VERSION 5.8 ;
BUSBITCHARS "[]" ;
DIVIDERCHAR "/" ;
UNITS
    DATABASE MICRONS 1000 ;
END UNITS

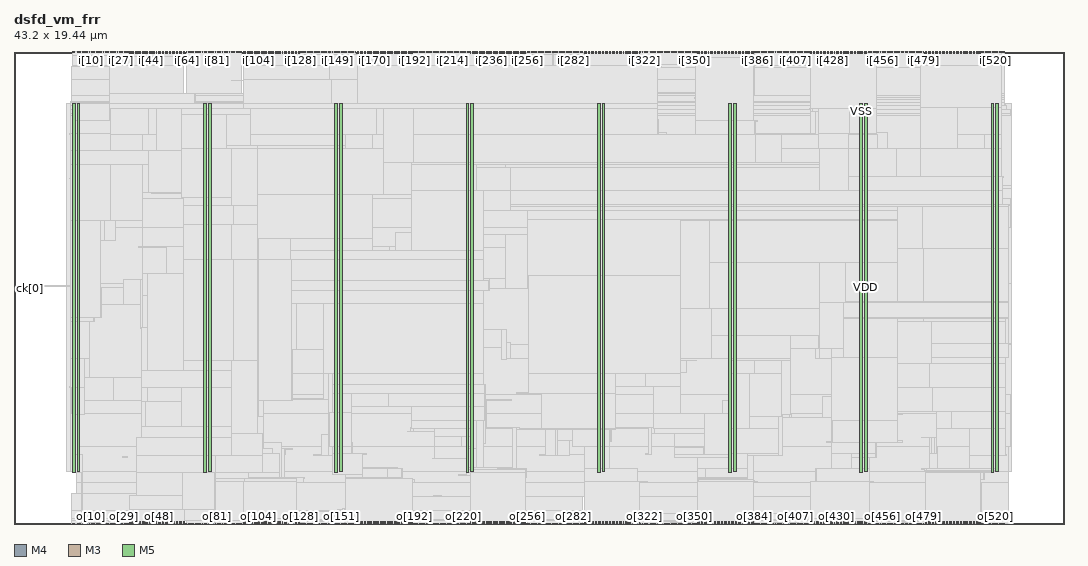
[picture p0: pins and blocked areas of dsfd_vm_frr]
MACRO dsfd_vm_frr
  FOREIGN dsfd_vm_frr 0 0 ;
  CLASS BLOCK ;
  SIZE 43.2 BY 19.44 ;
  PIN ck[0]
    DIRECTION INPUT ;
    USE SIGNAL ;
    PORT
      LAYER M4 ;
        RECT  0 9.696 0.084 9.72 ;
    END
    PORT
      LAYER M4 ;
        RECT  0.06 9.696 0.097 9.72 ;
    END
  END ck[0]
  PIN i[0]
    DIRECTION INPUT ;
    USE SIGNAL ;
    PORT
      LAYER M3 ;
        RECT  2.412 19.402 2.43 19.44 ;
    END
  END i[0]
  PIN i[100]
    DIRECTION INPUT ;
    USE SIGNAL ;
    PORT
      LAYER M5 ;
        RECT  9.744 19.356 9.768 19.44 ;
    END
  END i[100]
  PIN i[101]
    DIRECTION INPUT ;
    USE SIGNAL ;
    PORT
      LAYER M5 ;
        RECT  9.792 19.356 9.816 19.44 ;
    END
  END i[101]
  PIN i[102]
    DIRECTION INPUT ;
    USE SIGNAL ;
    PORT
      LAYER M5 ;
        RECT  9.888 19.356 9.912 19.44 ;
    END
  END i[102]
  PIN i[103]
    DIRECTION INPUT ;
    USE SIGNAL ;
    PORT
      LAYER M5 ;
        RECT  9.936 19.356 9.96 19.44 ;
    END
  END i[103]
  PIN i[104]
    DIRECTION INPUT ;
    USE SIGNAL ;
    PORT
      LAYER M5 ;
        RECT  10.032 19.356 10.056 19.44 ;
    END
  END i[104]
  PIN i[105]
    DIRECTION INPUT ;
    USE SIGNAL ;
    PORT
      LAYER M5 ;
        RECT  10.08 19.356 10.104 19.44 ;
    END
  END i[105]
  PIN i[106]
    DIRECTION INPUT ;
    USE SIGNAL ;
    PORT
      LAYER M5 ;
        RECT  10.176 19.356 10.2 19.44 ;
    END
  END i[106]
  PIN i[107]
    DIRECTION INPUT ;
    USE SIGNAL ;
    PORT
      LAYER M5 ;
        RECT  10.224 19.356 10.248 19.44 ;
    END
  END i[107]
  PIN i[108]
    DIRECTION INPUT ;
    USE SIGNAL ;
    PORT
      LAYER M5 ;
        RECT  10.32 19.356 10.344 19.44 ;
    END
  END i[108]
  PIN i[109]
    DIRECTION INPUT ;
    USE SIGNAL ;
    PORT
      LAYER M5 ;
        RECT  10.368 19.356 10.392 19.44 ;
    END
  END i[109]
  PIN i[10]
    DIRECTION INPUT ;
    USE SIGNAL ;
    PORT
      LAYER M3 ;
        RECT  3.168 19.402 3.186 19.44 ;
    END
  END i[10]
  PIN i[110]
    DIRECTION INPUT ;
    USE SIGNAL ;
    PORT
      LAYER M5 ;
        RECT  10.464 19.356 10.488 19.44 ;
    END
  END i[110]
  PIN i[111]
    DIRECTION INPUT ;
    USE SIGNAL ;
    PORT
      LAYER M5 ;
        RECT  10.512 19.356 10.536 19.44 ;
    END
  END i[111]
  PIN i[112]
    DIRECTION INPUT ;
    USE SIGNAL ;
    PORT
      LAYER M5 ;
        RECT  10.608 19.356 10.632 19.44 ;
    END
  END i[112]
  PIN i[113]
    DIRECTION INPUT ;
    USE SIGNAL ;
    PORT
      LAYER M5 ;
        RECT  10.656 19.356 10.68 19.44 ;
    END
  END i[113]
  PIN i[114]
    DIRECTION INPUT ;
    USE SIGNAL ;
    PORT
      LAYER M5 ;
        RECT  10.752 19.356 10.776 19.44 ;
    END
  END i[114]
  PIN i[115]
    DIRECTION INPUT ;
    USE SIGNAL ;
    PORT
      LAYER M5 ;
        RECT  10.8 19.356 10.824 19.44 ;
    END
  END i[115]
  PIN i[116]
    DIRECTION INPUT ;
    USE SIGNAL ;
    PORT
      LAYER M5 ;
        RECT  10.896 19.356 10.92 19.44 ;
    END
  END i[116]
  PIN i[117]
    DIRECTION INPUT ;
    USE SIGNAL ;
    PORT
      LAYER M5 ;
        RECT  10.944 19.356 10.968 19.44 ;
    END
  END i[117]
  PIN i[118]
    DIRECTION INPUT ;
    USE SIGNAL ;
    PORT
      LAYER M5 ;
        RECT  11.04 19.356 11.064 19.44 ;
    END
  END i[118]
  PIN i[119]
    DIRECTION INPUT ;
    USE SIGNAL ;
    PORT
      LAYER M5 ;
        RECT  11.136 19.356 11.16 19.44 ;
    END
  END i[119]
  PIN i[11]
    DIRECTION INPUT ;
    USE SIGNAL ;
    PORT
      LAYER M3 ;
        RECT  3.24 19.402 3.258 19.44 ;
    END
  END i[11]
  PIN i[120]
    DIRECTION INPUT ;
    USE SIGNAL ;
    PORT
      LAYER M5 ;
        RECT  11.184 19.356 11.208 19.44 ;
    END
  END i[120]
  PIN i[121]
    DIRECTION INPUT ;
    USE SIGNAL ;
    PORT
      LAYER M5 ;
        RECT  11.28 19.356 11.304 19.44 ;
    END
  END i[121]
  PIN i[122]
    DIRECTION INPUT ;
    USE SIGNAL ;
    PORT
      LAYER M5 ;
        RECT  11.328 19.356 11.352 19.44 ;
    END
  END i[122]
  PIN i[123]
    DIRECTION INPUT ;
    USE SIGNAL ;
    PORT
      LAYER M5 ;
        RECT  11.424 19.356 11.448 19.44 ;
    END
  END i[123]
  PIN i[124]
    DIRECTION INPUT ;
    USE SIGNAL ;
    PORT
      LAYER M5 ;
        RECT  11.472 19.356 11.496 19.44 ;
    END
  END i[124]
  PIN i[125]
    DIRECTION INPUT ;
    USE SIGNAL ;
    PORT
      LAYER M5 ;
        RECT  11.568 19.356 11.592 19.44 ;
    END
  END i[125]
  PIN i[126]
    DIRECTION INPUT ;
    USE SIGNAL ;
    PORT
      LAYER M5 ;
        RECT  11.616 19.356 11.64 19.44 ;
    END
  END i[126]
  PIN i[127]
    DIRECTION INPUT ;
    USE SIGNAL ;
    PORT
      LAYER M5 ;
        RECT  11.712 19.356 11.736 19.44 ;
    END
  END i[127]
  PIN i[128]
    DIRECTION INPUT ;
    USE SIGNAL ;
    PORT
      LAYER M3 ;
        RECT  11.772 19.402 11.79 19.44 ;
    END
  END i[128]
  PIN i[129]
    DIRECTION INPUT ;
    USE SIGNAL ;
    PORT
      LAYER M3 ;
        RECT  11.844 19.402 11.862 19.44 ;
    END
  END i[129]
  PIN i[12]
    DIRECTION INPUT ;
    USE SIGNAL ;
    PORT
      LAYER M3 ;
        RECT  3.312 19.402 3.33 19.44 ;
    END
  END i[12]
  PIN i[130]
    DIRECTION INPUT ;
    USE SIGNAL ;
    PORT
      LAYER M3 ;
        RECT  11.916 19.402 11.934 19.44 ;
    END
  END i[130]
  PIN i[131]
    DIRECTION INPUT ;
    USE SIGNAL ;
    PORT
      LAYER M3 ;
        RECT  11.988 19.402 12.006 19.44 ;
    END
  END i[131]
  PIN i[132]
    DIRECTION INPUT ;
    USE SIGNAL ;
    PORT
      LAYER M3 ;
        RECT  12.06 19.402 12.078 19.44 ;
    END
  END i[132]
  PIN i[133]
    DIRECTION INPUT ;
    USE SIGNAL ;
    PORT
      LAYER M3 ;
        RECT  12.132 19.402 12.15 19.44 ;
    END
  END i[133]
  PIN i[134]
    DIRECTION INPUT ;
    USE SIGNAL ;
    PORT
      LAYER M3 ;
        RECT  12.204 19.402 12.222 19.44 ;
    END
  END i[134]
  PIN i[135]
    DIRECTION INPUT ;
    USE SIGNAL ;
    PORT
      LAYER M3 ;
        RECT  12.276 19.402 12.294 19.44 ;
    END
  END i[135]
  PIN i[136]
    DIRECTION INPUT ;
    USE SIGNAL ;
    PORT
      LAYER M3 ;
        RECT  12.348 19.402 12.366 19.44 ;
    END
  END i[136]
  PIN i[137]
    DIRECTION INPUT ;
    USE SIGNAL ;
    PORT
      LAYER M3 ;
        RECT  12.42 19.402 12.438 19.44 ;
    END
  END i[137]
  PIN i[138]
    DIRECTION INPUT ;
    USE SIGNAL ;
    PORT
      LAYER M3 ;
        RECT  12.492 19.402 12.51 19.44 ;
    END
  END i[138]
  PIN i[139]
    DIRECTION INPUT ;
    USE SIGNAL ;
    PORT
      LAYER M3 ;
        RECT  12.564 19.402 12.582 19.44 ;
    END
  END i[139]
  PIN i[13]
    DIRECTION INPUT ;
    USE SIGNAL ;
    PORT
      LAYER M3 ;
        RECT  3.384 19.402 3.402 19.44 ;
    END
  END i[13]
  PIN i[140]
    DIRECTION INPUT ;
    USE SIGNAL ;
    PORT
      LAYER M3 ;
        RECT  12.636 19.402 12.654 19.44 ;
    END
  END i[140]
  PIN i[141]
    DIRECTION INPUT ;
    USE SIGNAL ;
    PORT
      LAYER M3 ;
        RECT  12.708 19.402 12.726 19.44 ;
    END
  END i[141]
  PIN i[142]
    DIRECTION INPUT ;
    USE SIGNAL ;
    PORT
      LAYER M3 ;
        RECT  12.78 19.402 12.798 19.44 ;
    END
  END i[142]
  PIN i[143]
    DIRECTION INPUT ;
    USE SIGNAL ;
    PORT
      LAYER M3 ;
        RECT  12.852 19.402 12.87 19.44 ;
    END
  END i[143]
  PIN i[144]
    DIRECTION INPUT ;
    USE SIGNAL ;
    PORT
      LAYER M3 ;
        RECT  12.924 19.402 12.942 19.44 ;
    END
  END i[144]
  PIN i[145]
    DIRECTION INPUT ;
    USE SIGNAL ;
    PORT
      LAYER M3 ;
        RECT  12.996 19.402 13.014 19.44 ;
    END
  END i[145]
  PIN i[146]
    DIRECTION INPUT ;
    USE SIGNAL ;
    PORT
      LAYER M3 ;
        RECT  13.104 19.402 13.122 19.44 ;
    END
  END i[146]
  PIN i[147]
    DIRECTION INPUT ;
    USE SIGNAL ;
    PORT
      LAYER M3 ;
        RECT  13.176 19.402 13.194 19.44 ;
    END
  END i[147]
  PIN i[148]
    DIRECTION INPUT ;
    USE SIGNAL ;
    PORT
      LAYER M3 ;
        RECT  13.248 19.402 13.266 19.44 ;
    END
  END i[148]
  PIN i[149]
    DIRECTION INPUT ;
    USE SIGNAL ;
    PORT
      LAYER M3 ;
        RECT  13.32 19.402 13.338 19.44 ;
    END
  END i[149]
  PIN i[14]
    DIRECTION INPUT ;
    USE SIGNAL ;
    PORT
      LAYER M3 ;
        RECT  3.456 19.402 3.474 19.44 ;
    END
  END i[14]
  PIN i[150]
    DIRECTION INPUT ;
    USE SIGNAL ;
    PORT
      LAYER M3 ;
        RECT  13.392 19.402 13.41 19.44 ;
    END
  END i[150]
  PIN i[151]
    DIRECTION INPUT ;
    USE SIGNAL ;
    PORT
      LAYER M3 ;
        RECT  13.464 19.402 13.482 19.44 ;
    END
  END i[151]
  PIN i[152]
    DIRECTION INPUT ;
    USE SIGNAL ;
    PORT
      LAYER M3 ;
        RECT  13.536 19.402 13.554 19.44 ;
    END
  END i[152]
  PIN i[153]
    DIRECTION INPUT ;
    USE SIGNAL ;
    PORT
      LAYER M3 ;
        RECT  13.608 19.402 13.626 19.44 ;
    END
  END i[153]
  PIN i[154]
    DIRECTION INPUT ;
    USE SIGNAL ;
    PORT
      LAYER M3 ;
        RECT  13.68 19.402 13.698 19.44 ;
    END
  END i[154]
  PIN i[155]
    DIRECTION INPUT ;
    USE SIGNAL ;
    PORT
      LAYER M3 ;
        RECT  13.752 19.402 13.77 19.44 ;
    END
  END i[155]
  PIN i[156]
    DIRECTION INPUT ;
    USE SIGNAL ;
    PORT
      LAYER M3 ;
        RECT  13.824 19.402 13.842 19.44 ;
    END
  END i[156]
  PIN i[157]
    DIRECTION INPUT ;
    USE SIGNAL ;
    PORT
      LAYER M3 ;
        RECT  13.896 19.402 13.914 19.44 ;
    END
  END i[157]
  PIN i[158]
    DIRECTION INPUT ;
    USE SIGNAL ;
    PORT
      LAYER M3 ;
        RECT  13.968 19.402 13.986 19.44 ;
    END
  END i[158]
  PIN i[159]
    DIRECTION INPUT ;
    USE SIGNAL ;
    PORT
      LAYER M3 ;
        RECT  14.04 19.402 14.058 19.44 ;
    END
  END i[159]
  PIN i[15]
    DIRECTION INPUT ;
    USE SIGNAL ;
    PORT
      LAYER M3 ;
        RECT  3.528 19.402 3.546 19.44 ;
    END
  END i[15]
  PIN i[160]
    DIRECTION INPUT ;
    USE SIGNAL ;
    PORT
      LAYER M5 ;
        RECT  14.112 19.356 14.136 19.44 ;
    END
  END i[160]
  PIN i[161]
    DIRECTION INPUT ;
    USE SIGNAL ;
    PORT
      LAYER M5 ;
        RECT  14.16 19.356 14.184 19.44 ;
    END
  END i[161]
  PIN i[162]
    DIRECTION INPUT ;
    USE SIGNAL ;
    PORT
      LAYER M5 ;
        RECT  14.256 19.356 14.28 19.44 ;
    END
  END i[162]
  PIN i[163]
    DIRECTION INPUT ;
    USE SIGNAL ;
    PORT
      LAYER M5 ;
        RECT  14.304 19.356 14.328 19.44 ;
    END
  END i[163]
  PIN i[164]
    DIRECTION INPUT ;
    USE SIGNAL ;
    PORT
      LAYER M5 ;
        RECT  14.4 19.356 14.424 19.44 ;
    END
  END i[164]
  PIN i[165]
    DIRECTION INPUT ;
    USE SIGNAL ;
    PORT
      LAYER M5 ;
        RECT  14.448 19.356 14.472 19.44 ;
    END
  END i[165]
  PIN i[166]
    DIRECTION INPUT ;
    USE SIGNAL ;
    PORT
      LAYER M5 ;
        RECT  14.544 19.356 14.568 19.44 ;
    END
  END i[166]
  PIN i[167]
    DIRECTION INPUT ;
    USE SIGNAL ;
    PORT
      LAYER M5 ;
        RECT  14.64 19.356 14.664 19.44 ;
    END
  END i[167]
  PIN i[168]
    DIRECTION INPUT ;
    USE SIGNAL ;
    PORT
      LAYER M5 ;
        RECT  14.688 19.356 14.712 19.44 ;
    END
  END i[168]
  PIN i[169]
    DIRECTION INPUT ;
    USE SIGNAL ;
    PORT
      LAYER M5 ;
        RECT  14.784 19.356 14.808 19.44 ;
    END
  END i[169]
  PIN i[16]
    DIRECTION INPUT ;
    USE SIGNAL ;
    PORT
      LAYER M3 ;
        RECT  3.6 19.402 3.618 19.44 ;
    END
  END i[16]
  PIN i[170]
    DIRECTION INPUT ;
    USE SIGNAL ;
    PORT
      LAYER M5 ;
        RECT  14.832 19.356 14.856 19.44 ;
    END
  END i[170]
  PIN i[171]
    DIRECTION INPUT ;
    USE SIGNAL ;
    PORT
      LAYER M5 ;
        RECT  14.928 19.356 14.952 19.44 ;
    END
  END i[171]
  PIN i[172]
    DIRECTION INPUT ;
    USE SIGNAL ;
    PORT
      LAYER M5 ;
        RECT  14.976 19.356 15 19.44 ;
    END
  END i[172]
  PIN i[173]
    DIRECTION INPUT ;
    USE SIGNAL ;
    PORT
      LAYER M5 ;
        RECT  15.072 19.356 15.096 19.44 ;
    END
  END i[173]
  PIN i[174]
    DIRECTION INPUT ;
    USE SIGNAL ;
    PORT
      LAYER M5 ;
        RECT  15.12 19.356 15.144 19.44 ;
    END
  END i[174]
  PIN i[175]
    DIRECTION INPUT ;
    USE SIGNAL ;
    PORT
      LAYER M5 ;
        RECT  15.216 19.356 15.24 19.44 ;
    END
  END i[175]
  PIN i[176]
    DIRECTION INPUT ;
    USE SIGNAL ;
    PORT
      LAYER M5 ;
        RECT  15.264 19.356 15.288 19.44 ;
    END
  END i[176]
  PIN i[177]
    DIRECTION INPUT ;
    USE SIGNAL ;
    PORT
      LAYER M5 ;
        RECT  15.36 19.356 15.384 19.44 ;
    END
  END i[177]
  PIN i[178]
    DIRECTION INPUT ;
    USE SIGNAL ;
    PORT
      LAYER M5 ;
        RECT  15.408 19.356 15.432 19.44 ;
    END
  END i[178]
  PIN i[179]
    DIRECTION INPUT ;
    USE SIGNAL ;
    PORT
      LAYER M5 ;
        RECT  15.504 19.356 15.528 19.44 ;
    END
  END i[179]
  PIN i[17]
    DIRECTION INPUT ;
    USE SIGNAL ;
    PORT
      LAYER M3 ;
        RECT  3.672 19.402 3.69 19.44 ;
    END
  END i[17]
  PIN i[180]
    DIRECTION INPUT ;
    USE SIGNAL ;
    PORT
      LAYER M5 ;
        RECT  15.552 19.356 15.576 19.44 ;
    END
  END i[180]
  PIN i[181]
    DIRECTION INPUT ;
    USE SIGNAL ;
    PORT
      LAYER M5 ;
        RECT  15.648 19.356 15.672 19.44 ;
    END
  END i[181]
  PIN i[182]
    DIRECTION INPUT ;
    USE SIGNAL ;
    PORT
      LAYER M5 ;
        RECT  15.696 19.356 15.72 19.44 ;
    END
  END i[182]
  PIN i[183]
    DIRECTION INPUT ;
    USE SIGNAL ;
    PORT
      LAYER M5 ;
        RECT  15.792 19.356 15.816 19.44 ;
    END
  END i[183]
  PIN i[184]
    DIRECTION INPUT ;
    USE SIGNAL ;
    PORT
      LAYER M5 ;
        RECT  15.84 19.356 15.864 19.44 ;
    END
  END i[184]
  PIN i[185]
    DIRECTION INPUT ;
    USE SIGNAL ;
    PORT
      LAYER M5 ;
        RECT  15.936 19.356 15.96 19.44 ;
    END
  END i[185]
  PIN i[186]
    DIRECTION INPUT ;
    USE SIGNAL ;
    PORT
      LAYER M5 ;
        RECT  15.984 19.356 16.008 19.44 ;
    END
  END i[186]
  PIN i[187]
    DIRECTION INPUT ;
    USE SIGNAL ;
    PORT
      LAYER M5 ;
        RECT  16.08 19.356 16.104 19.44 ;
    END
  END i[187]
  PIN i[188]
    DIRECTION INPUT ;
    USE SIGNAL ;
    PORT
      LAYER M5 ;
        RECT  16.128 19.356 16.152 19.44 ;
    END
  END i[188]
  PIN i[189]
    DIRECTION INPUT ;
    USE SIGNAL ;
    PORT
      LAYER M5 ;
        RECT  16.224 19.356 16.248 19.44 ;
    END
  END i[189]
  PIN i[18]
    DIRECTION INPUT ;
    USE SIGNAL ;
    PORT
      LAYER M3 ;
        RECT  3.744 19.402 3.762 19.44 ;
    END
  END i[18]
  PIN i[190]
    DIRECTION INPUT ;
    USE SIGNAL ;
    PORT
      LAYER M5 ;
        RECT  16.272 19.356 16.296 19.44 ;
    END
  END i[190]
  PIN i[191]
    DIRECTION INPUT ;
    USE SIGNAL ;
    PORT
      LAYER M5 ;
        RECT  16.368 19.356 16.392 19.44 ;
    END
  END i[191]
  PIN i[192]
    DIRECTION INPUT ;
    USE SIGNAL ;
    PORT
      LAYER M3 ;
        RECT  16.452 19.402 16.47 19.44 ;
    END
  END i[192]
  PIN i[193]
    DIRECTION INPUT ;
    USE SIGNAL ;
    PORT
      LAYER M3 ;
        RECT  16.524 19.402 16.542 19.44 ;
    END
  END i[193]
  PIN i[194]
    DIRECTION INPUT ;
    USE SIGNAL ;
    PORT
      LAYER M3 ;
        RECT  16.596 19.402 16.614 19.44 ;
    END
  END i[194]
  PIN i[195]
    DIRECTION INPUT ;
    USE SIGNAL ;
    PORT
      LAYER M3 ;
        RECT  16.668 19.402 16.686 19.44 ;
    END
  END i[195]
  PIN i[196]
    DIRECTION INPUT ;
    USE SIGNAL ;
    PORT
      LAYER M3 ;
        RECT  16.74 19.402 16.758 19.44 ;
    END
  END i[196]
  PIN i[197]
    DIRECTION INPUT ;
    USE SIGNAL ;
    PORT
      LAYER M3 ;
        RECT  16.812 19.402 16.83 19.44 ;
    END
  END i[197]
  PIN i[198]
    DIRECTION INPUT ;
    USE SIGNAL ;
    PORT
      LAYER M3 ;
        RECT  16.884 19.402 16.902 19.44 ;
    END
  END i[198]
  PIN i[199]
    DIRECTION INPUT ;
    USE SIGNAL ;
    PORT
      LAYER M3 ;
        RECT  16.956 19.402 16.974 19.44 ;
    END
  END i[199]
  PIN i[19]
    DIRECTION INPUT ;
    USE SIGNAL ;
    PORT
      LAYER M3 ;
        RECT  3.816 19.402 3.834 19.44 ;
    END
  END i[19]
  PIN i[1]
    DIRECTION INPUT ;
    USE SIGNAL ;
    PORT
      LAYER M3 ;
        RECT  2.484 19.402 2.502 19.44 ;
    END
  END i[1]
  PIN i[200]
    DIRECTION INPUT ;
    USE SIGNAL ;
    PORT
      LAYER M3 ;
        RECT  17.028 19.402 17.046 19.44 ;
    END
  END i[200]
  PIN i[201]
    DIRECTION INPUT ;
    USE SIGNAL ;
    PORT
      LAYER M3 ;
        RECT  17.1 19.402 17.118 19.44 ;
    END
  END i[201]
  PIN i[202]
    DIRECTION INPUT ;
    USE SIGNAL ;
    PORT
      LAYER M3 ;
        RECT  17.172 19.402 17.19 19.44 ;
    END
  END i[202]
  PIN i[203]
    DIRECTION INPUT ;
    USE SIGNAL ;
    PORT
      LAYER M3 ;
        RECT  17.244 19.402 17.262 19.44 ;
    END
  END i[203]
  PIN i[204]
    DIRECTION INPUT ;
    USE SIGNAL ;
    PORT
      LAYER M3 ;
        RECT  17.316 19.402 17.334 19.44 ;
    END
  END i[204]
  PIN i[205]
    DIRECTION INPUT ;
    USE SIGNAL ;
    PORT
      LAYER M3 ;
        RECT  17.388 19.402 17.406 19.44 ;
    END
  END i[205]
  PIN i[206]
    DIRECTION INPUT ;
    USE SIGNAL ;
    PORT
      LAYER M3 ;
        RECT  17.46 19.402 17.478 19.44 ;
    END
  END i[206]
  PIN i[207]
    DIRECTION INPUT ;
    USE SIGNAL ;
    PORT
      LAYER M3 ;
        RECT  17.532 19.402 17.55 19.44 ;
    END
  END i[207]
  PIN i[208]
    DIRECTION INPUT ;
    USE SIGNAL ;
    PORT
      LAYER M3 ;
        RECT  17.604 19.402 17.622 19.44 ;
    END
  END i[208]
  PIN i[209]
    DIRECTION INPUT ;
    USE SIGNAL ;
    PORT
      LAYER M3 ;
        RECT  17.676 19.402 17.694 19.44 ;
    END
  END i[209]
  PIN i[20]
    DIRECTION INPUT ;
    USE SIGNAL ;
    PORT
      LAYER M3 ;
        RECT  3.888 19.402 3.906 19.44 ;
    END
  END i[20]
  PIN i[210]
    DIRECTION INPUT ;
    USE SIGNAL ;
    PORT
      LAYER M3 ;
        RECT  17.748 19.402 17.766 19.44 ;
    END
  END i[210]
  PIN i[211]
    DIRECTION INPUT ;
    USE SIGNAL ;
    PORT
      LAYER M3 ;
        RECT  17.82 19.402 17.838 19.44 ;
    END
  END i[211]
  PIN i[212]
    DIRECTION INPUT ;
    USE SIGNAL ;
    PORT
      LAYER M3 ;
        RECT  17.892 19.402 17.91 19.44 ;
    END
  END i[212]
  PIN i[213]
    DIRECTION INPUT ;
    USE SIGNAL ;
    PORT
      LAYER M3 ;
        RECT  17.964 19.402 17.982 19.44 ;
    END
  END i[213]
  PIN i[214]
    DIRECTION INPUT ;
    USE SIGNAL ;
    PORT
      LAYER M3 ;
        RECT  18.036 19.402 18.054 19.44 ;
    END
  END i[214]
  PIN i[215]
    DIRECTION INPUT ;
    USE SIGNAL ;
    PORT
      LAYER M3 ;
        RECT  18.108 19.402 18.126 19.44 ;
    END
  END i[215]
  PIN i[216]
    DIRECTION INPUT ;
    USE SIGNAL ;
    PORT
      LAYER M3 ;
        RECT  18.18 19.402 18.198 19.44 ;
    END
  END i[216]
  PIN i[217]
    DIRECTION INPUT ;
    USE SIGNAL ;
    PORT
      LAYER M3 ;
        RECT  18.252 19.402 18.27 19.44 ;
    END
  END i[217]
  PIN i[218]
    DIRECTION INPUT ;
    USE SIGNAL ;
    PORT
      LAYER M3 ;
        RECT  18.36 19.402 18.378 19.44 ;
    END
  END i[218]
  PIN i[219]
    DIRECTION INPUT ;
    USE SIGNAL ;
    PORT
      LAYER M3 ;
        RECT  18.432 19.402 18.45 19.44 ;
    END
  END i[219]
  PIN i[21]
    DIRECTION INPUT ;
    USE SIGNAL ;
    PORT
      LAYER M3 ;
        RECT  3.96 19.402 3.978 19.44 ;
    END
  END i[21]
  PIN i[220]
    DIRECTION INPUT ;
    USE SIGNAL ;
    PORT
      LAYER M3 ;
        RECT  18.504 19.402 18.522 19.44 ;
    END
  END i[220]
  PIN i[221]
    DIRECTION INPUT ;
    USE SIGNAL ;
    PORT
      LAYER M3 ;
        RECT  18.576 19.402 18.594 19.44 ;
    END
  END i[221]
  PIN i[222]
    DIRECTION INPUT ;
    USE SIGNAL ;
    PORT
      LAYER M3 ;
        RECT  18.648 19.402 18.666 19.44 ;
    END
  END i[222]
  PIN i[223]
    DIRECTION INPUT ;
    USE SIGNAL ;
    PORT
      LAYER M3 ;
        RECT  18.72 19.402 18.738 19.44 ;
    END
  END i[223]
  PIN i[224]
    DIRECTION INPUT ;
    USE SIGNAL ;
    PORT
      LAYER M5 ;
        RECT  18.768 19.356 18.792 19.44 ;
    END
  END i[224]
  PIN i[225]
    DIRECTION INPUT ;
    USE SIGNAL ;
    PORT
      LAYER M5 ;
        RECT  18.864 19.356 18.888 19.44 ;
    END
  END i[225]
  PIN i[226]
    DIRECTION INPUT ;
    USE SIGNAL ;
    PORT
      LAYER M5 ;
        RECT  18.912 19.356 18.936 19.44 ;
    END
  END i[226]
  PIN i[227]
    DIRECTION INPUT ;
    USE SIGNAL ;
    PORT
      LAYER M5 ;
        RECT  19.008 19.356 19.032 19.44 ;
    END
  END i[227]
  PIN i[228]
    DIRECTION INPUT ;
    USE SIGNAL ;
    PORT
      LAYER M5 ;
        RECT  19.056 19.356 19.08 19.44 ;
    END
  END i[228]
  PIN i[229]
    DIRECTION INPUT ;
    USE SIGNAL ;
    PORT
      LAYER M5 ;
        RECT  19.152 19.356 19.176 19.44 ;
    END
  END i[229]
  PIN i[22]
    DIRECTION INPUT ;
    USE SIGNAL ;
    PORT
      LAYER M3 ;
        RECT  4.032 19.402 4.05 19.44 ;
    END
  END i[22]
  PIN i[230]
    DIRECTION INPUT ;
    USE SIGNAL ;
    PORT
      LAYER M5 ;
        RECT  19.2 19.356 19.224 19.44 ;
    END
  END i[230]
  PIN i[231]
    DIRECTION INPUT ;
    USE SIGNAL ;
    PORT
      LAYER M5 ;
        RECT  19.296 19.356 19.32 19.44 ;
    END
  END i[231]
  PIN i[232]
    DIRECTION INPUT ;
    USE SIGNAL ;
    PORT
      LAYER M5 ;
        RECT  19.344 19.356 19.368 19.44 ;
    END
  END i[232]
  PIN i[233]
    DIRECTION INPUT ;
    USE SIGNAL ;
    PORT
      LAYER M5 ;
        RECT  19.44 19.356 19.464 19.44 ;
    END
  END i[233]
  PIN i[234]
    DIRECTION INPUT ;
    USE SIGNAL ;
    PORT
      LAYER M5 ;
        RECT  19.488 19.356 19.512 19.44 ;
    END
  END i[234]
  PIN i[235]
    DIRECTION INPUT ;
    USE SIGNAL ;
    PORT
      LAYER M5 ;
        RECT  19.584 19.356 19.608 19.44 ;
    END
  END i[235]
  PIN i[236]
    DIRECTION INPUT ;
    USE SIGNAL ;
    PORT
      LAYER M5 ;
        RECT  19.632 19.356 19.656 19.44 ;
    END
  END i[236]
  PIN i[237]
    DIRECTION INPUT ;
    USE SIGNAL ;
    PORT
      LAYER M5 ;
        RECT  19.728 19.356 19.752 19.44 ;
    END
  END i[237]
  PIN i[238]
    DIRECTION INPUT ;
    USE SIGNAL ;
    PORT
      LAYER M5 ;
        RECT  19.776 19.356 19.8 19.44 ;
    END
  END i[238]
  PIN i[239]
    DIRECTION INPUT ;
    USE SIGNAL ;
    PORT
      LAYER M5 ;
        RECT  19.872 19.356 19.896 19.44 ;
    END
  END i[239]
  PIN i[23]
    DIRECTION INPUT ;
    USE SIGNAL ;
    PORT
      LAYER M3 ;
        RECT  4.104 19.402 4.122 19.44 ;
    END
  END i[23]
  PIN i[240]
    DIRECTION INPUT ;
    USE SIGNAL ;
    PORT
      LAYER M5 ;
        RECT  19.968 19.356 19.992 19.44 ;
    END
  END i[240]
  PIN i[241]
    DIRECTION INPUT ;
    USE SIGNAL ;
    PORT
      LAYER M5 ;
        RECT  20.016 19.356 20.04 19.44 ;
    END
  END i[241]
  PIN i[242]
    DIRECTION INPUT ;
    USE SIGNAL ;
    PORT
      LAYER M5 ;
        RECT  20.112 19.356 20.136 19.44 ;
    END
  END i[242]
  PIN i[243]
    DIRECTION INPUT ;
    USE SIGNAL ;
    PORT
      LAYER M5 ;
        RECT  20.16 19.356 20.184 19.44 ;
    END
  END i[243]
  PIN i[244]
    DIRECTION INPUT ;
    USE SIGNAL ;
    PORT
      LAYER M5 ;
        RECT  20.256 19.356 20.28 19.44 ;
    END
  END i[244]
  PIN i[245]
    DIRECTION INPUT ;
    USE SIGNAL ;
    PORT
      LAYER M5 ;
        RECT  20.304 19.356 20.328 19.44 ;
    END
  END i[245]
  PIN i[246]
    DIRECTION INPUT ;
    USE SIGNAL ;
    PORT
      LAYER M5 ;
        RECT  20.4 19.356 20.424 19.44 ;
    END
  END i[246]
  PIN i[247]
    DIRECTION INPUT ;
    USE SIGNAL ;
    PORT
      LAYER M5 ;
        RECT  20.448 19.356 20.472 19.44 ;
    END
  END i[247]
  PIN i[248]
    DIRECTION INPUT ;
    USE SIGNAL ;
    PORT
      LAYER M5 ;
        RECT  20.544 19.356 20.568 19.44 ;
    END
  END i[248]
  PIN i[249]
    DIRECTION INPUT ;
    USE SIGNAL ;
    PORT
      LAYER M5 ;
        RECT  20.592 19.356 20.616 19.44 ;
    END
  END i[249]
  PIN i[24]
    DIRECTION INPUT ;
    USE SIGNAL ;
    PORT
      LAYER M3 ;
        RECT  4.176 19.402 4.194 19.44 ;
    END
  END i[24]
  PIN i[250]
    DIRECTION INPUT ;
    USE SIGNAL ;
    PORT
      LAYER M5 ;
        RECT  20.688 19.356 20.712 19.44 ;
    END
  END i[250]
  PIN i[251]
    DIRECTION INPUT ;
    USE SIGNAL ;
    PORT
      LAYER M5 ;
        RECT  20.736 19.356 20.76 19.44 ;
    END
  END i[251]
  PIN i[252]
    DIRECTION INPUT ;
    USE SIGNAL ;
    PORT
      LAYER M5 ;
        RECT  20.832 19.356 20.856 19.44 ;
    END
  END i[252]
  PIN i[253]
    DIRECTION INPUT ;
    USE SIGNAL ;
    PORT
      LAYER M5 ;
        RECT  20.88 19.356 20.904 19.44 ;
    END
  END i[253]
  PIN i[254]
    DIRECTION INPUT ;
    USE SIGNAL ;
    PORT
      LAYER M5 ;
        RECT  20.976 19.356 21 19.44 ;
    END
  END i[254]
  PIN i[255]
    DIRECTION INPUT ;
    USE SIGNAL ;
    PORT
      LAYER M5 ;
        RECT  21.024 19.356 21.048 19.44 ;
    END
  END i[255]
  PIN i[256]
    DIRECTION INPUT ;
    USE SIGNAL ;
    PORT
      LAYER M3 ;
        RECT  21.132 19.402 21.15 19.44 ;
    END
  END i[256]
  PIN i[257]
    DIRECTION INPUT ;
    USE SIGNAL ;
    PORT
      LAYER M3 ;
        RECT  21.204 19.402 21.222 19.44 ;
    END
  END i[257]
  PIN i[258]
    DIRECTION INPUT ;
    USE SIGNAL ;
    PORT
      LAYER M3 ;
        RECT  21.276 19.402 21.294 19.44 ;
    END
  END i[258]
  PIN i[259]
    DIRECTION INPUT ;
    USE SIGNAL ;
    PORT
      LAYER M3 ;
        RECT  21.348 19.402 21.366 19.44 ;
    END
  END i[259]
  PIN i[25]
    DIRECTION INPUT ;
    USE SIGNAL ;
    PORT
      LAYER M3 ;
        RECT  4.248 19.402 4.266 19.44 ;
    END
  END i[25]
  PIN i[260]
    DIRECTION INPUT ;
    USE SIGNAL ;
    PORT
      LAYER M3 ;
        RECT  21.42 19.402 21.438 19.44 ;
    END
  END i[260]
  PIN i[261]
    DIRECTION INPUT ;
    USE SIGNAL ;
    PORT
      LAYER M3 ;
        RECT  21.492 19.402 21.51 19.44 ;
    END
  END i[261]
  PIN i[262]
    DIRECTION INPUT ;
    USE SIGNAL ;
    PORT
      LAYER M3 ;
        RECT  21.564 19.402 21.582 19.44 ;
    END
  END i[262]
  PIN i[263]
    DIRECTION INPUT ;
    USE SIGNAL ;
    PORT
      LAYER M3 ;
        RECT  21.636 19.402 21.654 19.44 ;
    END
  END i[263]
  PIN i[264]
    DIRECTION INPUT ;
    USE SIGNAL ;
    PORT
      LAYER M3 ;
        RECT  21.708 19.402 21.726 19.44 ;
    END
  END i[264]
  PIN i[265]
    DIRECTION INPUT ;
    USE SIGNAL ;
    PORT
      LAYER M3 ;
        RECT  21.78 19.402 21.798 19.44 ;
    END
  END i[265]
  PIN i[266]
    DIRECTION INPUT ;
    USE SIGNAL ;
    PORT
      LAYER M3 ;
        RECT  21.852 19.402 21.87 19.44 ;
    END
  END i[266]
  PIN i[267]
    DIRECTION INPUT ;
    USE SIGNAL ;
    PORT
      LAYER M3 ;
        RECT  21.924 19.402 21.942 19.44 ;
    END
  END i[267]
  PIN i[268]
    DIRECTION INPUT ;
    USE SIGNAL ;
    PORT
      LAYER M3 ;
        RECT  21.996 19.402 22.014 19.44 ;
    END
  END i[268]
  PIN i[269]
    DIRECTION INPUT ;
    USE SIGNAL ;
    PORT
      LAYER M3 ;
        RECT  22.068 19.402 22.086 19.44 ;
    END
  END i[269]
  PIN i[26]
    DIRECTION INPUT ;
    USE SIGNAL ;
    PORT
      LAYER M3 ;
        RECT  4.32 19.402 4.338 19.44 ;
    END
  END i[26]
  PIN i[270]
    DIRECTION INPUT ;
    USE SIGNAL ;
    PORT
      LAYER M3 ;
        RECT  22.14 19.402 22.158 19.44 ;
    END
  END i[270]
  PIN i[271]
    DIRECTION INPUT ;
    USE SIGNAL ;
    PORT
      LAYER M3 ;
        RECT  22.212 19.402 22.23 19.44 ;
    END
  END i[271]
  PIN i[272]
    DIRECTION INPUT ;
    USE SIGNAL ;
    PORT
      LAYER M3 ;
        RECT  22.284 19.402 22.302 19.44 ;
    END
  END i[272]
  PIN i[273]
    DIRECTION INPUT ;
    USE SIGNAL ;
    PORT
      LAYER M3 ;
        RECT  22.356 19.402 22.374 19.44 ;
    END
  END i[273]
  PIN i[274]
    DIRECTION INPUT ;
    USE SIGNAL ;
    PORT
      LAYER M3 ;
        RECT  22.428 19.402 22.446 19.44 ;
    END
  END i[274]
  PIN i[275]
    DIRECTION INPUT ;
    USE SIGNAL ;
    PORT
      LAYER M3 ;
        RECT  22.5 19.402 22.518 19.44 ;
    END
  END i[275]
  PIN i[276]
    DIRECTION INPUT ;
    USE SIGNAL ;
    PORT
      LAYER M3 ;
        RECT  22.572 19.402 22.59 19.44 ;
    END
  END i[276]
  PIN i[277]
    DIRECTION INPUT ;
    USE SIGNAL ;
    PORT
      LAYER M3 ;
        RECT  22.644 19.402 22.662 19.44 ;
    END
  END i[277]
  PIN i[278]
    DIRECTION INPUT ;
    USE SIGNAL ;
    PORT
      LAYER M3 ;
        RECT  22.716 19.402 22.734 19.44 ;
    END
  END i[278]
  PIN i[279]
    DIRECTION INPUT ;
    USE SIGNAL ;
    PORT
      LAYER M3 ;
        RECT  22.788 19.402 22.806 19.44 ;
    END
  END i[279]
  PIN i[27]
    DIRECTION INPUT ;
    USE SIGNAL ;
    PORT
      LAYER M3 ;
        RECT  4.392 19.402 4.41 19.44 ;
    END
  END i[27]
  PIN i[280]
    DIRECTION INPUT ;
    USE SIGNAL ;
    PORT
      LAYER M3 ;
        RECT  22.86 19.402 22.878 19.44 ;
    END
  END i[280]
  PIN i[281]
    DIRECTION INPUT ;
    USE SIGNAL ;
    PORT
      LAYER M3 ;
        RECT  22.932 19.402 22.95 19.44 ;
    END
  END i[281]
  PIN i[282]
    DIRECTION INPUT ;
    USE SIGNAL ;
    PORT
      LAYER M3 ;
        RECT  23.004 19.402 23.022 19.44 ;
    END
  END i[282]
  PIN i[283]
    DIRECTION INPUT ;
    USE SIGNAL ;
    PORT
      LAYER M3 ;
        RECT  23.076 19.402 23.094 19.44 ;
    END
  END i[283]
  PIN i[284]
    DIRECTION INPUT ;
    USE SIGNAL ;
    PORT
      LAYER M3 ;
        RECT  23.148 19.402 23.166 19.44 ;
    END
  END i[284]
  PIN i[285]
    DIRECTION INPUT ;
    USE SIGNAL ;
    PORT
      LAYER M3 ;
        RECT  23.22 19.402 23.238 19.44 ;
    END
  END i[285]
  PIN i[286]
    DIRECTION INPUT ;
    USE SIGNAL ;
    PORT
      LAYER M3 ;
        RECT  23.292 19.402 23.31 19.44 ;
    END
  END i[286]
  PIN i[287]
    DIRECTION INPUT ;
    USE SIGNAL ;
    PORT
      LAYER M3 ;
        RECT  23.364 19.402 23.382 19.44 ;
    END
  END i[287]
  PIN i[288]
    DIRECTION INPUT ;
    USE SIGNAL ;
    PORT
      LAYER M5 ;
        RECT  23.472 19.356 23.496 19.44 ;
    END
  END i[288]
  PIN i[289]
    DIRECTION INPUT ;
    USE SIGNAL ;
    PORT
      LAYER M5 ;
        RECT  23.52 19.356 23.544 19.44 ;
    END
  END i[289]
  PIN i[28]
    DIRECTION INPUT ;
    USE SIGNAL ;
    PORT
      LAYER M3 ;
        RECT  4.464 19.402 4.482 19.44 ;
    END
  END i[28]
  PIN i[290]
    DIRECTION INPUT ;
    USE SIGNAL ;
    PORT
      LAYER M5 ;
        RECT  23.616 19.356 23.64 19.44 ;
    END
  END i[290]
  PIN i[291]
    DIRECTION INPUT ;
    USE SIGNAL ;
    PORT
      LAYER M5 ;
        RECT  23.664 19.356 23.688 19.44 ;
    END
  END i[291]
  PIN i[292]
    DIRECTION INPUT ;
    USE SIGNAL ;
    PORT
      LAYER M5 ;
        RECT  23.76 19.356 23.784 19.44 ;
    END
  END i[292]
  PIN i[293]
    DIRECTION INPUT ;
    USE SIGNAL ;
    PORT
      LAYER M5 ;
        RECT  23.808 19.356 23.832 19.44 ;
    END
  END i[293]
  PIN i[294]
    DIRECTION INPUT ;
    USE SIGNAL ;
    PORT
      LAYER M5 ;
        RECT  23.904 19.356 23.928 19.44 ;
    END
  END i[294]
  PIN i[295]
    DIRECTION INPUT ;
    USE SIGNAL ;
    PORT
      LAYER M5 ;
        RECT  23.952 19.356 23.976 19.44 ;
    END
  END i[295]
  PIN i[296]
    DIRECTION INPUT ;
    USE SIGNAL ;
    PORT
      LAYER M5 ;
        RECT  24.048 19.356 24.072 19.44 ;
    END
  END i[296]
  PIN i[297]
    DIRECTION INPUT ;
    USE SIGNAL ;
    PORT
      LAYER M5 ;
        RECT  24.096 19.356 24.12 19.44 ;
    END
  END i[297]
  PIN i[298]
    DIRECTION INPUT ;
    USE SIGNAL ;
    PORT
      LAYER M5 ;
        RECT  24.192 19.356 24.216 19.44 ;
    END
  END i[298]
  PIN i[299]
    DIRECTION INPUT ;
    USE SIGNAL ;
    PORT
      LAYER M5 ;
        RECT  24.24 19.356 24.264 19.44 ;
    END
  END i[299]
  PIN i[29]
    DIRECTION INPUT ;
    USE SIGNAL ;
    PORT
      LAYER M3 ;
        RECT  4.536 19.402 4.554 19.44 ;
    END
  END i[29]
  PIN i[2]
    DIRECTION INPUT ;
    USE SIGNAL ;
    PORT
      LAYER M3 ;
        RECT  2.592 19.402 2.61 19.44 ;
    END
  END i[2]
  PIN i[300]
    DIRECTION INPUT ;
    USE SIGNAL ;
    PORT
      LAYER M5 ;
        RECT  24.336 19.356 24.36 19.44 ;
    END
  END i[300]
  PIN i[301]
    DIRECTION INPUT ;
    USE SIGNAL ;
    PORT
      LAYER M5 ;
        RECT  24.384 19.356 24.408 19.44 ;
    END
  END i[301]
  PIN i[302]
    DIRECTION INPUT ;
    USE SIGNAL ;
    PORT
      LAYER M5 ;
        RECT  24.48 19.356 24.504 19.44 ;
    END
  END i[302]
  PIN i[303]
    DIRECTION INPUT ;
    USE SIGNAL ;
    PORT
      LAYER M5 ;
        RECT  24.528 19.356 24.552 19.44 ;
    END
  END i[303]
  PIN i[304]
    DIRECTION INPUT ;
    USE SIGNAL ;
    PORT
      LAYER M5 ;
        RECT  24.624 19.356 24.648 19.44 ;
    END
  END i[304]
  PIN i[305]
    DIRECTION INPUT ;
    USE SIGNAL ;
    PORT
      LAYER M5 ;
        RECT  24.672 19.356 24.696 19.44 ;
    END
  END i[305]
  PIN i[306]
    DIRECTION INPUT ;
    USE SIGNAL ;
    PORT
      LAYER M5 ;
        RECT  24.768 19.356 24.792 19.44 ;
    END
  END i[306]
  PIN i[307]
    DIRECTION INPUT ;
    USE SIGNAL ;
    PORT
      LAYER M5 ;
        RECT  24.816 19.356 24.84 19.44 ;
    END
  END i[307]
  PIN i[308]
    DIRECTION INPUT ;
    USE SIGNAL ;
    PORT
      LAYER M5 ;
        RECT  24.912 19.356 24.936 19.44 ;
    END
  END i[308]
  PIN i[309]
    DIRECTION INPUT ;
    USE SIGNAL ;
    PORT
      LAYER M5 ;
        RECT  24.96 19.356 24.984 19.44 ;
    END
  END i[309]
  PIN i[30]
    DIRECTION INPUT ;
    USE SIGNAL ;
    PORT
      LAYER M3 ;
        RECT  4.608 19.402 4.626 19.44 ;
    END
  END i[30]
  PIN i[310]
    DIRECTION INPUT ;
    USE SIGNAL ;
    PORT
      LAYER M5 ;
        RECT  25.056 19.356 25.08 19.44 ;
    END
  END i[310]
  PIN i[311]
    DIRECTION INPUT ;
    USE SIGNAL ;
    PORT
      LAYER M5 ;
        RECT  25.152 19.356 25.176 19.44 ;
    END
  END i[311]
  PIN i[312]
    DIRECTION INPUT ;
    USE SIGNAL ;
    PORT
      LAYER M5 ;
        RECT  25.2 19.356 25.224 19.44 ;
    END
  END i[312]
  PIN i[313]
    DIRECTION INPUT ;
    USE SIGNAL ;
    PORT
      LAYER M5 ;
        RECT  25.296 19.356 25.32 19.44 ;
    END
  END i[313]
  PIN i[314]
    DIRECTION INPUT ;
    USE SIGNAL ;
    PORT
      LAYER M5 ;
        RECT  25.344 19.356 25.368 19.44 ;
    END
  END i[314]
  PIN i[315]
    DIRECTION INPUT ;
    USE SIGNAL ;
    PORT
      LAYER M5 ;
        RECT  25.44 19.356 25.464 19.44 ;
    END
  END i[315]
  PIN i[316]
    DIRECTION INPUT ;
    USE SIGNAL ;
    PORT
      LAYER M5 ;
        RECT  25.488 19.356 25.512 19.44 ;
    END
  END i[316]
  PIN i[317]
    DIRECTION INPUT ;
    USE SIGNAL ;
    PORT
      LAYER M5 ;
        RECT  25.584 19.356 25.608 19.44 ;
    END
  END i[317]
  PIN i[318]
    DIRECTION INPUT ;
    USE SIGNAL ;
    PORT
      LAYER M5 ;
        RECT  25.632 19.356 25.656 19.44 ;
    END
  END i[318]
  PIN i[319]
    DIRECTION INPUT ;
    USE SIGNAL ;
    PORT
      LAYER M5 ;
        RECT  25.728 19.356 25.752 19.44 ;
    END
  END i[319]
  PIN i[31]
    DIRECTION INPUT ;
    USE SIGNAL ;
    PORT
      LAYER M3 ;
        RECT  4.68 19.402 4.698 19.44 ;
    END
  END i[31]
  PIN i[320]
    DIRECTION INPUT ;
    USE SIGNAL ;
    PORT
      LAYER M3 ;
        RECT  25.776 19.402 25.794 19.44 ;
    END
  END i[320]
  PIN i[321]
    DIRECTION INPUT ;
    USE SIGNAL ;
    PORT
      LAYER M3 ;
        RECT  25.848 19.402 25.866 19.44 ;
    END
  END i[321]
  PIN i[322]
    DIRECTION INPUT ;
    USE SIGNAL ;
    PORT
      LAYER M3 ;
        RECT  25.92 19.402 25.938 19.44 ;
    END
  END i[322]
  PIN i[323]
    DIRECTION INPUT ;
    USE SIGNAL ;
    PORT
      LAYER M3 ;
        RECT  25.992 19.402 26.01 19.44 ;
    END
  END i[323]
  PIN i[324]
    DIRECTION INPUT ;
    USE SIGNAL ;
    PORT
      LAYER M3 ;
        RECT  26.064 19.402 26.082 19.44 ;
    END
  END i[324]
  PIN i[325]
    DIRECTION INPUT ;
    USE SIGNAL ;
    PORT
      LAYER M3 ;
        RECT  26.172 19.402 26.19 19.44 ;
    END
  END i[325]
  PIN i[326]
    DIRECTION INPUT ;
    USE SIGNAL ;
    PORT
      LAYER M3 ;
        RECT  26.244 19.402 26.262 19.44 ;
    END
  END i[326]
  PIN i[327]
    DIRECTION INPUT ;
    USE SIGNAL ;
    PORT
      LAYER M3 ;
        RECT  26.316 19.402 26.334 19.44 ;
    END
  END i[327]
  PIN i[328]
    DIRECTION INPUT ;
    USE SIGNAL ;
    PORT
      LAYER M3 ;
        RECT  26.388 19.402 26.406 19.44 ;
    END
  END i[328]
  PIN i[329]
    DIRECTION INPUT ;
    USE SIGNAL ;
    PORT
      LAYER M3 ;
        RECT  26.46 19.402 26.478 19.44 ;
    END
  END i[329]
  PIN i[32]
    DIRECTION INPUT ;
    USE SIGNAL ;
    PORT
      LAYER M5 ;
        RECT  4.752 19.356 4.776 19.44 ;
    END
  END i[32]
  PIN i[330]
    DIRECTION INPUT ;
    USE SIGNAL ;
    PORT
      LAYER M3 ;
        RECT  26.532 19.402 26.55 19.44 ;
    END
  END i[330]
  PIN i[331]
    DIRECTION INPUT ;
    USE SIGNAL ;
    PORT
      LAYER M3 ;
        RECT  26.604 19.402 26.622 19.44 ;
    END
  END i[331]
  PIN i[332]
    DIRECTION INPUT ;
    USE SIGNAL ;
    PORT
      LAYER M3 ;
        RECT  26.676 19.402 26.694 19.44 ;
    END
  END i[332]
  PIN i[333]
    DIRECTION INPUT ;
    USE SIGNAL ;
    PORT
      LAYER M3 ;
        RECT  26.748 19.402 26.766 19.44 ;
    END
  END i[333]
  PIN i[334]
    DIRECTION INPUT ;
    USE SIGNAL ;
    PORT
      LAYER M3 ;
        RECT  26.82 19.402 26.838 19.44 ;
    END
  END i[334]
  PIN i[335]
    DIRECTION INPUT ;
    USE SIGNAL ;
    PORT
      LAYER M3 ;
        RECT  26.892 19.402 26.91 19.44 ;
    END
  END i[335]
  PIN i[336]
    DIRECTION INPUT ;
    USE SIGNAL ;
    PORT
      LAYER M3 ;
        RECT  26.964 19.402 26.982 19.44 ;
    END
  END i[336]
  PIN i[337]
    DIRECTION INPUT ;
    USE SIGNAL ;
    PORT
      LAYER M3 ;
        RECT  27.036 19.402 27.054 19.44 ;
    END
  END i[337]
  PIN i[338]
    DIRECTION INPUT ;
    USE SIGNAL ;
    PORT
      LAYER M3 ;
        RECT  27.108 19.402 27.126 19.44 ;
    END
  END i[338]
  PIN i[339]
    DIRECTION INPUT ;
    USE SIGNAL ;
    PORT
      LAYER M3 ;
        RECT  27.18 19.402 27.198 19.44 ;
    END
  END i[339]
  PIN i[33]
    DIRECTION INPUT ;
    USE SIGNAL ;
    PORT
      LAYER M5 ;
        RECT  4.848 19.356 4.872 19.44 ;
    END
  END i[33]
  PIN i[340]
    DIRECTION INPUT ;
    USE SIGNAL ;
    PORT
      LAYER M3 ;
        RECT  27.252 19.402 27.27 19.44 ;
    END
  END i[340]
  PIN i[341]
    DIRECTION INPUT ;
    USE SIGNAL ;
    PORT
      LAYER M3 ;
        RECT  27.324 19.402 27.342 19.44 ;
    END
  END i[341]
  PIN i[342]
    DIRECTION INPUT ;
    USE SIGNAL ;
    PORT
      LAYER M3 ;
        RECT  27.396 19.402 27.414 19.44 ;
    END
  END i[342]
  PIN i[343]
    DIRECTION INPUT ;
    USE SIGNAL ;
    PORT
      LAYER M3 ;
        RECT  27.468 19.402 27.486 19.44 ;
    END
  END i[343]
  PIN i[344]
    DIRECTION INPUT ;
    USE SIGNAL ;
    PORT
      LAYER M3 ;
        RECT  27.54 19.402 27.558 19.44 ;
    END
  END i[344]
  PIN i[345]
    DIRECTION INPUT ;
    USE SIGNAL ;
    PORT
      LAYER M3 ;
        RECT  27.612 19.402 27.63 19.44 ;
    END
  END i[345]
  PIN i[346]
    DIRECTION INPUT ;
    USE SIGNAL ;
    PORT
      LAYER M3 ;
        RECT  27.684 19.402 27.702 19.44 ;
    END
  END i[346]
  PIN i[347]
    DIRECTION INPUT ;
    USE SIGNAL ;
    PORT
      LAYER M3 ;
        RECT  27.756 19.402 27.774 19.44 ;
    END
  END i[347]
  PIN i[348]
    DIRECTION INPUT ;
    USE SIGNAL ;
    PORT
      LAYER M3 ;
        RECT  27.828 19.402 27.846 19.44 ;
    END
  END i[348]
  PIN i[349]
    DIRECTION INPUT ;
    USE SIGNAL ;
    PORT
      LAYER M3 ;
        RECT  27.9 19.402 27.918 19.44 ;
    END
  END i[349]
  PIN i[34]
    DIRECTION INPUT ;
    USE SIGNAL ;
    PORT
      LAYER M5 ;
        RECT  4.896 19.356 4.92 19.44 ;
    END
  END i[34]
  PIN i[350]
    DIRECTION INPUT ;
    USE SIGNAL ;
    PORT
      LAYER M3 ;
        RECT  27.972 19.402 27.99 19.44 ;
    END
  END i[350]
  PIN i[351]
    DIRECTION INPUT ;
    USE SIGNAL ;
    PORT
      LAYER M3 ;
        RECT  28.044 19.402 28.062 19.44 ;
    END
  END i[351]
  PIN i[352]
    DIRECTION INPUT ;
    USE SIGNAL ;
    PORT
      LAYER M5 ;
        RECT  28.128 19.356 28.152 19.44 ;
    END
  END i[352]
  PIN i[353]
    DIRECTION INPUT ;
    USE SIGNAL ;
    PORT
      LAYER M5 ;
        RECT  28.176 19.356 28.2 19.44 ;
    END
  END i[353]
  PIN i[354]
    DIRECTION INPUT ;
    USE SIGNAL ;
    PORT
      LAYER M5 ;
        RECT  28.272 19.356 28.296 19.44 ;
    END
  END i[354]
  PIN i[355]
    DIRECTION INPUT ;
    USE SIGNAL ;
    PORT
      LAYER M5 ;
        RECT  28.32 19.356 28.344 19.44 ;
    END
  END i[355]
  PIN i[356]
    DIRECTION INPUT ;
    USE SIGNAL ;
    PORT
      LAYER M5 ;
        RECT  28.416 19.356 28.44 19.44 ;
    END
  END i[356]
  PIN i[357]
    DIRECTION INPUT ;
    USE SIGNAL ;
    PORT
      LAYER M5 ;
        RECT  28.464 19.356 28.488 19.44 ;
    END
  END i[357]
  PIN i[358]
    DIRECTION INPUT ;
    USE SIGNAL ;
    PORT
      LAYER M5 ;
        RECT  28.56 19.356 28.584 19.44 ;
    END
  END i[358]
  PIN i[359]
    DIRECTION INPUT ;
    USE SIGNAL ;
    PORT
      LAYER M5 ;
        RECT  28.656 19.356 28.68 19.44 ;
    END
  END i[359]
  PIN i[35]
    DIRECTION INPUT ;
    USE SIGNAL ;
    PORT
      LAYER M5 ;
        RECT  4.992 19.356 5.016 19.44 ;
    END
  END i[35]
  PIN i[360]
    DIRECTION INPUT ;
    USE SIGNAL ;
    PORT
      LAYER M5 ;
        RECT  28.704 19.356 28.728 19.44 ;
    END
  END i[360]
  PIN i[361]
    DIRECTION INPUT ;
    USE SIGNAL ;
    PORT
      LAYER M5 ;
        RECT  28.8 19.356 28.824 19.44 ;
    END
  END i[361]
  PIN i[362]
    DIRECTION INPUT ;
    USE SIGNAL ;
    PORT
      LAYER M5 ;
        RECT  28.848 19.356 28.872 19.44 ;
    END
  END i[362]
  PIN i[363]
    DIRECTION INPUT ;
    USE SIGNAL ;
    PORT
      LAYER M5 ;
        RECT  28.944 19.356 28.968 19.44 ;
    END
  END i[363]
  PIN i[364]
    DIRECTION INPUT ;
    USE SIGNAL ;
    PORT
      LAYER M5 ;
        RECT  28.992 19.356 29.016 19.44 ;
    END
  END i[364]
  PIN i[365]
    DIRECTION INPUT ;
    USE SIGNAL ;
    PORT
      LAYER M5 ;
        RECT  29.088 19.356 29.112 19.44 ;
    END
  END i[365]
  PIN i[366]
    DIRECTION INPUT ;
    USE SIGNAL ;
    PORT
      LAYER M5 ;
        RECT  29.136 19.356 29.16 19.44 ;
    END
  END i[366]
  PIN i[367]
    DIRECTION INPUT ;
    USE SIGNAL ;
    PORT
      LAYER M5 ;
        RECT  29.232 19.356 29.256 19.44 ;
    END
  END i[367]
  PIN i[368]
    DIRECTION INPUT ;
    USE SIGNAL ;
    PORT
      LAYER M5 ;
        RECT  29.28 19.356 29.304 19.44 ;
    END
  END i[368]
  PIN i[369]
    DIRECTION INPUT ;
    USE SIGNAL ;
    PORT
      LAYER M5 ;
        RECT  29.376 19.356 29.4 19.44 ;
    END
  END i[369]
  PIN i[36]
    DIRECTION INPUT ;
    USE SIGNAL ;
    PORT
      LAYER M5 ;
        RECT  5.04 19.356 5.064 19.44 ;
    END
  END i[36]
  PIN i[370]
    DIRECTION INPUT ;
    USE SIGNAL ;
    PORT
      LAYER M5 ;
        RECT  29.424 19.356 29.448 19.44 ;
    END
  END i[370]
  PIN i[371]
    DIRECTION INPUT ;
    USE SIGNAL ;
    PORT
      LAYER M5 ;
        RECT  29.52 19.356 29.544 19.44 ;
    END
  END i[371]
  PIN i[372]
    DIRECTION INPUT ;
    USE SIGNAL ;
    PORT
      LAYER M5 ;
        RECT  29.568 19.356 29.592 19.44 ;
    END
  END i[372]
  PIN i[373]
    DIRECTION INPUT ;
    USE SIGNAL ;
    PORT
      LAYER M5 ;
        RECT  29.664 19.356 29.688 19.44 ;
    END
  END i[373]
  PIN i[374]
    DIRECTION INPUT ;
    USE SIGNAL ;
    PORT
      LAYER M5 ;
        RECT  29.712 19.356 29.736 19.44 ;
    END
  END i[374]
  PIN i[375]
    DIRECTION INPUT ;
    USE SIGNAL ;
    PORT
      LAYER M5 ;
        RECT  29.808 19.356 29.832 19.44 ;
    END
  END i[375]
  PIN i[376]
    DIRECTION INPUT ;
    USE SIGNAL ;
    PORT
      LAYER M5 ;
        RECT  29.856 19.356 29.88 19.44 ;
    END
  END i[376]
  PIN i[377]
    DIRECTION INPUT ;
    USE SIGNAL ;
    PORT
      LAYER M5 ;
        RECT  29.952 19.356 29.976 19.44 ;
    END
  END i[377]
  PIN i[378]
    DIRECTION INPUT ;
    USE SIGNAL ;
    PORT
      LAYER M5 ;
        RECT  30 19.356 30.024 19.44 ;
    END
  END i[378]
  PIN i[379]
    DIRECTION INPUT ;
    USE SIGNAL ;
    PORT
      LAYER M5 ;
        RECT  30.096 19.356 30.12 19.44 ;
    END
  END i[379]
  PIN i[37]
    DIRECTION INPUT ;
    USE SIGNAL ;
    PORT
      LAYER M5 ;
        RECT  5.136 19.356 5.16 19.44 ;
    END
  END i[37]
  PIN i[380]
    DIRECTION INPUT ;
    USE SIGNAL ;
    PORT
      LAYER M5 ;
        RECT  30.144 19.356 30.168 19.44 ;
    END
  END i[380]
  PIN i[381]
    DIRECTION INPUT ;
    USE SIGNAL ;
    PORT
      LAYER M5 ;
        RECT  30.24 19.356 30.264 19.44 ;
    END
  END i[381]
  PIN i[382]
    DIRECTION INPUT ;
    USE SIGNAL ;
    PORT
      LAYER M5 ;
        RECT  30.336 19.356 30.36 19.44 ;
    END
  END i[382]
  PIN i[383]
    DIRECTION INPUT ;
    USE SIGNAL ;
    PORT
      LAYER M5 ;
        RECT  30.384 19.356 30.408 19.44 ;
    END
  END i[383]
  PIN i[384]
    DIRECTION INPUT ;
    USE SIGNAL ;
    PORT
      LAYER M3 ;
        RECT  30.456 19.402 30.474 19.44 ;
    END
  END i[384]
  PIN i[385]
    DIRECTION INPUT ;
    USE SIGNAL ;
    PORT
      LAYER M3 ;
        RECT  30.528 19.402 30.546 19.44 ;
    END
  END i[385]
  PIN i[386]
    DIRECTION INPUT ;
    USE SIGNAL ;
    PORT
      LAYER M3 ;
        RECT  30.6 19.402 30.618 19.44 ;
    END
  END i[386]
  PIN i[387]
    DIRECTION INPUT ;
    USE SIGNAL ;
    PORT
      LAYER M3 ;
        RECT  30.672 19.402 30.69 19.44 ;
    END
  END i[387]
  PIN i[388]
    DIRECTION INPUT ;
    USE SIGNAL ;
    PORT
      LAYER M3 ;
        RECT  30.744 19.402 30.762 19.44 ;
    END
  END i[388]
  PIN i[389]
    DIRECTION INPUT ;
    USE SIGNAL ;
    PORT
      LAYER M3 ;
        RECT  30.816 19.402 30.834 19.44 ;
    END
  END i[389]
  PIN i[38]
    DIRECTION INPUT ;
    USE SIGNAL ;
    PORT
      LAYER M5 ;
        RECT  5.184 19.356 5.208 19.44 ;
    END
  END i[38]
  PIN i[390]
    DIRECTION INPUT ;
    USE SIGNAL ;
    PORT
      LAYER M3 ;
        RECT  30.888 19.402 30.906 19.44 ;
    END
  END i[390]
  PIN i[391]
    DIRECTION INPUT ;
    USE SIGNAL ;
    PORT
      LAYER M3 ;
        RECT  30.96 19.402 30.978 19.44 ;
    END
  END i[391]
  PIN i[392]
    DIRECTION INPUT ;
    USE SIGNAL ;
    PORT
      LAYER M3 ;
        RECT  31.032 19.402 31.05 19.44 ;
    END
  END i[392]
  PIN i[393]
    DIRECTION INPUT ;
    USE SIGNAL ;
    PORT
      LAYER M3 ;
        RECT  31.104 19.402 31.122 19.44 ;
    END
  END i[393]
  PIN i[394]
    DIRECTION INPUT ;
    USE SIGNAL ;
    PORT
      LAYER M3 ;
        RECT  31.176 19.402 31.194 19.44 ;
    END
  END i[394]
  PIN i[395]
    DIRECTION INPUT ;
    USE SIGNAL ;
    PORT
      LAYER M3 ;
        RECT  31.248 19.402 31.266 19.44 ;
    END
  END i[395]
  PIN i[396]
    DIRECTION INPUT ;
    USE SIGNAL ;
    PORT
      LAYER M3 ;
        RECT  31.32 19.402 31.338 19.44 ;
    END
  END i[396]
  PIN i[397]
    DIRECTION INPUT ;
    USE SIGNAL ;
    PORT
      LAYER M3 ;
        RECT  31.428 19.402 31.446 19.44 ;
    END
  END i[397]
  PIN i[398]
    DIRECTION INPUT ;
    USE SIGNAL ;
    PORT
      LAYER M3 ;
        RECT  31.5 19.402 31.518 19.44 ;
    END
  END i[398]
  PIN i[399]
    DIRECTION INPUT ;
    USE SIGNAL ;
    PORT
      LAYER M3 ;
        RECT  31.572 19.402 31.59 19.44 ;
    END
  END i[399]
  PIN i[39]
    DIRECTION INPUT ;
    USE SIGNAL ;
    PORT
      LAYER M5 ;
        RECT  5.28 19.356 5.304 19.44 ;
    END
  END i[39]
  PIN i[3]
    DIRECTION INPUT ;
    USE SIGNAL ;
    PORT
      LAYER M3 ;
        RECT  2.664 19.402 2.682 19.44 ;
    END
  END i[3]
  PIN i[400]
    DIRECTION INPUT ;
    USE SIGNAL ;
    PORT
      LAYER M3 ;
        RECT  31.644 19.402 31.662 19.44 ;
    END
  END i[400]
  PIN i[401]
    DIRECTION INPUT ;
    USE SIGNAL ;
    PORT
      LAYER M3 ;
        RECT  31.716 19.402 31.734 19.44 ;
    END
  END i[401]
  PIN i[402]
    DIRECTION INPUT ;
    USE SIGNAL ;
    PORT
      LAYER M3 ;
        RECT  31.788 19.402 31.806 19.44 ;
    END
  END i[402]
  PIN i[403]
    DIRECTION INPUT ;
    USE SIGNAL ;
    PORT
      LAYER M3 ;
        RECT  31.86 19.402 31.878 19.44 ;
    END
  END i[403]
  PIN i[404]
    DIRECTION INPUT ;
    USE SIGNAL ;
    PORT
      LAYER M3 ;
        RECT  31.932 19.402 31.95 19.44 ;
    END
  END i[404]
  PIN i[405]
    DIRECTION INPUT ;
    USE SIGNAL ;
    PORT
      LAYER M3 ;
        RECT  32.004 19.402 32.022 19.44 ;
    END
  END i[405]
  PIN i[406]
    DIRECTION INPUT ;
    USE SIGNAL ;
    PORT
      LAYER M3 ;
        RECT  32.076 19.402 32.094 19.44 ;
    END
  END i[406]
  PIN i[407]
    DIRECTION INPUT ;
    USE SIGNAL ;
    PORT
      LAYER M3 ;
        RECT  32.148 19.402 32.166 19.44 ;
    END
  END i[407]
  PIN i[408]
    DIRECTION INPUT ;
    USE SIGNAL ;
    PORT
      LAYER M3 ;
        RECT  32.22 19.402 32.238 19.44 ;
    END
  END i[408]
  PIN i[409]
    DIRECTION INPUT ;
    USE SIGNAL ;
    PORT
      LAYER M3 ;
        RECT  32.292 19.402 32.31 19.44 ;
    END
  END i[409]
  PIN i[40]
    DIRECTION INPUT ;
    USE SIGNAL ;
    PORT
      LAYER M5 ;
        RECT  5.328 19.356 5.352 19.44 ;
    END
  END i[40]
  PIN i[410]
    DIRECTION INPUT ;
    USE SIGNAL ;
    PORT
      LAYER M3 ;
        RECT  32.364 19.402 32.382 19.44 ;
    END
  END i[410]
  PIN i[411]
    DIRECTION INPUT ;
    USE SIGNAL ;
    PORT
      LAYER M3 ;
        RECT  32.436 19.402 32.454 19.44 ;
    END
  END i[411]
  PIN i[412]
    DIRECTION INPUT ;
    USE SIGNAL ;
    PORT
      LAYER M3 ;
        RECT  32.508 19.402 32.526 19.44 ;
    END
  END i[412]
  PIN i[413]
    DIRECTION INPUT ;
    USE SIGNAL ;
    PORT
      LAYER M3 ;
        RECT  32.58 19.402 32.598 19.44 ;
    END
  END i[413]
  PIN i[414]
    DIRECTION INPUT ;
    USE SIGNAL ;
    PORT
      LAYER M3 ;
        RECT  32.652 19.402 32.67 19.44 ;
    END
  END i[414]
  PIN i[415]
    DIRECTION INPUT ;
    USE SIGNAL ;
    PORT
      LAYER M3 ;
        RECT  32.724 19.402 32.742 19.44 ;
    END
  END i[415]
  PIN i[416]
    DIRECTION INPUT ;
    USE SIGNAL ;
    PORT
      LAYER M5 ;
        RECT  32.784 19.356 32.808 19.44 ;
    END
  END i[416]
  PIN i[417]
    DIRECTION INPUT ;
    USE SIGNAL ;
    PORT
      LAYER M5 ;
        RECT  32.88 19.356 32.904 19.44 ;
    END
  END i[417]
  PIN i[418]
    DIRECTION INPUT ;
    USE SIGNAL ;
    PORT
      LAYER M5 ;
        RECT  32.928 19.356 32.952 19.44 ;
    END
  END i[418]
  PIN i[419]
    DIRECTION INPUT ;
    USE SIGNAL ;
    PORT
      LAYER M5 ;
        RECT  33.024 19.356 33.048 19.44 ;
    END
  END i[419]
  PIN i[41]
    DIRECTION INPUT ;
    USE SIGNAL ;
    PORT
      LAYER M5 ;
        RECT  5.424 19.356 5.448 19.44 ;
    END
  END i[41]
  PIN i[420]
    DIRECTION INPUT ;
    USE SIGNAL ;
    PORT
      LAYER M5 ;
        RECT  33.072 19.356 33.096 19.44 ;
    END
  END i[420]
  PIN i[421]
    DIRECTION INPUT ;
    USE SIGNAL ;
    PORT
      LAYER M5 ;
        RECT  33.168 19.356 33.192 19.44 ;
    END
  END i[421]
  PIN i[422]
    DIRECTION INPUT ;
    USE SIGNAL ;
    PORT
      LAYER M5 ;
        RECT  33.216 19.356 33.24 19.44 ;
    END
  END i[422]
  PIN i[423]
    DIRECTION INPUT ;
    USE SIGNAL ;
    PORT
      LAYER M5 ;
        RECT  33.312 19.356 33.336 19.44 ;
    END
  END i[423]
  PIN i[424]
    DIRECTION INPUT ;
    USE SIGNAL ;
    PORT
      LAYER M5 ;
        RECT  33.36 19.356 33.384 19.44 ;
    END
  END i[424]
  PIN i[425]
    DIRECTION INPUT ;
    USE SIGNAL ;
    PORT
      LAYER M5 ;
        RECT  33.456 19.356 33.48 19.44 ;
    END
  END i[425]
  PIN i[426]
    DIRECTION INPUT ;
    USE SIGNAL ;
    PORT
      LAYER M5 ;
        RECT  33.504 19.356 33.528 19.44 ;
    END
  END i[426]
  PIN i[427]
    DIRECTION INPUT ;
    USE SIGNAL ;
    PORT
      LAYER M5 ;
        RECT  33.6 19.356 33.624 19.44 ;
    END
  END i[427]
  PIN i[428]
    DIRECTION INPUT ;
    USE SIGNAL ;
    PORT
      LAYER M5 ;
        RECT  33.648 19.356 33.672 19.44 ;
    END
  END i[428]
  PIN i[429]
    DIRECTION INPUT ;
    USE SIGNAL ;
    PORT
      LAYER M5 ;
        RECT  33.744 19.356 33.768 19.44 ;
    END
  END i[429]
  PIN i[42]
    DIRECTION INPUT ;
    USE SIGNAL ;
    PORT
      LAYER M5 ;
        RECT  5.472 19.356 5.496 19.44 ;
    END
  END i[42]
  PIN i[430]
    DIRECTION INPUT ;
    USE SIGNAL ;
    PORT
      LAYER M5 ;
        RECT  33.84 19.356 33.864 19.44 ;
    END
  END i[430]
  PIN i[431]
    DIRECTION INPUT ;
    USE SIGNAL ;
    PORT
      LAYER M5 ;
        RECT  33.888 19.356 33.912 19.44 ;
    END
  END i[431]
  PIN i[432]
    DIRECTION INPUT ;
    USE SIGNAL ;
    PORT
      LAYER M5 ;
        RECT  33.984 19.356 34.008 19.44 ;
    END
  END i[432]
  PIN i[433]
    DIRECTION INPUT ;
    USE SIGNAL ;
    PORT
      LAYER M5 ;
        RECT  34.032 19.356 34.056 19.44 ;
    END
  END i[433]
  PIN i[434]
    DIRECTION INPUT ;
    USE SIGNAL ;
    PORT
      LAYER M5 ;
        RECT  34.128 19.356 34.152 19.44 ;
    END
  END i[434]
  PIN i[435]
    DIRECTION INPUT ;
    USE SIGNAL ;
    PORT
      LAYER M5 ;
        RECT  34.176 19.356 34.2 19.44 ;
    END
  END i[435]
  PIN i[436]
    DIRECTION INPUT ;
    USE SIGNAL ;
    PORT
      LAYER M5 ;
        RECT  34.272 19.356 34.296 19.44 ;
    END
  END i[436]
  PIN i[437]
    DIRECTION INPUT ;
    USE SIGNAL ;
    PORT
      LAYER M5 ;
        RECT  34.32 19.356 34.344 19.44 ;
    END
  END i[437]
  PIN i[438]
    DIRECTION INPUT ;
    USE SIGNAL ;
    PORT
      LAYER M5 ;
        RECT  34.416 19.356 34.44 19.44 ;
    END
  END i[438]
  PIN i[439]
    DIRECTION INPUT ;
    USE SIGNAL ;
    PORT
      LAYER M5 ;
        RECT  34.464 19.356 34.488 19.44 ;
    END
  END i[439]
  PIN i[43]
    DIRECTION INPUT ;
    USE SIGNAL ;
    PORT
      LAYER M5 ;
        RECT  5.568 19.356 5.592 19.44 ;
    END
  END i[43]
  PIN i[440]
    DIRECTION INPUT ;
    USE SIGNAL ;
    PORT
      LAYER M5 ;
        RECT  34.56 19.356 34.584 19.44 ;
    END
  END i[440]
  PIN i[441]
    DIRECTION INPUT ;
    USE SIGNAL ;
    PORT
      LAYER M5 ;
        RECT  34.608 19.356 34.632 19.44 ;
    END
  END i[441]
  PIN i[442]
    DIRECTION INPUT ;
    USE SIGNAL ;
    PORT
      LAYER M5 ;
        RECT  34.704 19.356 34.728 19.44 ;
    END
  END i[442]
  PIN i[443]
    DIRECTION INPUT ;
    USE SIGNAL ;
    PORT
      LAYER M5 ;
        RECT  34.752 19.356 34.776 19.44 ;
    END
  END i[443]
  PIN i[444]
    DIRECTION INPUT ;
    USE SIGNAL ;
    PORT
      LAYER M5 ;
        RECT  34.848 19.356 34.872 19.44 ;
    END
  END i[444]
  PIN i[445]
    DIRECTION INPUT ;
    USE SIGNAL ;
    PORT
      LAYER M5 ;
        RECT  34.896 19.356 34.92 19.44 ;
    END
  END i[445]
  PIN i[446]
    DIRECTION INPUT ;
    USE SIGNAL ;
    PORT
      LAYER M5 ;
        RECT  34.992 19.356 35.016 19.44 ;
    END
  END i[446]
  PIN i[447]
    DIRECTION INPUT ;
    USE SIGNAL ;
    PORT
      LAYER M5 ;
        RECT  35.04 19.356 35.064 19.44 ;
    END
  END i[447]
  PIN i[448]
    DIRECTION INPUT ;
    USE SIGNAL ;
    PORT
      LAYER M3 ;
        RECT  35.136 19.402 35.154 19.44 ;
    END
  END i[448]
  PIN i[449]
    DIRECTION INPUT ;
    USE SIGNAL ;
    PORT
      LAYER M3 ;
        RECT  35.208 19.402 35.226 19.44 ;
    END
  END i[449]
  PIN i[44]
    DIRECTION INPUT ;
    USE SIGNAL ;
    PORT
      LAYER M5 ;
        RECT  5.616 19.356 5.64 19.44 ;
    END
  END i[44]
  PIN i[450]
    DIRECTION INPUT ;
    USE SIGNAL ;
    PORT
      LAYER M3 ;
        RECT  35.28 19.402 35.298 19.44 ;
    END
  END i[450]
  PIN i[451]
    DIRECTION INPUT ;
    USE SIGNAL ;
    PORT
      LAYER M3 ;
        RECT  35.352 19.402 35.37 19.44 ;
    END
  END i[451]
  PIN i[452]
    DIRECTION INPUT ;
    USE SIGNAL ;
    PORT
      LAYER M3 ;
        RECT  35.424 19.402 35.442 19.44 ;
    END
  END i[452]
  PIN i[453]
    DIRECTION INPUT ;
    USE SIGNAL ;
    PORT
      LAYER M3 ;
        RECT  35.496 19.402 35.514 19.44 ;
    END
  END i[453]
  PIN i[454]
    DIRECTION INPUT ;
    USE SIGNAL ;
    PORT
      LAYER M3 ;
        RECT  35.568 19.402 35.586 19.44 ;
    END
  END i[454]
  PIN i[455]
    DIRECTION INPUT ;
    USE SIGNAL ;
    PORT
      LAYER M3 ;
        RECT  35.64 19.402 35.658 19.44 ;
    END
  END i[455]
  PIN i[456]
    DIRECTION INPUT ;
    USE SIGNAL ;
    PORT
      LAYER M3 ;
        RECT  35.712 19.402 35.73 19.44 ;
    END
  END i[456]
  PIN i[457]
    DIRECTION INPUT ;
    USE SIGNAL ;
    PORT
      LAYER M3 ;
        RECT  35.784 19.402 35.802 19.44 ;
    END
  END i[457]
  PIN i[458]
    DIRECTION INPUT ;
    USE SIGNAL ;
    PORT
      LAYER M3 ;
        RECT  35.856 19.402 35.874 19.44 ;
    END
  END i[458]
  PIN i[459]
    DIRECTION INPUT ;
    USE SIGNAL ;
    PORT
      LAYER M3 ;
        RECT  35.928 19.402 35.946 19.44 ;
    END
  END i[459]
  PIN i[45]
    DIRECTION INPUT ;
    USE SIGNAL ;
    PORT
      LAYER M5 ;
        RECT  5.712 19.356 5.736 19.44 ;
    END
  END i[45]
  PIN i[460]
    DIRECTION INPUT ;
    USE SIGNAL ;
    PORT
      LAYER M3 ;
        RECT  36 19.402 36.018 19.44 ;
    END
  END i[460]
  PIN i[461]
    DIRECTION INPUT ;
    USE SIGNAL ;
    PORT
      LAYER M3 ;
        RECT  36.072 19.402 36.09 19.44 ;
    END
  END i[461]
  PIN i[462]
    DIRECTION INPUT ;
    USE SIGNAL ;
    PORT
      LAYER M3 ;
        RECT  36.144 19.402 36.162 19.44 ;
    END
  END i[462]
  PIN i[463]
    DIRECTION INPUT ;
    USE SIGNAL ;
    PORT
      LAYER M3 ;
        RECT  36.216 19.402 36.234 19.44 ;
    END
  END i[463]
  PIN i[464]
    DIRECTION INPUT ;
    USE SIGNAL ;
    PORT
      LAYER M3 ;
        RECT  36.288 19.402 36.306 19.44 ;
    END
  END i[464]
  PIN i[465]
    DIRECTION INPUT ;
    USE SIGNAL ;
    PORT
      LAYER M3 ;
        RECT  36.36 19.402 36.378 19.44 ;
    END
  END i[465]
  PIN i[466]
    DIRECTION INPUT ;
    USE SIGNAL ;
    PORT
      LAYER M3 ;
        RECT  36.432 19.402 36.45 19.44 ;
    END
  END i[466]
  PIN i[467]
    DIRECTION INPUT ;
    USE SIGNAL ;
    PORT
      LAYER M3 ;
        RECT  36.504 19.402 36.522 19.44 ;
    END
  END i[467]
  PIN i[468]
    DIRECTION INPUT ;
    USE SIGNAL ;
    PORT
      LAYER M3 ;
        RECT  36.576 19.402 36.594 19.44 ;
    END
  END i[468]
  PIN i[469]
    DIRECTION INPUT ;
    USE SIGNAL ;
    PORT
      LAYER M3 ;
        RECT  36.684 19.402 36.702 19.44 ;
    END
  END i[469]
  PIN i[46]
    DIRECTION INPUT ;
    USE SIGNAL ;
    PORT
      LAYER M5 ;
        RECT  5.76 19.356 5.784 19.44 ;
    END
  END i[46]
  PIN i[470]
    DIRECTION INPUT ;
    USE SIGNAL ;
    PORT
      LAYER M3 ;
        RECT  36.756 19.402 36.774 19.44 ;
    END
  END i[470]
  PIN i[471]
    DIRECTION INPUT ;
    USE SIGNAL ;
    PORT
      LAYER M3 ;
        RECT  36.828 19.402 36.846 19.44 ;
    END
  END i[471]
  PIN i[472]
    DIRECTION INPUT ;
    USE SIGNAL ;
    PORT
      LAYER M3 ;
        RECT  36.9 19.402 36.918 19.44 ;
    END
  END i[472]
  PIN i[473]
    DIRECTION INPUT ;
    USE SIGNAL ;
    PORT
      LAYER M3 ;
        RECT  36.972 19.402 36.99 19.44 ;
    END
  END i[473]
  PIN i[474]
    DIRECTION INPUT ;
    USE SIGNAL ;
    PORT
      LAYER M3 ;
        RECT  37.044 19.402 37.062 19.44 ;
    END
  END i[474]
  PIN i[475]
    DIRECTION INPUT ;
    USE SIGNAL ;
    PORT
      LAYER M3 ;
        RECT  37.116 19.402 37.134 19.44 ;
    END
  END i[475]
  PIN i[476]
    DIRECTION INPUT ;
    USE SIGNAL ;
    PORT
      LAYER M3 ;
        RECT  37.188 19.402 37.206 19.44 ;
    END
  END i[476]
  PIN i[477]
    DIRECTION INPUT ;
    USE SIGNAL ;
    PORT
      LAYER M3 ;
        RECT  37.26 19.402 37.278 19.44 ;
    END
  END i[477]
  PIN i[478]
    DIRECTION INPUT ;
    USE SIGNAL ;
    PORT
      LAYER M3 ;
        RECT  37.332 19.402 37.35 19.44 ;
    END
  END i[478]
  PIN i[479]
    DIRECTION INPUT ;
    USE SIGNAL ;
    PORT
      LAYER M3 ;
        RECT  37.404 19.402 37.422 19.44 ;
    END
  END i[479]
  PIN i[47]
    DIRECTION INPUT ;
    USE SIGNAL ;
    PORT
      LAYER M5 ;
        RECT  5.856 19.356 5.88 19.44 ;
    END
  END i[47]
  PIN i[480]
    DIRECTION INPUT ;
    USE SIGNAL ;
    PORT
      LAYER M5 ;
        RECT  37.488 19.356 37.512 19.44 ;
    END
  END i[480]
  PIN i[481]
    DIRECTION INPUT ;
    USE SIGNAL ;
    PORT
      LAYER M5 ;
        RECT  37.536 19.356 37.56 19.44 ;
    END
  END i[481]
  PIN i[482]
    DIRECTION INPUT ;
    USE SIGNAL ;
    PORT
      LAYER M5 ;
        RECT  37.632 19.356 37.656 19.44 ;
    END
  END i[482]
  PIN i[483]
    DIRECTION INPUT ;
    USE SIGNAL ;
    PORT
      LAYER M5 ;
        RECT  37.68 19.356 37.704 19.44 ;
    END
  END i[483]
  PIN i[484]
    DIRECTION INPUT ;
    USE SIGNAL ;
    PORT
      LAYER M5 ;
        RECT  37.776 19.356 37.8 19.44 ;
    END
  END i[484]
  PIN i[485]
    DIRECTION INPUT ;
    USE SIGNAL ;
    PORT
      LAYER M5 ;
        RECT  37.824 19.356 37.848 19.44 ;
    END
  END i[485]
  PIN i[486]
    DIRECTION INPUT ;
    USE SIGNAL ;
    PORT
      LAYER M5 ;
        RECT  37.92 19.356 37.944 19.44 ;
    END
  END i[486]
  PIN i[487]
    DIRECTION INPUT ;
    USE SIGNAL ;
    PORT
      LAYER M5 ;
        RECT  37.968 19.356 37.992 19.44 ;
    END
  END i[487]
  PIN i[488]
    DIRECTION INPUT ;
    USE SIGNAL ;
    PORT
      LAYER M5 ;
        RECT  38.064 19.356 38.088 19.44 ;
    END
  END i[488]
  PIN i[489]
    DIRECTION INPUT ;
    USE SIGNAL ;
    PORT
      LAYER M5 ;
        RECT  38.112 19.356 38.136 19.44 ;
    END
  END i[489]
  PIN i[48]
    DIRECTION INPUT ;
    USE SIGNAL ;
    PORT
      LAYER M5 ;
        RECT  5.952 19.356 5.976 19.44 ;
    END
  END i[48]
  PIN i[490]
    DIRECTION INPUT ;
    USE SIGNAL ;
    PORT
      LAYER M5 ;
        RECT  38.208 19.356 38.232 19.44 ;
    END
  END i[490]
  PIN i[491]
    DIRECTION INPUT ;
    USE SIGNAL ;
    PORT
      LAYER M5 ;
        RECT  38.256 19.356 38.28 19.44 ;
    END
  END i[491]
  PIN i[492]
    DIRECTION INPUT ;
    USE SIGNAL ;
    PORT
      LAYER M5 ;
        RECT  38.352 19.356 38.376 19.44 ;
    END
  END i[492]
  PIN i[493]
    DIRECTION INPUT ;
    USE SIGNAL ;
    PORT
      LAYER M5 ;
        RECT  38.4 19.356 38.424 19.44 ;
    END
  END i[493]
  PIN i[494]
    DIRECTION INPUT ;
    USE SIGNAL ;
    PORT
      LAYER M5 ;
        RECT  38.496 19.356 38.52 19.44 ;
    END
  END i[494]
  PIN i[495]
    DIRECTION INPUT ;
    USE SIGNAL ;
    PORT
      LAYER M5 ;
        RECT  38.544 19.356 38.568 19.44 ;
    END
  END i[495]
  PIN i[496]
    DIRECTION INPUT ;
    USE SIGNAL ;
    PORT
      LAYER M5 ;
        RECT  38.64 19.356 38.664 19.44 ;
    END
  END i[496]
  PIN i[497]
    DIRECTION INPUT ;
    USE SIGNAL ;
    PORT
      LAYER M5 ;
        RECT  38.688 19.356 38.712 19.44 ;
    END
  END i[497]
  PIN i[498]
    DIRECTION INPUT ;
    USE SIGNAL ;
    PORT
      LAYER M5 ;
        RECT  38.784 19.356 38.808 19.44 ;
    END
  END i[498]
  PIN i[499]
    DIRECTION INPUT ;
    USE SIGNAL ;
    PORT
      LAYER M5 ;
        RECT  38.832 19.356 38.856 19.44 ;
    END
  END i[499]
  PIN i[49]
    DIRECTION INPUT ;
    USE SIGNAL ;
    PORT
      LAYER M5 ;
        RECT  6 19.356 6.024 19.44 ;
    END
  END i[49]
  PIN i[4]
    DIRECTION INPUT ;
    USE SIGNAL ;
    PORT
      LAYER M3 ;
        RECT  2.736 19.402 2.754 19.44 ;
    END
  END i[4]
  PIN i[500]
    DIRECTION INPUT ;
    USE SIGNAL ;
    PORT
      LAYER M5 ;
        RECT  38.928 19.356 38.952 19.44 ;
    END
  END i[500]
  PIN i[501]
    DIRECTION INPUT ;
    USE SIGNAL ;
    PORT
      LAYER M5 ;
        RECT  38.976 19.356 39 19.44 ;
    END
  END i[501]
  PIN i[502]
    DIRECTION INPUT ;
    USE SIGNAL ;
    PORT
      LAYER M5 ;
        RECT  39.072 19.356 39.096 19.44 ;
    END
  END i[502]
  PIN i[503]
    DIRECTION INPUT ;
    USE SIGNAL ;
    PORT
      LAYER M5 ;
        RECT  39.168 19.356 39.192 19.44 ;
    END
  END i[503]
  PIN i[504]
    DIRECTION INPUT ;
    USE SIGNAL ;
    PORT
      LAYER M5 ;
        RECT  39.216 19.356 39.24 19.44 ;
    END
  END i[504]
  PIN i[505]
    DIRECTION INPUT ;
    USE SIGNAL ;
    PORT
      LAYER M5 ;
        RECT  39.312 19.356 39.336 19.44 ;
    END
  END i[505]
  PIN i[506]
    DIRECTION INPUT ;
    USE SIGNAL ;
    PORT
      LAYER M5 ;
        RECT  39.36 19.356 39.384 19.44 ;
    END
  END i[506]
  PIN i[507]
    DIRECTION INPUT ;
    USE SIGNAL ;
    PORT
      LAYER M5 ;
        RECT  39.456 19.356 39.48 19.44 ;
    END
  END i[507]
  PIN i[508]
    DIRECTION INPUT ;
    USE SIGNAL ;
    PORT
      LAYER M5 ;
        RECT  39.504 19.356 39.528 19.44 ;
    END
  END i[508]
  PIN i[509]
    DIRECTION INPUT ;
    USE SIGNAL ;
    PORT
      LAYER M5 ;
        RECT  39.6 19.356 39.624 19.44 ;
    END
  END i[509]
  PIN i[50]
    DIRECTION INPUT ;
    USE SIGNAL ;
    PORT
      LAYER M5 ;
        RECT  6.096 19.356 6.12 19.44 ;
    END
  END i[50]
  PIN i[510]
    DIRECTION INPUT ;
    USE SIGNAL ;
    PORT
      LAYER M5 ;
        RECT  39.648 19.356 39.672 19.44 ;
    END
  END i[510]
  PIN i[511]
    DIRECTION INPUT ;
    USE SIGNAL ;
    PORT
      LAYER M5 ;
        RECT  39.744 19.356 39.768 19.44 ;
    END
  END i[511]
  PIN i[512]
    DIRECTION INPUT ;
    USE SIGNAL ;
    PORT
      LAYER M3 ;
        RECT  39.816 19.402 39.834 19.44 ;
    END
  END i[512]
  PIN i[513]
    DIRECTION INPUT ;
    USE SIGNAL ;
    PORT
      LAYER M3 ;
        RECT  39.888 19.402 39.906 19.44 ;
    END
  END i[513]
  PIN i[514]
    DIRECTION INPUT ;
    USE SIGNAL ;
    PORT
      LAYER M3 ;
        RECT  39.96 19.402 39.978 19.44 ;
    END
  END i[514]
  PIN i[515]
    DIRECTION INPUT ;
    USE SIGNAL ;
    PORT
      LAYER M3 ;
        RECT  40.032 19.402 40.05 19.44 ;
    END
  END i[515]
  PIN i[516]
    DIRECTION INPUT ;
    USE SIGNAL ;
    PORT
      LAYER M3 ;
        RECT  40.104 19.402 40.122 19.44 ;
    END
  END i[516]
  PIN i[517]
    DIRECTION INPUT ;
    USE SIGNAL ;
    PORT
      LAYER M3 ;
        RECT  40.176 19.402 40.194 19.44 ;
    END
  END i[517]
  PIN i[518]
    DIRECTION INPUT ;
    USE SIGNAL ;
    PORT
      LAYER M3 ;
        RECT  40.248 19.402 40.266 19.44 ;
    END
  END i[518]
  PIN i[519]
    DIRECTION INPUT ;
    USE SIGNAL ;
    PORT
      LAYER M3 ;
        RECT  40.32 19.402 40.338 19.44 ;
    END
  END i[519]
  PIN i[51]
    DIRECTION INPUT ;
    USE SIGNAL ;
    PORT
      LAYER M5 ;
        RECT  6.144 19.356 6.168 19.44 ;
    END
  END i[51]
  PIN i[520]
    DIRECTION INPUT ;
    USE SIGNAL ;
    PORT
      LAYER M3 ;
        RECT  40.392 19.402 40.41 19.44 ;
    END
  END i[520]
  PIN i[521]
    DIRECTION INPUT ;
    USE SIGNAL ;
    PORT
      LAYER M3 ;
        RECT  40.464 19.402 40.482 19.44 ;
    END
  END i[521]
  PIN i[522]
    DIRECTION INPUT ;
    USE SIGNAL ;
    PORT
      LAYER M3 ;
        RECT  40.536 19.402 40.554 19.44 ;
    END
  END i[522]
  PIN i[523]
    DIRECTION INPUT ;
    USE SIGNAL ;
    PORT
      LAYER M3 ;
        RECT  40.608 19.402 40.626 19.44 ;
    END
  END i[523]
  PIN i[524]
    DIRECTION INPUT ;
    USE SIGNAL ;
    PORT
      LAYER M3 ;
        RECT  40.68 19.402 40.698 19.44 ;
    END
  END i[524]
  PIN i[525]
    DIRECTION INPUT ;
    USE SIGNAL ;
    PORT
      LAYER M3 ;
        RECT  40.752 19.402 40.77 19.44 ;
    END
  END i[525]
  PIN i[52]
    DIRECTION INPUT ;
    USE SIGNAL ;
    PORT
      LAYER M5 ;
        RECT  6.24 19.356 6.264 19.44 ;
    END
  END i[52]
  PIN i[53]
    DIRECTION INPUT ;
    USE SIGNAL ;
    PORT
      LAYER M5 ;
        RECT  6.288 19.356 6.312 19.44 ;
    END
  END i[53]
  PIN i[54]
    DIRECTION INPUT ;
    USE SIGNAL ;
    PORT
      LAYER M5 ;
        RECT  6.384 19.356 6.408 19.44 ;
    END
  END i[54]
  PIN i[55]
    DIRECTION INPUT ;
    USE SIGNAL ;
    PORT
      LAYER M5 ;
        RECT  6.432 19.356 6.456 19.44 ;
    END
  END i[55]
  PIN i[56]
    DIRECTION INPUT ;
    USE SIGNAL ;
    PORT
      LAYER M5 ;
        RECT  6.528 19.356 6.552 19.44 ;
    END
  END i[56]
  PIN i[57]
    DIRECTION INPUT ;
    USE SIGNAL ;
    PORT
      LAYER M5 ;
        RECT  6.576 19.356 6.6 19.44 ;
    END
  END i[57]
  PIN i[58]
    DIRECTION INPUT ;
    USE SIGNAL ;
    PORT
      LAYER M5 ;
        RECT  6.672 19.356 6.696 19.44 ;
    END
  END i[58]
  PIN i[59]
    DIRECTION INPUT ;
    USE SIGNAL ;
    PORT
      LAYER M5 ;
        RECT  6.72 19.356 6.744 19.44 ;
    END
  END i[59]
  PIN i[5]
    DIRECTION INPUT ;
    USE SIGNAL ;
    PORT
      LAYER M3 ;
        RECT  2.808 19.402 2.826 19.44 ;
    END
  END i[5]
  PIN i[60]
    DIRECTION INPUT ;
    USE SIGNAL ;
    PORT
      LAYER M5 ;
        RECT  6.816 19.356 6.84 19.44 ;
    END
  END i[60]
  PIN i[61]
    DIRECTION INPUT ;
    USE SIGNAL ;
    PORT
      LAYER M5 ;
        RECT  6.864 19.356 6.888 19.44 ;
    END
  END i[61]
  PIN i[62]
    DIRECTION INPUT ;
    USE SIGNAL ;
    PORT
      LAYER M5 ;
        RECT  6.96 19.356 6.984 19.44 ;
    END
  END i[62]
  PIN i[63]
    DIRECTION INPUT ;
    USE SIGNAL ;
    PORT
      LAYER M5 ;
        RECT  7.008 19.356 7.032 19.44 ;
    END
  END i[63]
  PIN i[64]
    DIRECTION INPUT ;
    USE SIGNAL ;
    PORT
      LAYER M3 ;
        RECT  7.092 19.402 7.11 19.44 ;
    END
  END i[64]
  PIN i[65]
    DIRECTION INPUT ;
    USE SIGNAL ;
    PORT
      LAYER M3 ;
        RECT  7.164 19.402 7.182 19.44 ;
    END
  END i[65]
  PIN i[66]
    DIRECTION INPUT ;
    USE SIGNAL ;
    PORT
      LAYER M3 ;
        RECT  7.236 19.402 7.254 19.44 ;
    END
  END i[66]
  PIN i[67]
    DIRECTION INPUT ;
    USE SIGNAL ;
    PORT
      LAYER M3 ;
        RECT  7.308 19.402 7.326 19.44 ;
    END
  END i[67]
  PIN i[68]
    DIRECTION INPUT ;
    USE SIGNAL ;
    PORT
      LAYER M3 ;
        RECT  7.38 19.402 7.398 19.44 ;
    END
  END i[68]
  PIN i[69]
    DIRECTION INPUT ;
    USE SIGNAL ;
    PORT
      LAYER M3 ;
        RECT  7.452 19.402 7.47 19.44 ;
    END
  END i[69]
  PIN i[6]
    DIRECTION INPUT ;
    USE SIGNAL ;
    PORT
      LAYER M3 ;
        RECT  2.88 19.402 2.898 19.44 ;
    END
  END i[6]
  PIN i[70]
    DIRECTION INPUT ;
    USE SIGNAL ;
    PORT
      LAYER M3 ;
        RECT  7.524 19.402 7.542 19.44 ;
    END
  END i[70]
  PIN i[71]
    DIRECTION INPUT ;
    USE SIGNAL ;
    PORT
      LAYER M3 ;
        RECT  7.596 19.402 7.614 19.44 ;
    END
  END i[71]
  PIN i[72]
    DIRECTION INPUT ;
    USE SIGNAL ;
    PORT
      LAYER M3 ;
        RECT  7.668 19.402 7.686 19.44 ;
    END
  END i[72]
  PIN i[73]
    DIRECTION INPUT ;
    USE SIGNAL ;
    PORT
      LAYER M3 ;
        RECT  7.74 19.402 7.758 19.44 ;
    END
  END i[73]
  PIN i[74]
    DIRECTION INPUT ;
    USE SIGNAL ;
    PORT
      LAYER M3 ;
        RECT  7.848 19.402 7.866 19.44 ;
    END
  END i[74]
  PIN i[75]
    DIRECTION INPUT ;
    USE SIGNAL ;
    PORT
      LAYER M3 ;
        RECT  7.92 19.402 7.938 19.44 ;
    END
  END i[75]
  PIN i[76]
    DIRECTION INPUT ;
    USE SIGNAL ;
    PORT
      LAYER M3 ;
        RECT  7.992 19.402 8.01 19.44 ;
    END
  END i[76]
  PIN i[77]
    DIRECTION INPUT ;
    USE SIGNAL ;
    PORT
      LAYER M3 ;
        RECT  8.064 19.402 8.082 19.44 ;
    END
  END i[77]
  PIN i[78]
    DIRECTION INPUT ;
    USE SIGNAL ;
    PORT
      LAYER M3 ;
        RECT  8.136 19.402 8.154 19.44 ;
    END
  END i[78]
  PIN i[79]
    DIRECTION INPUT ;
    USE SIGNAL ;
    PORT
      LAYER M3 ;
        RECT  8.208 19.402 8.226 19.44 ;
    END
  END i[79]
  PIN i[7]
    DIRECTION INPUT ;
    USE SIGNAL ;
    PORT
      LAYER M3 ;
        RECT  2.952 19.402 2.97 19.44 ;
    END
  END i[7]
  PIN i[80]
    DIRECTION INPUT ;
    USE SIGNAL ;
    PORT
      LAYER M3 ;
        RECT  8.28 19.402 8.298 19.44 ;
    END
  END i[80]
  PIN i[81]
    DIRECTION INPUT ;
    USE SIGNAL ;
    PORT
      LAYER M3 ;
        RECT  8.352 19.402 8.37 19.44 ;
    END
  END i[81]
  PIN i[82]
    DIRECTION INPUT ;
    USE SIGNAL ;
    PORT
      LAYER M3 ;
        RECT  8.424 19.402 8.442 19.44 ;
    END
  END i[82]
  PIN i[83]
    DIRECTION INPUT ;
    USE SIGNAL ;
    PORT
      LAYER M3 ;
        RECT  8.496 19.402 8.514 19.44 ;
    END
  END i[83]
  PIN i[84]
    DIRECTION INPUT ;
    USE SIGNAL ;
    PORT
      LAYER M3 ;
        RECT  8.568 19.402 8.586 19.44 ;
    END
  END i[84]
  PIN i[85]
    DIRECTION INPUT ;
    USE SIGNAL ;
    PORT
      LAYER M3 ;
        RECT  8.64 19.402 8.658 19.44 ;
    END
  END i[85]
  PIN i[86]
    DIRECTION INPUT ;
    USE SIGNAL ;
    PORT
      LAYER M3 ;
        RECT  8.712 19.402 8.73 19.44 ;
    END
  END i[86]
  PIN i[87]
    DIRECTION INPUT ;
    USE SIGNAL ;
    PORT
      LAYER M3 ;
        RECT  8.784 19.402 8.802 19.44 ;
    END
  END i[87]
  PIN i[88]
    DIRECTION INPUT ;
    USE SIGNAL ;
    PORT
      LAYER M3 ;
        RECT  8.856 19.402 8.874 19.44 ;
    END
  END i[88]
  PIN i[89]
    DIRECTION INPUT ;
    USE SIGNAL ;
    PORT
      LAYER M3 ;
        RECT  8.928 19.402 8.946 19.44 ;
    END
  END i[89]
  PIN i[8]
    DIRECTION INPUT ;
    USE SIGNAL ;
    PORT
      LAYER M3 ;
        RECT  3.024 19.402 3.042 19.44 ;
    END
  END i[8]
  PIN i[90]
    DIRECTION INPUT ;
    USE SIGNAL ;
    PORT
      LAYER M3 ;
        RECT  9 19.402 9.018 19.44 ;
    END
  END i[90]
  PIN i[91]
    DIRECTION INPUT ;
    USE SIGNAL ;
    PORT
      LAYER M3 ;
        RECT  9.072 19.402 9.09 19.44 ;
    END
  END i[91]
  PIN i[92]
    DIRECTION INPUT ;
    USE SIGNAL ;
    PORT
      LAYER M3 ;
        RECT  9.144 19.402 9.162 19.44 ;
    END
  END i[92]
  PIN i[93]
    DIRECTION INPUT ;
    USE SIGNAL ;
    PORT
      LAYER M3 ;
        RECT  9.216 19.402 9.234 19.44 ;
    END
  END i[93]
  PIN i[94]
    DIRECTION INPUT ;
    USE SIGNAL ;
    PORT
      LAYER M3 ;
        RECT  9.288 19.402 9.306 19.44 ;
    END
  END i[94]
  PIN i[95]
    DIRECTION INPUT ;
    USE SIGNAL ;
    PORT
      LAYER M3 ;
        RECT  9.36 19.402 9.378 19.44 ;
    END
  END i[95]
  PIN i[96]
    DIRECTION INPUT ;
    USE SIGNAL ;
    PORT
      LAYER M5 ;
        RECT  9.456 19.356 9.48 19.44 ;
    END
  END i[96]
  PIN i[97]
    DIRECTION INPUT ;
    USE SIGNAL ;
    PORT
      LAYER M5 ;
        RECT  9.504 19.356 9.528 19.44 ;
    END
  END i[97]
  PIN i[98]
    DIRECTION INPUT ;
    USE SIGNAL ;
    PORT
      LAYER M5 ;
        RECT  9.6 19.356 9.624 19.44 ;
    END
  END i[98]
  PIN i[99]
    DIRECTION INPUT ;
    USE SIGNAL ;
    PORT
      LAYER M5 ;
        RECT  9.648 19.356 9.672 19.44 ;
    END
  END i[99]
  PIN i[9]
    DIRECTION INPUT ;
    USE SIGNAL ;
    PORT
      LAYER M3 ;
        RECT  3.096 19.402 3.114 19.44 ;
    END
  END i[9]
  PIN o[0]
    DIRECTION OUTPUT ;
    USE SIGNAL ;
    PORT
      LAYER M3 ;
        RECT  2.412 0 2.43 0.038 ;
    END
  END o[0]
  PIN o[100]
    DIRECTION OUTPUT ;
    USE SIGNAL ;
    PORT
      LAYER M5 ;
        RECT  9.744 0 9.768 0.084 ;
    END
  END o[100]
  PIN o[101]
    DIRECTION OUTPUT ;
    USE SIGNAL ;
    PORT
      LAYER M5 ;
        RECT  9.792 0 9.816 0.084 ;
    END
  END o[101]
  PIN o[102]
    DIRECTION OUTPUT ;
    USE SIGNAL ;
    PORT
      LAYER M5 ;
        RECT  9.888 0 9.912 0.084 ;
    END
  END o[102]
  PIN o[103]
    DIRECTION OUTPUT ;
    USE SIGNAL ;
    PORT
      LAYER M5 ;
        RECT  9.936 0 9.96 0.084 ;
    END
  END o[103]
  PIN o[104]
    DIRECTION OUTPUT ;
    USE SIGNAL ;
    PORT
      LAYER M5 ;
        RECT  10.032 0 10.056 0.084 ;
    END
  END o[104]
  PIN o[105]
    DIRECTION OUTPUT ;
    USE SIGNAL ;
    PORT
      LAYER M5 ;
        RECT  10.08 0 10.104 0.084 ;
    END
  END o[105]
  PIN o[106]
    DIRECTION OUTPUT ;
    USE SIGNAL ;
    PORT
      LAYER M5 ;
        RECT  10.176 0 10.2 0.084 ;
    END
  END o[106]
  PIN o[107]
    DIRECTION OUTPUT ;
    USE SIGNAL ;
    PORT
      LAYER M5 ;
        RECT  10.224 0 10.248 0.084 ;
    END
  END o[107]
  PIN o[108]
    DIRECTION OUTPUT ;
    USE SIGNAL ;
    PORT
      LAYER M5 ;
        RECT  10.32 0 10.344 0.084 ;
    END
  END o[108]
  PIN o[109]
    DIRECTION OUTPUT ;
    USE SIGNAL ;
    PORT
      LAYER M5 ;
        RECT  10.368 0 10.392 0.084 ;
    END
  END o[109]
  PIN o[10]
    DIRECTION OUTPUT ;
    USE SIGNAL ;
    PORT
      LAYER M3 ;
        RECT  3.168 0 3.186 0.038 ;
    END
  END o[10]
  PIN o[110]
    DIRECTION OUTPUT ;
    USE SIGNAL ;
    PORT
      LAYER M5 ;
        RECT  10.464 0 10.488 0.084 ;
    END
  END o[110]
  PIN o[111]
    DIRECTION OUTPUT ;
    USE SIGNAL ;
    PORT
      LAYER M5 ;
        RECT  10.512 0 10.536 0.084 ;
    END
  END o[111]
  PIN o[112]
    DIRECTION OUTPUT ;
    USE SIGNAL ;
    PORT
      LAYER M5 ;
        RECT  10.608 0 10.632 0.084 ;
    END
  END o[112]
  PIN o[113]
    DIRECTION OUTPUT ;
    USE SIGNAL ;
    PORT
      LAYER M5 ;
        RECT  10.656 0 10.68 0.084 ;
    END
  END o[113]
  PIN o[114]
    DIRECTION OUTPUT ;
    USE SIGNAL ;
    PORT
      LAYER M5 ;
        RECT  10.752 0 10.776 0.084 ;
    END
  END o[114]
  PIN o[115]
    DIRECTION OUTPUT ;
    USE SIGNAL ;
    PORT
      LAYER M5 ;
        RECT  10.8 0 10.824 0.084 ;
    END
  END o[115]
  PIN o[116]
    DIRECTION OUTPUT ;
    USE SIGNAL ;
    PORT
      LAYER M5 ;
        RECT  10.896 0 10.92 0.084 ;
    END
  END o[116]
  PIN o[117]
    DIRECTION OUTPUT ;
    USE SIGNAL ;
    PORT
      LAYER M5 ;
        RECT  10.944 0 10.968 0.084 ;
    END
  END o[117]
  PIN o[118]
    DIRECTION OUTPUT ;
    USE SIGNAL ;
    PORT
      LAYER M5 ;
        RECT  11.04 0 11.064 0.084 ;
    END
  END o[118]
  PIN o[119]
    DIRECTION OUTPUT ;
    USE SIGNAL ;
    PORT
      LAYER M5 ;
        RECT  11.136 0 11.16 0.084 ;
    END
  END o[119]
  PIN o[11]
    DIRECTION OUTPUT ;
    USE SIGNAL ;
    PORT
      LAYER M3 ;
        RECT  3.24 0 3.258 0.038 ;
    END
  END o[11]
  PIN o[120]
    DIRECTION OUTPUT ;
    USE SIGNAL ;
    PORT
      LAYER M5 ;
        RECT  11.184 0 11.208 0.084 ;
    END
  END o[120]
  PIN o[121]
    DIRECTION OUTPUT ;
    USE SIGNAL ;
    PORT
      LAYER M5 ;
        RECT  11.28 0 11.304 0.084 ;
    END
  END o[121]
  PIN o[122]
    DIRECTION OUTPUT ;
    USE SIGNAL ;
    PORT
      LAYER M5 ;
        RECT  11.328 0 11.352 0.084 ;
    END
  END o[122]
  PIN o[123]
    DIRECTION OUTPUT ;
    USE SIGNAL ;
    PORT
      LAYER M5 ;
        RECT  11.424 0 11.448 0.084 ;
    END
  END o[123]
  PIN o[124]
    DIRECTION OUTPUT ;
    USE SIGNAL ;
    PORT
      LAYER M5 ;
        RECT  11.472 0 11.496 0.084 ;
    END
  END o[124]
  PIN o[125]
    DIRECTION OUTPUT ;
    USE SIGNAL ;
    PORT
      LAYER M5 ;
        RECT  11.568 0 11.592 0.084 ;
    END
  END o[125]
  PIN o[126]
    DIRECTION OUTPUT ;
    USE SIGNAL ;
    PORT
      LAYER M5 ;
        RECT  11.616 0 11.64 0.084 ;
    END
  END o[126]
  PIN o[127]
    DIRECTION OUTPUT ;
    USE SIGNAL ;
    PORT
      LAYER M5 ;
        RECT  11.712 0 11.736 0.084 ;
    END
  END o[127]
  PIN o[128]
    DIRECTION OUTPUT ;
    USE SIGNAL ;
    PORT
      LAYER M3 ;
        RECT  11.772 0 11.79 0.038 ;
    END
  END o[128]
  PIN o[129]
    DIRECTION OUTPUT ;
    USE SIGNAL ;
    PORT
      LAYER M3 ;
        RECT  11.844 0 11.862 0.038 ;
    END
  END o[129]
  PIN o[12]
    DIRECTION OUTPUT ;
    USE SIGNAL ;
    PORT
      LAYER M3 ;
        RECT  3.312 0 3.33 0.038 ;
    END
  END o[12]
  PIN o[130]
    DIRECTION OUTPUT ;
    USE SIGNAL ;
    PORT
      LAYER M3 ;
        RECT  11.916 0 11.934 0.038 ;
    END
  END o[130]
  PIN o[131]
    DIRECTION OUTPUT ;
    USE SIGNAL ;
    PORT
      LAYER M3 ;
        RECT  11.988 0 12.006 0.038 ;
    END
  END o[131]
  PIN o[132]
    DIRECTION OUTPUT ;
    USE SIGNAL ;
    PORT
      LAYER M3 ;
        RECT  12.06 0 12.078 0.038 ;
    END
  END o[132]
  PIN o[133]
    DIRECTION OUTPUT ;
    USE SIGNAL ;
    PORT
      LAYER M3 ;
        RECT  12.132 0 12.15 0.038 ;
    END
  END o[133]
  PIN o[134]
    DIRECTION OUTPUT ;
    USE SIGNAL ;
    PORT
      LAYER M3 ;
        RECT  12.204 0 12.222 0.038 ;
    END
  END o[134]
  PIN o[135]
    DIRECTION OUTPUT ;
    USE SIGNAL ;
    PORT
      LAYER M3 ;
        RECT  12.276 0 12.294 0.038 ;
    END
  END o[135]
  PIN o[136]
    DIRECTION OUTPUT ;
    USE SIGNAL ;
    PORT
      LAYER M3 ;
        RECT  12.348 0 12.366 0.038 ;
    END
  END o[136]
  PIN o[137]
    DIRECTION OUTPUT ;
    USE SIGNAL ;
    PORT
      LAYER M3 ;
        RECT  12.42 0 12.438 0.038 ;
    END
  END o[137]
  PIN o[138]
    DIRECTION OUTPUT ;
    USE SIGNAL ;
    PORT
      LAYER M3 ;
        RECT  12.492 0 12.51 0.038 ;
    END
  END o[138]
  PIN o[139]
    DIRECTION OUTPUT ;
    USE SIGNAL ;
    PORT
      LAYER M3 ;
        RECT  12.564 0 12.582 0.038 ;
    END
  END o[139]
  PIN o[13]
    DIRECTION OUTPUT ;
    USE SIGNAL ;
    PORT
      LAYER M3 ;
        RECT  3.384 0 3.402 0.038 ;
    END
  END o[13]
  PIN o[140]
    DIRECTION OUTPUT ;
    USE SIGNAL ;
    PORT
      LAYER M3 ;
        RECT  12.636 0 12.654 0.038 ;
    END
  END o[140]
  PIN o[141]
    DIRECTION OUTPUT ;
    USE SIGNAL ;
    PORT
      LAYER M3 ;
        RECT  12.708 0 12.726 0.038 ;
    END
  END o[141]
  PIN o[142]
    DIRECTION OUTPUT ;
    USE SIGNAL ;
    PORT
      LAYER M3 ;
        RECT  12.78 0 12.798 0.038 ;
    END
  END o[142]
  PIN o[143]
    DIRECTION OUTPUT ;
    USE SIGNAL ;
    PORT
      LAYER M3 ;
        RECT  12.852 0 12.87 0.038 ;
    END
  END o[143]
  PIN o[144]
    DIRECTION OUTPUT ;
    USE SIGNAL ;
    PORT
      LAYER M3 ;
        RECT  12.924 0 12.942 0.038 ;
    END
  END o[144]
  PIN o[145]
    DIRECTION OUTPUT ;
    USE SIGNAL ;
    PORT
      LAYER M3 ;
        RECT  12.996 0 13.014 0.038 ;
    END
  END o[145]
  PIN o[146]
    DIRECTION OUTPUT ;
    USE SIGNAL ;
    PORT
      LAYER M3 ;
        RECT  13.104 0 13.122 0.038 ;
    END
  END o[146]
  PIN o[147]
    DIRECTION OUTPUT ;
    USE SIGNAL ;
    PORT
      LAYER M3 ;
        RECT  13.176 0 13.194 0.038 ;
    END
  END o[147]
  PIN o[148]
    DIRECTION OUTPUT ;
    USE SIGNAL ;
    PORT
      LAYER M3 ;
        RECT  13.248 0 13.266 0.038 ;
    END
  END o[148]
  PIN o[149]
    DIRECTION OUTPUT ;
    USE SIGNAL ;
    PORT
      LAYER M3 ;
        RECT  13.32 0 13.338 0.038 ;
    END
  END o[149]
  PIN o[14]
    DIRECTION OUTPUT ;
    USE SIGNAL ;
    PORT
      LAYER M3 ;
        RECT  3.456 0 3.474 0.038 ;
    END
  END o[14]
  PIN o[150]
    DIRECTION OUTPUT ;
    USE SIGNAL ;
    PORT
      LAYER M3 ;
        RECT  13.392 0 13.41 0.038 ;
    END
  END o[150]
  PIN o[151]
    DIRECTION OUTPUT ;
    USE SIGNAL ;
    PORT
      LAYER M3 ;
        RECT  13.464 0 13.482 0.038 ;
    END
  END o[151]
  PIN o[152]
    DIRECTION OUTPUT ;
    USE SIGNAL ;
    PORT
      LAYER M3 ;
        RECT  13.536 0 13.554 0.038 ;
    END
  END o[152]
  PIN o[153]
    DIRECTION OUTPUT ;
    USE SIGNAL ;
    PORT
      LAYER M3 ;
        RECT  13.608 0 13.626 0.038 ;
    END
  END o[153]
  PIN o[154]
    DIRECTION OUTPUT ;
    USE SIGNAL ;
    PORT
      LAYER M3 ;
        RECT  13.68 0 13.698 0.038 ;
    END
  END o[154]
  PIN o[155]
    DIRECTION OUTPUT ;
    USE SIGNAL ;
    PORT
      LAYER M3 ;
        RECT  13.752 0 13.77 0.038 ;
    END
  END o[155]
  PIN o[156]
    DIRECTION OUTPUT ;
    USE SIGNAL ;
    PORT
      LAYER M3 ;
        RECT  13.824 0 13.842 0.038 ;
    END
  END o[156]
  PIN o[157]
    DIRECTION OUTPUT ;
    USE SIGNAL ;
    PORT
      LAYER M3 ;
        RECT  13.896 0 13.914 0.038 ;
    END
  END o[157]
  PIN o[158]
    DIRECTION OUTPUT ;
    USE SIGNAL ;
    PORT
      LAYER M3 ;
        RECT  13.968 0 13.986 0.038 ;
    END
  END o[158]
  PIN o[159]
    DIRECTION OUTPUT ;
    USE SIGNAL ;
    PORT
      LAYER M3 ;
        RECT  14.04 0 14.058 0.038 ;
    END
  END o[159]
  PIN o[15]
    DIRECTION OUTPUT ;
    USE SIGNAL ;
    PORT
      LAYER M3 ;
        RECT  3.528 0 3.546 0.038 ;
    END
  END o[15]
  PIN o[160]
    DIRECTION OUTPUT ;
    USE SIGNAL ;
    PORT
      LAYER M5 ;
        RECT  14.112 0 14.136 0.084 ;
    END
  END o[160]
  PIN o[161]
    DIRECTION OUTPUT ;
    USE SIGNAL ;
    PORT
      LAYER M5 ;
        RECT  14.16 0 14.184 0.084 ;
    END
  END o[161]
  PIN o[162]
    DIRECTION OUTPUT ;
    USE SIGNAL ;
    PORT
      LAYER M5 ;
        RECT  14.256 0 14.28 0.084 ;
    END
  END o[162]
  PIN o[163]
    DIRECTION OUTPUT ;
    USE SIGNAL ;
    PORT
      LAYER M5 ;
        RECT  14.304 0 14.328 0.084 ;
    END
  END o[163]
  PIN o[164]
    DIRECTION OUTPUT ;
    USE SIGNAL ;
    PORT
      LAYER M5 ;
        RECT  14.4 0 14.424 0.084 ;
    END
  END o[164]
  PIN o[165]
    DIRECTION OUTPUT ;
    USE SIGNAL ;
    PORT
      LAYER M5 ;
        RECT  14.448 0 14.472 0.084 ;
    END
  END o[165]
  PIN o[166]
    DIRECTION OUTPUT ;
    USE SIGNAL ;
    PORT
      LAYER M5 ;
        RECT  14.544 0 14.568 0.084 ;
    END
  END o[166]
  PIN o[167]
    DIRECTION OUTPUT ;
    USE SIGNAL ;
    PORT
      LAYER M5 ;
        RECT  14.64 0 14.664 0.084 ;
    END
  END o[167]
  PIN o[168]
    DIRECTION OUTPUT ;
    USE SIGNAL ;
    PORT
      LAYER M5 ;
        RECT  14.688 0 14.712 0.084 ;
    END
  END o[168]
  PIN o[169]
    DIRECTION OUTPUT ;
    USE SIGNAL ;
    PORT
      LAYER M5 ;
        RECT  14.784 0 14.808 0.084 ;
    END
  END o[169]
  PIN o[16]
    DIRECTION OUTPUT ;
    USE SIGNAL ;
    PORT
      LAYER M3 ;
        RECT  3.6 0 3.618 0.038 ;
    END
  END o[16]
  PIN o[170]
    DIRECTION OUTPUT ;
    USE SIGNAL ;
    PORT
      LAYER M5 ;
        RECT  14.832 0 14.856 0.084 ;
    END
  END o[170]
  PIN o[171]
    DIRECTION OUTPUT ;
    USE SIGNAL ;
    PORT
      LAYER M5 ;
        RECT  14.928 0 14.952 0.084 ;
    END
  END o[171]
  PIN o[172]
    DIRECTION OUTPUT ;
    USE SIGNAL ;
    PORT
      LAYER M5 ;
        RECT  14.976 0 15 0.084 ;
    END
  END o[172]
  PIN o[173]
    DIRECTION OUTPUT ;
    USE SIGNAL ;
    PORT
      LAYER M5 ;
        RECT  15.072 0 15.096 0.084 ;
    END
  END o[173]
  PIN o[174]
    DIRECTION OUTPUT ;
    USE SIGNAL ;
    PORT
      LAYER M5 ;
        RECT  15.12 0 15.144 0.084 ;
    END
  END o[174]
  PIN o[175]
    DIRECTION OUTPUT ;
    USE SIGNAL ;
    PORT
      LAYER M5 ;
        RECT  15.216 0 15.24 0.084 ;
    END
  END o[175]
  PIN o[176]
    DIRECTION OUTPUT ;
    USE SIGNAL ;
    PORT
      LAYER M5 ;
        RECT  15.264 0 15.288 0.084 ;
    END
  END o[176]
  PIN o[177]
    DIRECTION OUTPUT ;
    USE SIGNAL ;
    PORT
      LAYER M5 ;
        RECT  15.36 0 15.384 0.084 ;
    END
  END o[177]
  PIN o[178]
    DIRECTION OUTPUT ;
    USE SIGNAL ;
    PORT
      LAYER M5 ;
        RECT  15.408 0 15.432 0.084 ;
    END
  END o[178]
  PIN o[179]
    DIRECTION OUTPUT ;
    USE SIGNAL ;
    PORT
      LAYER M5 ;
        RECT  15.504 0 15.528 0.084 ;
    END
  END o[179]
  PIN o[17]
    DIRECTION OUTPUT ;
    USE SIGNAL ;
    PORT
      LAYER M3 ;
        RECT  3.672 0 3.69 0.038 ;
    END
  END o[17]
  PIN o[180]
    DIRECTION OUTPUT ;
    USE SIGNAL ;
    PORT
      LAYER M5 ;
        RECT  15.552 0 15.576 0.084 ;
    END
  END o[180]
  PIN o[181]
    DIRECTION OUTPUT ;
    USE SIGNAL ;
    PORT
      LAYER M5 ;
        RECT  15.648 0 15.672 0.084 ;
    END
  END o[181]
  PIN o[182]
    DIRECTION OUTPUT ;
    USE SIGNAL ;
    PORT
      LAYER M5 ;
        RECT  15.696 0 15.72 0.084 ;
    END
  END o[182]
  PIN o[183]
    DIRECTION OUTPUT ;
    USE SIGNAL ;
    PORT
      LAYER M5 ;
        RECT  15.792 0 15.816 0.084 ;
    END
  END o[183]
  PIN o[184]
    DIRECTION OUTPUT ;
    USE SIGNAL ;
    PORT
      LAYER M5 ;
        RECT  15.84 0 15.864 0.084 ;
    END
  END o[184]
  PIN o[185]
    DIRECTION OUTPUT ;
    USE SIGNAL ;
    PORT
      LAYER M5 ;
        RECT  15.936 0 15.96 0.084 ;
    END
  END o[185]
  PIN o[186]
    DIRECTION OUTPUT ;
    USE SIGNAL ;
    PORT
      LAYER M5 ;
        RECT  15.984 0 16.008 0.084 ;
    END
  END o[186]
  PIN o[187]
    DIRECTION OUTPUT ;
    USE SIGNAL ;
    PORT
      LAYER M5 ;
        RECT  16.08 0 16.104 0.084 ;
    END
  END o[187]
  PIN o[188]
    DIRECTION OUTPUT ;
    USE SIGNAL ;
    PORT
      LAYER M5 ;
        RECT  16.128 0 16.152 0.084 ;
    END
  END o[188]
  PIN o[189]
    DIRECTION OUTPUT ;
    USE SIGNAL ;
    PORT
      LAYER M5 ;
        RECT  16.224 0 16.248 0.084 ;
    END
  END o[189]
  PIN o[18]
    DIRECTION OUTPUT ;
    USE SIGNAL ;
    PORT
      LAYER M3 ;
        RECT  3.744 0 3.762 0.038 ;
    END
  END o[18]
  PIN o[190]
    DIRECTION OUTPUT ;
    USE SIGNAL ;
    PORT
      LAYER M5 ;
        RECT  16.272 0 16.296 0.084 ;
    END
  END o[190]
  PIN o[191]
    DIRECTION OUTPUT ;
    USE SIGNAL ;
    PORT
      LAYER M5 ;
        RECT  16.368 0 16.392 0.084 ;
    END
  END o[191]
  PIN o[192]
    DIRECTION OUTPUT ;
    USE SIGNAL ;
    PORT
      LAYER M3 ;
        RECT  16.452 0 16.47 0.038 ;
    END
  END o[192]
  PIN o[193]
    DIRECTION OUTPUT ;
    USE SIGNAL ;
    PORT
      LAYER M3 ;
        RECT  16.524 0 16.542 0.038 ;
    END
  END o[193]
  PIN o[194]
    DIRECTION OUTPUT ;
    USE SIGNAL ;
    PORT
      LAYER M3 ;
        RECT  16.596 0 16.614 0.038 ;
    END
  END o[194]
  PIN o[195]
    DIRECTION OUTPUT ;
    USE SIGNAL ;
    PORT
      LAYER M3 ;
        RECT  16.668 0 16.686 0.038 ;
    END
  END o[195]
  PIN o[196]
    DIRECTION OUTPUT ;
    USE SIGNAL ;
    PORT
      LAYER M3 ;
        RECT  16.74 0 16.758 0.038 ;
    END
  END o[196]
  PIN o[197]
    DIRECTION OUTPUT ;
    USE SIGNAL ;
    PORT
      LAYER M3 ;
        RECT  16.812 0 16.83 0.038 ;
    END
  END o[197]
  PIN o[198]
    DIRECTION OUTPUT ;
    USE SIGNAL ;
    PORT
      LAYER M3 ;
        RECT  16.884 0 16.902 0.038 ;
    END
  END o[198]
  PIN o[199]
    DIRECTION OUTPUT ;
    USE SIGNAL ;
    PORT
      LAYER M3 ;
        RECT  16.956 0 16.974 0.038 ;
    END
  END o[199]
  PIN o[19]
    DIRECTION OUTPUT ;
    USE SIGNAL ;
    PORT
      LAYER M3 ;
        RECT  3.816 0 3.834 0.038 ;
    END
  END o[19]
  PIN o[1]
    DIRECTION OUTPUT ;
    USE SIGNAL ;
    PORT
      LAYER M3 ;
        RECT  2.484 0 2.502 0.038 ;
    END
  END o[1]
  PIN o[200]
    DIRECTION OUTPUT ;
    USE SIGNAL ;
    PORT
      LAYER M3 ;
        RECT  17.028 0 17.046 0.038 ;
    END
  END o[200]
  PIN o[201]
    DIRECTION OUTPUT ;
    USE SIGNAL ;
    PORT
      LAYER M3 ;
        RECT  17.1 0 17.118 0.038 ;
    END
  END o[201]
  PIN o[202]
    DIRECTION OUTPUT ;
    USE SIGNAL ;
    PORT
      LAYER M3 ;
        RECT  17.172 0 17.19 0.038 ;
    END
  END o[202]
  PIN o[203]
    DIRECTION OUTPUT ;
    USE SIGNAL ;
    PORT
      LAYER M3 ;
        RECT  17.244 0 17.262 0.038 ;
    END
  END o[203]
  PIN o[204]
    DIRECTION OUTPUT ;
    USE SIGNAL ;
    PORT
      LAYER M3 ;
        RECT  17.316 0 17.334 0.038 ;
    END
  END o[204]
  PIN o[205]
    DIRECTION OUTPUT ;
    USE SIGNAL ;
    PORT
      LAYER M3 ;
        RECT  17.388 0 17.406 0.038 ;
    END
  END o[205]
  PIN o[206]
    DIRECTION OUTPUT ;
    USE SIGNAL ;
    PORT
      LAYER M3 ;
        RECT  17.46 0 17.478 0.038 ;
    END
  END o[206]
  PIN o[207]
    DIRECTION OUTPUT ;
    USE SIGNAL ;
    PORT
      LAYER M3 ;
        RECT  17.532 0 17.55 0.038 ;
    END
  END o[207]
  PIN o[208]
    DIRECTION OUTPUT ;
    USE SIGNAL ;
    PORT
      LAYER M3 ;
        RECT  17.604 0 17.622 0.038 ;
    END
  END o[208]
  PIN o[209]
    DIRECTION OUTPUT ;
    USE SIGNAL ;
    PORT
      LAYER M3 ;
        RECT  17.676 0 17.694 0.038 ;
    END
  END o[209]
  PIN o[20]
    DIRECTION OUTPUT ;
    USE SIGNAL ;
    PORT
      LAYER M3 ;
        RECT  3.888 0 3.906 0.038 ;
    END
  END o[20]
  PIN o[210]
    DIRECTION OUTPUT ;
    USE SIGNAL ;
    PORT
      LAYER M3 ;
        RECT  17.748 0 17.766 0.038 ;
    END
  END o[210]
  PIN o[211]
    DIRECTION OUTPUT ;
    USE SIGNAL ;
    PORT
      LAYER M3 ;
        RECT  17.82 0 17.838 0.038 ;
    END
  END o[211]
  PIN o[212]
    DIRECTION OUTPUT ;
    USE SIGNAL ;
    PORT
      LAYER M3 ;
        RECT  17.892 0 17.91 0.038 ;
    END
  END o[212]
  PIN o[213]
    DIRECTION OUTPUT ;
    USE SIGNAL ;
    PORT
      LAYER M3 ;
        RECT  17.964 0 17.982 0.038 ;
    END
  END o[213]
  PIN o[214]
    DIRECTION OUTPUT ;
    USE SIGNAL ;
    PORT
      LAYER M3 ;
        RECT  18.036 0 18.054 0.038 ;
    END
  END o[214]
  PIN o[215]
    DIRECTION OUTPUT ;
    USE SIGNAL ;
    PORT
      LAYER M3 ;
        RECT  18.108 0 18.126 0.038 ;
    END
  END o[215]
  PIN o[216]
    DIRECTION OUTPUT ;
    USE SIGNAL ;
    PORT
      LAYER M3 ;
        RECT  18.18 0 18.198 0.038 ;
    END
  END o[216]
  PIN o[217]
    DIRECTION OUTPUT ;
    USE SIGNAL ;
    PORT
      LAYER M3 ;
        RECT  18.252 0 18.27 0.038 ;
    END
  END o[217]
  PIN o[218]
    DIRECTION OUTPUT ;
    USE SIGNAL ;
    PORT
      LAYER M3 ;
        RECT  18.36 0 18.378 0.038 ;
    END
  END o[218]
  PIN o[219]
    DIRECTION OUTPUT ;
    USE SIGNAL ;
    PORT
      LAYER M3 ;
        RECT  18.432 0 18.45 0.038 ;
    END
  END o[219]
  PIN o[21]
    DIRECTION OUTPUT ;
    USE SIGNAL ;
    PORT
      LAYER M3 ;
        RECT  3.96 0 3.978 0.038 ;
    END
  END o[21]
  PIN o[220]
    DIRECTION OUTPUT ;
    USE SIGNAL ;
    PORT
      LAYER M3 ;
        RECT  18.504 0 18.522 0.038 ;
    END
  END o[220]
  PIN o[221]
    DIRECTION OUTPUT ;
    USE SIGNAL ;
    PORT
      LAYER M3 ;
        RECT  18.576 0 18.594 0.038 ;
    END
  END o[221]
  PIN o[222]
    DIRECTION OUTPUT ;
    USE SIGNAL ;
    PORT
      LAYER M3 ;
        RECT  18.648 0 18.666 0.038 ;
    END
  END o[222]
  PIN o[223]
    DIRECTION OUTPUT ;
    USE SIGNAL ;
    PORT
      LAYER M3 ;
        RECT  18.72 0 18.738 0.038 ;
    END
  END o[223]
  PIN o[224]
    DIRECTION OUTPUT ;
    USE SIGNAL ;
    PORT
      LAYER M5 ;
        RECT  18.768 0 18.792 0.084 ;
    END
  END o[224]
  PIN o[225]
    DIRECTION OUTPUT ;
    USE SIGNAL ;
    PORT
      LAYER M5 ;
        RECT  18.864 0 18.888 0.084 ;
    END
  END o[225]
  PIN o[226]
    DIRECTION OUTPUT ;
    USE SIGNAL ;
    PORT
      LAYER M5 ;
        RECT  18.912 0 18.936 0.084 ;
    END
  END o[226]
  PIN o[227]
    DIRECTION OUTPUT ;
    USE SIGNAL ;
    PORT
      LAYER M5 ;
        RECT  19.008 0 19.032 0.084 ;
    END
  END o[227]
  PIN o[228]
    DIRECTION OUTPUT ;
    USE SIGNAL ;
    PORT
      LAYER M5 ;
        RECT  19.056 0 19.08 0.084 ;
    END
  END o[228]
  PIN o[229]
    DIRECTION OUTPUT ;
    USE SIGNAL ;
    PORT
      LAYER M5 ;
        RECT  19.152 0 19.176 0.084 ;
    END
  END o[229]
  PIN o[22]
    DIRECTION OUTPUT ;
    USE SIGNAL ;
    PORT
      LAYER M3 ;
        RECT  4.032 0 4.05 0.038 ;
    END
  END o[22]
  PIN o[230]
    DIRECTION OUTPUT ;
    USE SIGNAL ;
    PORT
      LAYER M5 ;
        RECT  19.2 0 19.224 0.084 ;
    END
  END o[230]
  PIN o[231]
    DIRECTION OUTPUT ;
    USE SIGNAL ;
    PORT
      LAYER M5 ;
        RECT  19.296 0 19.32 0.084 ;
    END
  END o[231]
  PIN o[232]
    DIRECTION OUTPUT ;
    USE SIGNAL ;
    PORT
      LAYER M5 ;
        RECT  19.344 0 19.368 0.084 ;
    END
  END o[232]
  PIN o[233]
    DIRECTION OUTPUT ;
    USE SIGNAL ;
    PORT
      LAYER M5 ;
        RECT  19.44 0 19.464 0.084 ;
    END
  END o[233]
  PIN o[234]
    DIRECTION OUTPUT ;
    USE SIGNAL ;
    PORT
      LAYER M5 ;
        RECT  19.488 0 19.512 0.084 ;
    END
  END o[234]
  PIN o[235]
    DIRECTION OUTPUT ;
    USE SIGNAL ;
    PORT
      LAYER M5 ;
        RECT  19.584 0 19.608 0.084 ;
    END
  END o[235]
  PIN o[236]
    DIRECTION OUTPUT ;
    USE SIGNAL ;
    PORT
      LAYER M5 ;
        RECT  19.632 0 19.656 0.084 ;
    END
  END o[236]
  PIN o[237]
    DIRECTION OUTPUT ;
    USE SIGNAL ;
    PORT
      LAYER M5 ;
        RECT  19.728 0 19.752 0.084 ;
    END
  END o[237]
  PIN o[238]
    DIRECTION OUTPUT ;
    USE SIGNAL ;
    PORT
      LAYER M5 ;
        RECT  19.776 0 19.8 0.084 ;
    END
  END o[238]
  PIN o[239]
    DIRECTION OUTPUT ;
    USE SIGNAL ;
    PORT
      LAYER M5 ;
        RECT  19.872 0 19.896 0.084 ;
    END
  END o[239]
  PIN o[23]
    DIRECTION OUTPUT ;
    USE SIGNAL ;
    PORT
      LAYER M3 ;
        RECT  4.104 0 4.122 0.038 ;
    END
  END o[23]
  PIN o[240]
    DIRECTION OUTPUT ;
    USE SIGNAL ;
    PORT
      LAYER M5 ;
        RECT  19.968 0 19.992 0.084 ;
    END
  END o[240]
  PIN o[241]
    DIRECTION OUTPUT ;
    USE SIGNAL ;
    PORT
      LAYER M5 ;
        RECT  20.016 0 20.04 0.084 ;
    END
  END o[241]
  PIN o[242]
    DIRECTION OUTPUT ;
    USE SIGNAL ;
    PORT
      LAYER M5 ;
        RECT  20.112 0 20.136 0.084 ;
    END
  END o[242]
  PIN o[243]
    DIRECTION OUTPUT ;
    USE SIGNAL ;
    PORT
      LAYER M5 ;
        RECT  20.16 0 20.184 0.084 ;
    END
  END o[243]
  PIN o[244]
    DIRECTION OUTPUT ;
    USE SIGNAL ;
    PORT
      LAYER M5 ;
        RECT  20.256 0 20.28 0.084 ;
    END
  END o[244]
  PIN o[245]
    DIRECTION OUTPUT ;
    USE SIGNAL ;
    PORT
      LAYER M5 ;
        RECT  20.304 0 20.328 0.084 ;
    END
  END o[245]
  PIN o[246]
    DIRECTION OUTPUT ;
    USE SIGNAL ;
    PORT
      LAYER M5 ;
        RECT  20.4 0 20.424 0.084 ;
    END
  END o[246]
  PIN o[247]
    DIRECTION OUTPUT ;
    USE SIGNAL ;
    PORT
      LAYER M5 ;
        RECT  20.448 0 20.472 0.084 ;
    END
  END o[247]
  PIN o[248]
    DIRECTION OUTPUT ;
    USE SIGNAL ;
    PORT
      LAYER M5 ;
        RECT  20.544 0 20.568 0.084 ;
    END
  END o[248]
  PIN o[249]
    DIRECTION OUTPUT ;
    USE SIGNAL ;
    PORT
      LAYER M5 ;
        RECT  20.592 0 20.616 0.084 ;
    END
  END o[249]
  PIN o[24]
    DIRECTION OUTPUT ;
    USE SIGNAL ;
    PORT
      LAYER M3 ;
        RECT  4.176 0 4.194 0.038 ;
    END
  END o[24]
  PIN o[250]
    DIRECTION OUTPUT ;
    USE SIGNAL ;
    PORT
      LAYER M5 ;
        RECT  20.688 0 20.712 0.084 ;
    END
  END o[250]
  PIN o[251]
    DIRECTION OUTPUT ;
    USE SIGNAL ;
    PORT
      LAYER M5 ;
        RECT  20.736 0 20.76 0.084 ;
    END
  END o[251]
  PIN o[252]
    DIRECTION OUTPUT ;
    USE SIGNAL ;
    PORT
      LAYER M5 ;
        RECT  20.832 0 20.856 0.084 ;
    END
  END o[252]
  PIN o[253]
    DIRECTION OUTPUT ;
    USE SIGNAL ;
    PORT
      LAYER M5 ;
        RECT  20.88 0 20.904 0.084 ;
    END
  END o[253]
  PIN o[254]
    DIRECTION OUTPUT ;
    USE SIGNAL ;
    PORT
      LAYER M5 ;
        RECT  20.976 0 21 0.084 ;
    END
  END o[254]
  PIN o[255]
    DIRECTION OUTPUT ;
    USE SIGNAL ;
    PORT
      LAYER M5 ;
        RECT  21.024 0 21.048 0.084 ;
    END
  END o[255]
  PIN o[256]
    DIRECTION OUTPUT ;
    USE SIGNAL ;
    PORT
      LAYER M3 ;
        RECT  21.132 0 21.15 0.038 ;
    END
  END o[256]
  PIN o[257]
    DIRECTION OUTPUT ;
    USE SIGNAL ;
    PORT
      LAYER M3 ;
        RECT  21.204 0 21.222 0.038 ;
    END
  END o[257]
  PIN o[258]
    DIRECTION OUTPUT ;
    USE SIGNAL ;
    PORT
      LAYER M3 ;
        RECT  21.276 0 21.294 0.038 ;
    END
  END o[258]
  PIN o[259]
    DIRECTION OUTPUT ;
    USE SIGNAL ;
    PORT
      LAYER M3 ;
        RECT  21.348 0 21.366 0.038 ;
    END
  END o[259]
  PIN o[25]
    DIRECTION OUTPUT ;
    USE SIGNAL ;
    PORT
      LAYER M3 ;
        RECT  4.248 0 4.266 0.038 ;
    END
  END o[25]
  PIN o[260]
    DIRECTION OUTPUT ;
    USE SIGNAL ;
    PORT
      LAYER M3 ;
        RECT  21.42 0 21.438 0.038 ;
    END
  END o[260]
  PIN o[261]
    DIRECTION OUTPUT ;
    USE SIGNAL ;
    PORT
      LAYER M3 ;
        RECT  21.492 0 21.51 0.038 ;
    END
  END o[261]
  PIN o[262]
    DIRECTION OUTPUT ;
    USE SIGNAL ;
    PORT
      LAYER M3 ;
        RECT  21.564 0 21.582 0.038 ;
    END
  END o[262]
  PIN o[263]
    DIRECTION OUTPUT ;
    USE SIGNAL ;
    PORT
      LAYER M3 ;
        RECT  21.636 0 21.654 0.038 ;
    END
  END o[263]
  PIN o[264]
    DIRECTION OUTPUT ;
    USE SIGNAL ;
    PORT
      LAYER M3 ;
        RECT  21.708 0 21.726 0.038 ;
    END
  END o[264]
  PIN o[265]
    DIRECTION OUTPUT ;
    USE SIGNAL ;
    PORT
      LAYER M3 ;
        RECT  21.78 0 21.798 0.038 ;
    END
  END o[265]
  PIN o[266]
    DIRECTION OUTPUT ;
    USE SIGNAL ;
    PORT
      LAYER M3 ;
        RECT  21.852 0 21.87 0.038 ;
    END
  END o[266]
  PIN o[267]
    DIRECTION OUTPUT ;
    USE SIGNAL ;
    PORT
      LAYER M3 ;
        RECT  21.924 0 21.942 0.038 ;
    END
  END o[267]
  PIN o[268]
    DIRECTION OUTPUT ;
    USE SIGNAL ;
    PORT
      LAYER M3 ;
        RECT  21.996 0 22.014 0.038 ;
    END
  END o[268]
  PIN o[269]
    DIRECTION OUTPUT ;
    USE SIGNAL ;
    PORT
      LAYER M3 ;
        RECT  22.068 0 22.086 0.038 ;
    END
  END o[269]
  PIN o[26]
    DIRECTION OUTPUT ;
    USE SIGNAL ;
    PORT
      LAYER M3 ;
        RECT  4.32 0 4.338 0.038 ;
    END
  END o[26]
  PIN o[270]
    DIRECTION OUTPUT ;
    USE SIGNAL ;
    PORT
      LAYER M3 ;
        RECT  22.14 0 22.158 0.038 ;
    END
  END o[270]
  PIN o[271]
    DIRECTION OUTPUT ;
    USE SIGNAL ;
    PORT
      LAYER M3 ;
        RECT  22.212 0 22.23 0.038 ;
    END
  END o[271]
  PIN o[272]
    DIRECTION OUTPUT ;
    USE SIGNAL ;
    PORT
      LAYER M3 ;
        RECT  22.284 0 22.302 0.038 ;
    END
  END o[272]
  PIN o[273]
    DIRECTION OUTPUT ;
    USE SIGNAL ;
    PORT
      LAYER M3 ;
        RECT  22.356 0 22.374 0.038 ;
    END
  END o[273]
  PIN o[274]
    DIRECTION OUTPUT ;
    USE SIGNAL ;
    PORT
      LAYER M3 ;
        RECT  22.428 0 22.446 0.038 ;
    END
  END o[274]
  PIN o[275]
    DIRECTION OUTPUT ;
    USE SIGNAL ;
    PORT
      LAYER M3 ;
        RECT  22.5 0 22.518 0.038 ;
    END
  END o[275]
  PIN o[276]
    DIRECTION OUTPUT ;
    USE SIGNAL ;
    PORT
      LAYER M3 ;
        RECT  22.572 0 22.59 0.038 ;
    END
  END o[276]
  PIN o[277]
    DIRECTION OUTPUT ;
    USE SIGNAL ;
    PORT
      LAYER M3 ;
        RECT  22.644 0 22.662 0.038 ;
    END
  END o[277]
  PIN o[278]
    DIRECTION OUTPUT ;
    USE SIGNAL ;
    PORT
      LAYER M3 ;
        RECT  22.716 0 22.734 0.038 ;
    END
  END o[278]
  PIN o[279]
    DIRECTION OUTPUT ;
    USE SIGNAL ;
    PORT
      LAYER M3 ;
        RECT  22.788 0 22.806 0.038 ;
    END
  END o[279]
  PIN o[27]
    DIRECTION OUTPUT ;
    USE SIGNAL ;
    PORT
      LAYER M3 ;
        RECT  4.392 0 4.41 0.038 ;
    END
  END o[27]
  PIN o[280]
    DIRECTION OUTPUT ;
    USE SIGNAL ;
    PORT
      LAYER M3 ;
        RECT  22.86 0 22.878 0.038 ;
    END
  END o[280]
  PIN o[281]
    DIRECTION OUTPUT ;
    USE SIGNAL ;
    PORT
      LAYER M3 ;
        RECT  22.932 0 22.95 0.038 ;
    END
  END o[281]
  PIN o[282]
    DIRECTION OUTPUT ;
    USE SIGNAL ;
    PORT
      LAYER M3 ;
        RECT  23.004 0 23.022 0.038 ;
    END
  END o[282]
  PIN o[283]
    DIRECTION OUTPUT ;
    USE SIGNAL ;
    PORT
      LAYER M3 ;
        RECT  23.076 0 23.094 0.038 ;
    END
  END o[283]
  PIN o[284]
    DIRECTION OUTPUT ;
    USE SIGNAL ;
    PORT
      LAYER M3 ;
        RECT  23.148 0 23.166 0.038 ;
    END
  END o[284]
  PIN o[285]
    DIRECTION OUTPUT ;
    USE SIGNAL ;
    PORT
      LAYER M3 ;
        RECT  23.22 0 23.238 0.038 ;
    END
  END o[285]
  PIN o[286]
    DIRECTION OUTPUT ;
    USE SIGNAL ;
    PORT
      LAYER M3 ;
        RECT  23.292 0 23.31 0.038 ;
    END
  END o[286]
  PIN o[287]
    DIRECTION OUTPUT ;
    USE SIGNAL ;
    PORT
      LAYER M3 ;
        RECT  23.364 0 23.382 0.038 ;
    END
  END o[287]
  PIN o[288]
    DIRECTION OUTPUT ;
    USE SIGNAL ;
    PORT
      LAYER M5 ;
        RECT  23.472 0 23.496 0.084 ;
    END
  END o[288]
  PIN o[289]
    DIRECTION OUTPUT ;
    USE SIGNAL ;
    PORT
      LAYER M5 ;
        RECT  23.52 0 23.544 0.084 ;
    END
  END o[289]
  PIN o[28]
    DIRECTION OUTPUT ;
    USE SIGNAL ;
    PORT
      LAYER M3 ;
        RECT  4.464 0 4.482 0.038 ;
    END
  END o[28]
  PIN o[290]
    DIRECTION OUTPUT ;
    USE SIGNAL ;
    PORT
      LAYER M5 ;
        RECT  23.616 0 23.64 0.084 ;
    END
  END o[290]
  PIN o[291]
    DIRECTION OUTPUT ;
    USE SIGNAL ;
    PORT
      LAYER M5 ;
        RECT  23.664 0 23.688 0.084 ;
    END
  END o[291]
  PIN o[292]
    DIRECTION OUTPUT ;
    USE SIGNAL ;
    PORT
      LAYER M5 ;
        RECT  23.76 0 23.784 0.084 ;
    END
  END o[292]
  PIN o[293]
    DIRECTION OUTPUT ;
    USE SIGNAL ;
    PORT
      LAYER M5 ;
        RECT  23.808 0 23.832 0.084 ;
    END
  END o[293]
  PIN o[294]
    DIRECTION OUTPUT ;
    USE SIGNAL ;
    PORT
      LAYER M5 ;
        RECT  23.904 0 23.928 0.084 ;
    END
  END o[294]
  PIN o[295]
    DIRECTION OUTPUT ;
    USE SIGNAL ;
    PORT
      LAYER M5 ;
        RECT  23.952 0 23.976 0.084 ;
    END
  END o[295]
  PIN o[296]
    DIRECTION OUTPUT ;
    USE SIGNAL ;
    PORT
      LAYER M5 ;
        RECT  24.048 0 24.072 0.084 ;
    END
  END o[296]
  PIN o[297]
    DIRECTION OUTPUT ;
    USE SIGNAL ;
    PORT
      LAYER M5 ;
        RECT  24.096 0 24.12 0.084 ;
    END
  END o[297]
  PIN o[298]
    DIRECTION OUTPUT ;
    USE SIGNAL ;
    PORT
      LAYER M5 ;
        RECT  24.192 0 24.216 0.084 ;
    END
  END o[298]
  PIN o[299]
    DIRECTION OUTPUT ;
    USE SIGNAL ;
    PORT
      LAYER M5 ;
        RECT  24.24 0 24.264 0.084 ;
    END
  END o[299]
  PIN o[29]
    DIRECTION OUTPUT ;
    USE SIGNAL ;
    PORT
      LAYER M3 ;
        RECT  4.536 0 4.554 0.038 ;
    END
  END o[29]
  PIN o[2]
    DIRECTION OUTPUT ;
    USE SIGNAL ;
    PORT
      LAYER M3 ;
        RECT  2.592 0 2.61 0.038 ;
    END
  END o[2]
  PIN o[300]
    DIRECTION OUTPUT ;
    USE SIGNAL ;
    PORT
      LAYER M5 ;
        RECT  24.336 0 24.36 0.084 ;
    END
  END o[300]
  PIN o[301]
    DIRECTION OUTPUT ;
    USE SIGNAL ;
    PORT
      LAYER M5 ;
        RECT  24.384 0 24.408 0.084 ;
    END
  END o[301]
  PIN o[302]
    DIRECTION OUTPUT ;
    USE SIGNAL ;
    PORT
      LAYER M5 ;
        RECT  24.48 0 24.504 0.084 ;
    END
  END o[302]
  PIN o[303]
    DIRECTION OUTPUT ;
    USE SIGNAL ;
    PORT
      LAYER M5 ;
        RECT  24.528 0 24.552 0.084 ;
    END
  END o[303]
  PIN o[304]
    DIRECTION OUTPUT ;
    USE SIGNAL ;
    PORT
      LAYER M5 ;
        RECT  24.624 0 24.648 0.084 ;
    END
  END o[304]
  PIN o[305]
    DIRECTION OUTPUT ;
    USE SIGNAL ;
    PORT
      LAYER M5 ;
        RECT  24.672 0 24.696 0.084 ;
    END
  END o[305]
  PIN o[306]
    DIRECTION OUTPUT ;
    USE SIGNAL ;
    PORT
      LAYER M5 ;
        RECT  24.768 0 24.792 0.084 ;
    END
  END o[306]
  PIN o[307]
    DIRECTION OUTPUT ;
    USE SIGNAL ;
    PORT
      LAYER M5 ;
        RECT  24.816 0 24.84 0.084 ;
    END
  END o[307]
  PIN o[308]
    DIRECTION OUTPUT ;
    USE SIGNAL ;
    PORT
      LAYER M5 ;
        RECT  24.912 0 24.936 0.084 ;
    END
  END o[308]
  PIN o[309]
    DIRECTION OUTPUT ;
    USE SIGNAL ;
    PORT
      LAYER M5 ;
        RECT  24.96 0 24.984 0.084 ;
    END
  END o[309]
  PIN o[30]
    DIRECTION OUTPUT ;
    USE SIGNAL ;
    PORT
      LAYER M3 ;
        RECT  4.608 0 4.626 0.038 ;
    END
  END o[30]
  PIN o[310]
    DIRECTION OUTPUT ;
    USE SIGNAL ;
    PORT
      LAYER M5 ;
        RECT  25.056 0 25.08 0.084 ;
    END
  END o[310]
  PIN o[311]
    DIRECTION OUTPUT ;
    USE SIGNAL ;
    PORT
      LAYER M5 ;
        RECT  25.152 0 25.176 0.084 ;
    END
  END o[311]
  PIN o[312]
    DIRECTION OUTPUT ;
    USE SIGNAL ;
    PORT
      LAYER M5 ;
        RECT  25.2 0 25.224 0.084 ;
    END
  END o[312]
  PIN o[313]
    DIRECTION OUTPUT ;
    USE SIGNAL ;
    PORT
      LAYER M5 ;
        RECT  25.296 0 25.32 0.084 ;
    END
  END o[313]
  PIN o[314]
    DIRECTION OUTPUT ;
    USE SIGNAL ;
    PORT
      LAYER M5 ;
        RECT  25.344 0 25.368 0.084 ;
    END
  END o[314]
  PIN o[315]
    DIRECTION OUTPUT ;
    USE SIGNAL ;
    PORT
      LAYER M5 ;
        RECT  25.44 0 25.464 0.084 ;
    END
  END o[315]
  PIN o[316]
    DIRECTION OUTPUT ;
    USE SIGNAL ;
    PORT
      LAYER M5 ;
        RECT  25.488 0 25.512 0.084 ;
    END
  END o[316]
  PIN o[317]
    DIRECTION OUTPUT ;
    USE SIGNAL ;
    PORT
      LAYER M5 ;
        RECT  25.584 0 25.608 0.084 ;
    END
  END o[317]
  PIN o[318]
    DIRECTION OUTPUT ;
    USE SIGNAL ;
    PORT
      LAYER M5 ;
        RECT  25.632 0 25.656 0.084 ;
    END
  END o[318]
  PIN o[319]
    DIRECTION OUTPUT ;
    USE SIGNAL ;
    PORT
      LAYER M5 ;
        RECT  25.728 0 25.752 0.084 ;
    END
  END o[319]
  PIN o[31]
    DIRECTION OUTPUT ;
    USE SIGNAL ;
    PORT
      LAYER M3 ;
        RECT  4.68 0 4.698 0.038 ;
    END
  END o[31]
  PIN o[320]
    DIRECTION OUTPUT ;
    USE SIGNAL ;
    PORT
      LAYER M3 ;
        RECT  25.776 0 25.794 0.038 ;
    END
  END o[320]
  PIN o[321]
    DIRECTION OUTPUT ;
    USE SIGNAL ;
    PORT
      LAYER M3 ;
        RECT  25.848 0 25.866 0.038 ;
    END
  END o[321]
  PIN o[322]
    DIRECTION OUTPUT ;
    USE SIGNAL ;
    PORT
      LAYER M3 ;
        RECT  25.92 0 25.938 0.038 ;
    END
  END o[322]
  PIN o[323]
    DIRECTION OUTPUT ;
    USE SIGNAL ;
    PORT
      LAYER M3 ;
        RECT  25.992 0 26.01 0.038 ;
    END
  END o[323]
  PIN o[324]
    DIRECTION OUTPUT ;
    USE SIGNAL ;
    PORT
      LAYER M3 ;
        RECT  26.064 0 26.082 0.038 ;
    END
  END o[324]
  PIN o[325]
    DIRECTION OUTPUT ;
    USE SIGNAL ;
    PORT
      LAYER M3 ;
        RECT  26.172 0 26.19 0.038 ;
    END
  END o[325]
  PIN o[326]
    DIRECTION OUTPUT ;
    USE SIGNAL ;
    PORT
      LAYER M3 ;
        RECT  26.244 0 26.262 0.038 ;
    END
  END o[326]
  PIN o[327]
    DIRECTION OUTPUT ;
    USE SIGNAL ;
    PORT
      LAYER M3 ;
        RECT  26.316 0 26.334 0.038 ;
    END
  END o[327]
  PIN o[328]
    DIRECTION OUTPUT ;
    USE SIGNAL ;
    PORT
      LAYER M3 ;
        RECT  26.388 0 26.406 0.038 ;
    END
  END o[328]
  PIN o[329]
    DIRECTION OUTPUT ;
    USE SIGNAL ;
    PORT
      LAYER M3 ;
        RECT  26.46 0 26.478 0.038 ;
    END
  END o[329]
  PIN o[32]
    DIRECTION OUTPUT ;
    USE SIGNAL ;
    PORT
      LAYER M5 ;
        RECT  4.752 0 4.776 0.084 ;
    END
  END o[32]
  PIN o[330]
    DIRECTION OUTPUT ;
    USE SIGNAL ;
    PORT
      LAYER M3 ;
        RECT  26.532 0 26.55 0.038 ;
    END
  END o[330]
  PIN o[331]
    DIRECTION OUTPUT ;
    USE SIGNAL ;
    PORT
      LAYER M3 ;
        RECT  26.604 0 26.622 0.038 ;
    END
  END o[331]
  PIN o[332]
    DIRECTION OUTPUT ;
    USE SIGNAL ;
    PORT
      LAYER M3 ;
        RECT  26.676 0 26.694 0.038 ;
    END
  END o[332]
  PIN o[333]
    DIRECTION OUTPUT ;
    USE SIGNAL ;
    PORT
      LAYER M3 ;
        RECT  26.748 0 26.766 0.038 ;
    END
  END o[333]
  PIN o[334]
    DIRECTION OUTPUT ;
    USE SIGNAL ;
    PORT
      LAYER M3 ;
        RECT  26.82 0 26.838 0.038 ;
    END
  END o[334]
  PIN o[335]
    DIRECTION OUTPUT ;
    USE SIGNAL ;
    PORT
      LAYER M3 ;
        RECT  26.892 0 26.91 0.038 ;
    END
  END o[335]
  PIN o[336]
    DIRECTION OUTPUT ;
    USE SIGNAL ;
    PORT
      LAYER M3 ;
        RECT  26.964 0 26.982 0.038 ;
    END
  END o[336]
  PIN o[337]
    DIRECTION OUTPUT ;
    USE SIGNAL ;
    PORT
      LAYER M3 ;
        RECT  27.036 0 27.054 0.038 ;
    END
  END o[337]
  PIN o[338]
    DIRECTION OUTPUT ;
    USE SIGNAL ;
    PORT
      LAYER M3 ;
        RECT  27.108 0 27.126 0.038 ;
    END
  END o[338]
  PIN o[339]
    DIRECTION OUTPUT ;
    USE SIGNAL ;
    PORT
      LAYER M3 ;
        RECT  27.18 0 27.198 0.038 ;
    END
  END o[339]
  PIN o[33]
    DIRECTION OUTPUT ;
    USE SIGNAL ;
    PORT
      LAYER M5 ;
        RECT  4.848 0 4.872 0.084 ;
    END
  END o[33]
  PIN o[340]
    DIRECTION OUTPUT ;
    USE SIGNAL ;
    PORT
      LAYER M3 ;
        RECT  27.252 0 27.27 0.038 ;
    END
  END o[340]
  PIN o[341]
    DIRECTION OUTPUT ;
    USE SIGNAL ;
    PORT
      LAYER M3 ;
        RECT  27.324 0 27.342 0.038 ;
    END
  END o[341]
  PIN o[342]
    DIRECTION OUTPUT ;
    USE SIGNAL ;
    PORT
      LAYER M3 ;
        RECT  27.396 0 27.414 0.038 ;
    END
  END o[342]
  PIN o[343]
    DIRECTION OUTPUT ;
    USE SIGNAL ;
    PORT
      LAYER M3 ;
        RECT  27.468 0 27.486 0.038 ;
    END
  END o[343]
  PIN o[344]
    DIRECTION OUTPUT ;
    USE SIGNAL ;
    PORT
      LAYER M3 ;
        RECT  27.54 0 27.558 0.038 ;
    END
  END o[344]
  PIN o[345]
    DIRECTION OUTPUT ;
    USE SIGNAL ;
    PORT
      LAYER M3 ;
        RECT  27.612 0 27.63 0.038 ;
    END
  END o[345]
  PIN o[346]
    DIRECTION OUTPUT ;
    USE SIGNAL ;
    PORT
      LAYER M3 ;
        RECT  27.684 0 27.702 0.038 ;
    END
  END o[346]
  PIN o[347]
    DIRECTION OUTPUT ;
    USE SIGNAL ;
    PORT
      LAYER M3 ;
        RECT  27.756 0 27.774 0.038 ;
    END
  END o[347]
  PIN o[348]
    DIRECTION OUTPUT ;
    USE SIGNAL ;
    PORT
      LAYER M3 ;
        RECT  27.828 0 27.846 0.038 ;
    END
  END o[348]
  PIN o[349]
    DIRECTION OUTPUT ;
    USE SIGNAL ;
    PORT
      LAYER M3 ;
        RECT  27.9 0 27.918 0.038 ;
    END
  END o[349]
  PIN o[34]
    DIRECTION OUTPUT ;
    USE SIGNAL ;
    PORT
      LAYER M5 ;
        RECT  4.896 0 4.92 0.084 ;
    END
  END o[34]
  PIN o[350]
    DIRECTION OUTPUT ;
    USE SIGNAL ;
    PORT
      LAYER M3 ;
        RECT  27.972 0 27.99 0.038 ;
    END
  END o[350]
  PIN o[351]
    DIRECTION OUTPUT ;
    USE SIGNAL ;
    PORT
      LAYER M3 ;
        RECT  28.044 0 28.062 0.038 ;
    END
  END o[351]
  PIN o[352]
    DIRECTION OUTPUT ;
    USE SIGNAL ;
    PORT
      LAYER M5 ;
        RECT  28.128 0 28.152 0.084 ;
    END
  END o[352]
  PIN o[353]
    DIRECTION OUTPUT ;
    USE SIGNAL ;
    PORT
      LAYER M5 ;
        RECT  28.176 0 28.2 0.084 ;
    END
  END o[353]
  PIN o[354]
    DIRECTION OUTPUT ;
    USE SIGNAL ;
    PORT
      LAYER M5 ;
        RECT  28.272 0 28.296 0.084 ;
    END
  END o[354]
  PIN o[355]
    DIRECTION OUTPUT ;
    USE SIGNAL ;
    PORT
      LAYER M5 ;
        RECT  28.32 0 28.344 0.084 ;
    END
  END o[355]
  PIN o[356]
    DIRECTION OUTPUT ;
    USE SIGNAL ;
    PORT
      LAYER M5 ;
        RECT  28.416 0 28.44 0.084 ;
    END
  END o[356]
  PIN o[357]
    DIRECTION OUTPUT ;
    USE SIGNAL ;
    PORT
      LAYER M5 ;
        RECT  28.464 0 28.488 0.084 ;
    END
  END o[357]
  PIN o[358]
    DIRECTION OUTPUT ;
    USE SIGNAL ;
    PORT
      LAYER M5 ;
        RECT  28.56 0 28.584 0.084 ;
    END
  END o[358]
  PIN o[359]
    DIRECTION OUTPUT ;
    USE SIGNAL ;
    PORT
      LAYER M5 ;
        RECT  28.656 0 28.68 0.084 ;
    END
  END o[359]
  PIN o[35]
    DIRECTION OUTPUT ;
    USE SIGNAL ;
    PORT
      LAYER M5 ;
        RECT  4.992 0 5.016 0.084 ;
    END
  END o[35]
  PIN o[360]
    DIRECTION OUTPUT ;
    USE SIGNAL ;
    PORT
      LAYER M5 ;
        RECT  28.704 0 28.728 0.084 ;
    END
  END o[360]
  PIN o[361]
    DIRECTION OUTPUT ;
    USE SIGNAL ;
    PORT
      LAYER M5 ;
        RECT  28.8 0 28.824 0.084 ;
    END
  END o[361]
  PIN o[362]
    DIRECTION OUTPUT ;
    USE SIGNAL ;
    PORT
      LAYER M5 ;
        RECT  28.848 0 28.872 0.084 ;
    END
  END o[362]
  PIN o[363]
    DIRECTION OUTPUT ;
    USE SIGNAL ;
    PORT
      LAYER M5 ;
        RECT  28.944 0 28.968 0.084 ;
    END
  END o[363]
  PIN o[364]
    DIRECTION OUTPUT ;
    USE SIGNAL ;
    PORT
      LAYER M5 ;
        RECT  28.992 0 29.016 0.084 ;
    END
  END o[364]
  PIN o[365]
    DIRECTION OUTPUT ;
    USE SIGNAL ;
    PORT
      LAYER M5 ;
        RECT  29.088 0 29.112 0.084 ;
    END
  END o[365]
  PIN o[366]
    DIRECTION OUTPUT ;
    USE SIGNAL ;
    PORT
      LAYER M5 ;
        RECT  29.136 0 29.16 0.084 ;
    END
  END o[366]
  PIN o[367]
    DIRECTION OUTPUT ;
    USE SIGNAL ;
    PORT
      LAYER M5 ;
        RECT  29.232 0 29.256 0.084 ;
    END
  END o[367]
  PIN o[368]
    DIRECTION OUTPUT ;
    USE SIGNAL ;
    PORT
      LAYER M5 ;
        RECT  29.28 0 29.304 0.084 ;
    END
  END o[368]
  PIN o[369]
    DIRECTION OUTPUT ;
    USE SIGNAL ;
    PORT
      LAYER M5 ;
        RECT  29.376 0 29.4 0.084 ;
    END
  END o[369]
  PIN o[36]
    DIRECTION OUTPUT ;
    USE SIGNAL ;
    PORT
      LAYER M5 ;
        RECT  5.04 0 5.064 0.084 ;
    END
  END o[36]
  PIN o[370]
    DIRECTION OUTPUT ;
    USE SIGNAL ;
    PORT
      LAYER M5 ;
        RECT  29.424 0 29.448 0.084 ;
    END
  END o[370]
  PIN o[371]
    DIRECTION OUTPUT ;
    USE SIGNAL ;
    PORT
      LAYER M5 ;
        RECT  29.52 0 29.544 0.084 ;
    END
  END o[371]
  PIN o[372]
    DIRECTION OUTPUT ;
    USE SIGNAL ;
    PORT
      LAYER M5 ;
        RECT  29.568 0 29.592 0.084 ;
    END
  END o[372]
  PIN o[373]
    DIRECTION OUTPUT ;
    USE SIGNAL ;
    PORT
      LAYER M5 ;
        RECT  29.664 0 29.688 0.084 ;
    END
  END o[373]
  PIN o[374]
    DIRECTION OUTPUT ;
    USE SIGNAL ;
    PORT
      LAYER M5 ;
        RECT  29.712 0 29.736 0.084 ;
    END
  END o[374]
  PIN o[375]
    DIRECTION OUTPUT ;
    USE SIGNAL ;
    PORT
      LAYER M5 ;
        RECT  29.808 0 29.832 0.084 ;
    END
  END o[375]
  PIN o[376]
    DIRECTION OUTPUT ;
    USE SIGNAL ;
    PORT
      LAYER M5 ;
        RECT  29.856 0 29.88 0.084 ;
    END
  END o[376]
  PIN o[377]
    DIRECTION OUTPUT ;
    USE SIGNAL ;
    PORT
      LAYER M5 ;
        RECT  29.952 0 29.976 0.084 ;
    END
  END o[377]
  PIN o[378]
    DIRECTION OUTPUT ;
    USE SIGNAL ;
    PORT
      LAYER M5 ;
        RECT  30 0 30.024 0.084 ;
    END
  END o[378]
  PIN o[379]
    DIRECTION OUTPUT ;
    USE SIGNAL ;
    PORT
      LAYER M5 ;
        RECT  30.096 0 30.12 0.084 ;
    END
  END o[379]
  PIN o[37]
    DIRECTION OUTPUT ;
    USE SIGNAL ;
    PORT
      LAYER M5 ;
        RECT  5.136 0 5.16 0.084 ;
    END
  END o[37]
  PIN o[380]
    DIRECTION OUTPUT ;
    USE SIGNAL ;
    PORT
      LAYER M5 ;
        RECT  30.144 0 30.168 0.084 ;
    END
  END o[380]
  PIN o[381]
    DIRECTION OUTPUT ;
    USE SIGNAL ;
    PORT
      LAYER M5 ;
        RECT  30.24 0 30.264 0.084 ;
    END
  END o[381]
  PIN o[382]
    DIRECTION OUTPUT ;
    USE SIGNAL ;
    PORT
      LAYER M5 ;
        RECT  30.336 0 30.36 0.084 ;
    END
  END o[382]
  PIN o[383]
    DIRECTION OUTPUT ;
    USE SIGNAL ;
    PORT
      LAYER M5 ;
        RECT  30.384 0 30.408 0.084 ;
    END
  END o[383]
  PIN o[384]
    DIRECTION OUTPUT ;
    USE SIGNAL ;
    PORT
      LAYER M3 ;
        RECT  30.456 0 30.474 0.038 ;
    END
  END o[384]
  PIN o[385]
    DIRECTION OUTPUT ;
    USE SIGNAL ;
    PORT
      LAYER M3 ;
        RECT  30.528 0 30.546 0.038 ;
    END
  END o[385]
  PIN o[386]
    DIRECTION OUTPUT ;
    USE SIGNAL ;
    PORT
      LAYER M3 ;
        RECT  30.6 0 30.618 0.038 ;
    END
  END o[386]
  PIN o[387]
    DIRECTION OUTPUT ;
    USE SIGNAL ;
    PORT
      LAYER M3 ;
        RECT  30.672 0 30.69 0.038 ;
    END
  END o[387]
  PIN o[388]
    DIRECTION OUTPUT ;
    USE SIGNAL ;
    PORT
      LAYER M3 ;
        RECT  30.744 0 30.762 0.038 ;
    END
  END o[388]
  PIN o[389]
    DIRECTION OUTPUT ;
    USE SIGNAL ;
    PORT
      LAYER M3 ;
        RECT  30.816 0 30.834 0.038 ;
    END
  END o[389]
  PIN o[38]
    DIRECTION OUTPUT ;
    USE SIGNAL ;
    PORT
      LAYER M5 ;
        RECT  5.184 0 5.208 0.084 ;
    END
  END o[38]
  PIN o[390]
    DIRECTION OUTPUT ;
    USE SIGNAL ;
    PORT
      LAYER M3 ;
        RECT  30.888 0 30.906 0.038 ;
    END
  END o[390]
  PIN o[391]
    DIRECTION OUTPUT ;
    USE SIGNAL ;
    PORT
      LAYER M3 ;
        RECT  30.96 0 30.978 0.038 ;
    END
  END o[391]
  PIN o[392]
    DIRECTION OUTPUT ;
    USE SIGNAL ;
    PORT
      LAYER M3 ;
        RECT  31.032 0 31.05 0.038 ;
    END
  END o[392]
  PIN o[393]
    DIRECTION OUTPUT ;
    USE SIGNAL ;
    PORT
      LAYER M3 ;
        RECT  31.104 0 31.122 0.038 ;
    END
  END o[393]
  PIN o[394]
    DIRECTION OUTPUT ;
    USE SIGNAL ;
    PORT
      LAYER M3 ;
        RECT  31.176 0 31.194 0.038 ;
    END
  END o[394]
  PIN o[395]
    DIRECTION OUTPUT ;
    USE SIGNAL ;
    PORT
      LAYER M3 ;
        RECT  31.248 0 31.266 0.038 ;
    END
  END o[395]
  PIN o[396]
    DIRECTION OUTPUT ;
    USE SIGNAL ;
    PORT
      LAYER M3 ;
        RECT  31.32 0 31.338 0.038 ;
    END
  END o[396]
  PIN o[397]
    DIRECTION OUTPUT ;
    USE SIGNAL ;
    PORT
      LAYER M3 ;
        RECT  31.428 0 31.446 0.038 ;
    END
  END o[397]
  PIN o[398]
    DIRECTION OUTPUT ;
    USE SIGNAL ;
    PORT
      LAYER M3 ;
        RECT  31.5 0 31.518 0.038 ;
    END
  END o[398]
  PIN o[399]
    DIRECTION OUTPUT ;
    USE SIGNAL ;
    PORT
      LAYER M3 ;
        RECT  31.572 0 31.59 0.038 ;
    END
  END o[399]
  PIN o[39]
    DIRECTION OUTPUT ;
    USE SIGNAL ;
    PORT
      LAYER M5 ;
        RECT  5.28 0 5.304 0.084 ;
    END
  END o[39]
  PIN o[3]
    DIRECTION OUTPUT ;
    USE SIGNAL ;
    PORT
      LAYER M3 ;
        RECT  2.664 0 2.682 0.038 ;
    END
  END o[3]
  PIN o[400]
    DIRECTION OUTPUT ;
    USE SIGNAL ;
    PORT
      LAYER M3 ;
        RECT  31.644 0 31.662 0.038 ;
    END
  END o[400]
  PIN o[401]
    DIRECTION OUTPUT ;
    USE SIGNAL ;
    PORT
      LAYER M3 ;
        RECT  31.716 0 31.734 0.038 ;
    END
  END o[401]
  PIN o[402]
    DIRECTION OUTPUT ;
    USE SIGNAL ;
    PORT
      LAYER M3 ;
        RECT  31.788 0 31.806 0.038 ;
    END
  END o[402]
  PIN o[403]
    DIRECTION OUTPUT ;
    USE SIGNAL ;
    PORT
      LAYER M3 ;
        RECT  31.86 0 31.878 0.038 ;
    END
  END o[403]
  PIN o[404]
    DIRECTION OUTPUT ;
    USE SIGNAL ;
    PORT
      LAYER M3 ;
        RECT  31.932 0 31.95 0.038 ;
    END
  END o[404]
  PIN o[405]
    DIRECTION OUTPUT ;
    USE SIGNAL ;
    PORT
      LAYER M3 ;
        RECT  32.004 0 32.022 0.038 ;
    END
  END o[405]
  PIN o[406]
    DIRECTION OUTPUT ;
    USE SIGNAL ;
    PORT
      LAYER M3 ;
        RECT  32.076 0 32.094 0.038 ;
    END
  END o[406]
  PIN o[407]
    DIRECTION OUTPUT ;
    USE SIGNAL ;
    PORT
      LAYER M3 ;
        RECT  32.148 0 32.166 0.038 ;
    END
  END o[407]
  PIN o[408]
    DIRECTION OUTPUT ;
    USE SIGNAL ;
    PORT
      LAYER M3 ;
        RECT  32.22 0 32.238 0.038 ;
    END
  END o[408]
  PIN o[409]
    DIRECTION OUTPUT ;
    USE SIGNAL ;
    PORT
      LAYER M3 ;
        RECT  32.292 0 32.31 0.038 ;
    END
  END o[409]
  PIN o[40]
    DIRECTION OUTPUT ;
    USE SIGNAL ;
    PORT
      LAYER M5 ;
        RECT  5.328 0 5.352 0.084 ;
    END
  END o[40]
  PIN o[410]
    DIRECTION OUTPUT ;
    USE SIGNAL ;
    PORT
      LAYER M3 ;
        RECT  32.364 0 32.382 0.038 ;
    END
  END o[410]
  PIN o[411]
    DIRECTION OUTPUT ;
    USE SIGNAL ;
    PORT
      LAYER M3 ;
        RECT  32.436 0 32.454 0.038 ;
    END
  END o[411]
  PIN o[412]
    DIRECTION OUTPUT ;
    USE SIGNAL ;
    PORT
      LAYER M3 ;
        RECT  32.508 0 32.526 0.038 ;
    END
  END o[412]
  PIN o[413]
    DIRECTION OUTPUT ;
    USE SIGNAL ;
    PORT
      LAYER M3 ;
        RECT  32.58 0 32.598 0.038 ;
    END
  END o[413]
  PIN o[414]
    DIRECTION OUTPUT ;
    USE SIGNAL ;
    PORT
      LAYER M3 ;
        RECT  32.652 0 32.67 0.038 ;
    END
  END o[414]
  PIN o[415]
    DIRECTION OUTPUT ;
    USE SIGNAL ;
    PORT
      LAYER M3 ;
        RECT  32.724 0 32.742 0.038 ;
    END
  END o[415]
  PIN o[416]
    DIRECTION OUTPUT ;
    USE SIGNAL ;
    PORT
      LAYER M5 ;
        RECT  32.784 0 32.808 0.084 ;
    END
  END o[416]
  PIN o[417]
    DIRECTION OUTPUT ;
    USE SIGNAL ;
    PORT
      LAYER M5 ;
        RECT  32.88 0 32.904 0.084 ;
    END
  END o[417]
  PIN o[418]
    DIRECTION OUTPUT ;
    USE SIGNAL ;
    PORT
      LAYER M5 ;
        RECT  32.928 0 32.952 0.084 ;
    END
  END o[418]
  PIN o[419]
    DIRECTION OUTPUT ;
    USE SIGNAL ;
    PORT
      LAYER M5 ;
        RECT  33.024 0 33.048 0.084 ;
    END
  END o[419]
  PIN o[41]
    DIRECTION OUTPUT ;
    USE SIGNAL ;
    PORT
      LAYER M5 ;
        RECT  5.424 0 5.448 0.084 ;
    END
  END o[41]
  PIN o[420]
    DIRECTION OUTPUT ;
    USE SIGNAL ;
    PORT
      LAYER M5 ;
        RECT  33.072 0 33.096 0.084 ;
    END
  END o[420]
  PIN o[421]
    DIRECTION OUTPUT ;
    USE SIGNAL ;
    PORT
      LAYER M5 ;
        RECT  33.168 0 33.192 0.084 ;
    END
  END o[421]
  PIN o[422]
    DIRECTION OUTPUT ;
    USE SIGNAL ;
    PORT
      LAYER M5 ;
        RECT  33.216 0 33.24 0.084 ;
    END
  END o[422]
  PIN o[423]
    DIRECTION OUTPUT ;
    USE SIGNAL ;
    PORT
      LAYER M5 ;
        RECT  33.312 0 33.336 0.084 ;
    END
  END o[423]
  PIN o[424]
    DIRECTION OUTPUT ;
    USE SIGNAL ;
    PORT
      LAYER M5 ;
        RECT  33.36 0 33.384 0.084 ;
    END
  END o[424]
  PIN o[425]
    DIRECTION OUTPUT ;
    USE SIGNAL ;
    PORT
      LAYER M5 ;
        RECT  33.456 0 33.48 0.084 ;
    END
  END o[425]
  PIN o[426]
    DIRECTION OUTPUT ;
    USE SIGNAL ;
    PORT
      LAYER M5 ;
        RECT  33.504 0 33.528 0.084 ;
    END
  END o[426]
  PIN o[427]
    DIRECTION OUTPUT ;
    USE SIGNAL ;
    PORT
      LAYER M5 ;
        RECT  33.6 0 33.624 0.084 ;
    END
  END o[427]
  PIN o[428]
    DIRECTION OUTPUT ;
    USE SIGNAL ;
    PORT
      LAYER M5 ;
        RECT  33.648 0 33.672 0.084 ;
    END
  END o[428]
  PIN o[429]
    DIRECTION OUTPUT ;
    USE SIGNAL ;
    PORT
      LAYER M5 ;
        RECT  33.744 0 33.768 0.084 ;
    END
  END o[429]
  PIN o[42]
    DIRECTION OUTPUT ;
    USE SIGNAL ;
    PORT
      LAYER M5 ;
        RECT  5.472 0 5.496 0.084 ;
    END
  END o[42]
  PIN o[430]
    DIRECTION OUTPUT ;
    USE SIGNAL ;
    PORT
      LAYER M5 ;
        RECT  33.84 0 33.864 0.084 ;
    END
  END o[430]
  PIN o[431]
    DIRECTION OUTPUT ;
    USE SIGNAL ;
    PORT
      LAYER M5 ;
        RECT  33.888 0 33.912 0.084 ;
    END
  END o[431]
  PIN o[432]
    DIRECTION OUTPUT ;
    USE SIGNAL ;
    PORT
      LAYER M5 ;
        RECT  33.984 0 34.008 0.084 ;
    END
  END o[432]
  PIN o[433]
    DIRECTION OUTPUT ;
    USE SIGNAL ;
    PORT
      LAYER M5 ;
        RECT  34.032 0 34.056 0.084 ;
    END
  END o[433]
  PIN o[434]
    DIRECTION OUTPUT ;
    USE SIGNAL ;
    PORT
      LAYER M5 ;
        RECT  34.128 0 34.152 0.084 ;
    END
  END o[434]
  PIN o[435]
    DIRECTION OUTPUT ;
    USE SIGNAL ;
    PORT
      LAYER M5 ;
        RECT  34.176 0 34.2 0.084 ;
    END
  END o[435]
  PIN o[436]
    DIRECTION OUTPUT ;
    USE SIGNAL ;
    PORT
      LAYER M5 ;
        RECT  34.272 0 34.296 0.084 ;
    END
  END o[436]
  PIN o[437]
    DIRECTION OUTPUT ;
    USE SIGNAL ;
    PORT
      LAYER M5 ;
        RECT  34.32 0 34.344 0.084 ;
    END
  END o[437]
  PIN o[438]
    DIRECTION OUTPUT ;
    USE SIGNAL ;
    PORT
      LAYER M5 ;
        RECT  34.416 0 34.44 0.084 ;
    END
  END o[438]
  PIN o[439]
    DIRECTION OUTPUT ;
    USE SIGNAL ;
    PORT
      LAYER M5 ;
        RECT  34.464 0 34.488 0.084 ;
    END
  END o[439]
  PIN o[43]
    DIRECTION OUTPUT ;
    USE SIGNAL ;
    PORT
      LAYER M5 ;
        RECT  5.568 0 5.592 0.084 ;
    END
  END o[43]
  PIN o[440]
    DIRECTION OUTPUT ;
    USE SIGNAL ;
    PORT
      LAYER M5 ;
        RECT  34.56 0 34.584 0.084 ;
    END
  END o[440]
  PIN o[441]
    DIRECTION OUTPUT ;
    USE SIGNAL ;
    PORT
      LAYER M5 ;
        RECT  34.608 0 34.632 0.084 ;
    END
  END o[441]
  PIN o[442]
    DIRECTION OUTPUT ;
    USE SIGNAL ;
    PORT
      LAYER M5 ;
        RECT  34.704 0 34.728 0.084 ;
    END
  END o[442]
  PIN o[443]
    DIRECTION OUTPUT ;
    USE SIGNAL ;
    PORT
      LAYER M5 ;
        RECT  34.752 0 34.776 0.084 ;
    END
  END o[443]
  PIN o[444]
    DIRECTION OUTPUT ;
    USE SIGNAL ;
    PORT
      LAYER M5 ;
        RECT  34.848 0 34.872 0.084 ;
    END
  END o[444]
  PIN o[445]
    DIRECTION OUTPUT ;
    USE SIGNAL ;
    PORT
      LAYER M5 ;
        RECT  34.896 0 34.92 0.084 ;
    END
  END o[445]
  PIN o[446]
    DIRECTION OUTPUT ;
    USE SIGNAL ;
    PORT
      LAYER M5 ;
        RECT  34.992 0 35.016 0.084 ;
    END
  END o[446]
  PIN o[447]
    DIRECTION OUTPUT ;
    USE SIGNAL ;
    PORT
      LAYER M5 ;
        RECT  35.04 0 35.064 0.084 ;
    END
  END o[447]
  PIN o[448]
    DIRECTION OUTPUT ;
    USE SIGNAL ;
    PORT
      LAYER M3 ;
        RECT  35.136 0 35.154 0.038 ;
    END
  END o[448]
  PIN o[449]
    DIRECTION OUTPUT ;
    USE SIGNAL ;
    PORT
      LAYER M3 ;
        RECT  35.208 0 35.226 0.038 ;
    END
  END o[449]
  PIN o[44]
    DIRECTION OUTPUT ;
    USE SIGNAL ;
    PORT
      LAYER M5 ;
        RECT  5.616 0 5.64 0.084 ;
    END
  END o[44]
  PIN o[450]
    DIRECTION OUTPUT ;
    USE SIGNAL ;
    PORT
      LAYER M3 ;
        RECT  35.28 0 35.298 0.038 ;
    END
  END o[450]
  PIN o[451]
    DIRECTION OUTPUT ;
    USE SIGNAL ;
    PORT
      LAYER M3 ;
        RECT  35.352 0 35.37 0.038 ;
    END
  END o[451]
  PIN o[452]
    DIRECTION OUTPUT ;
    USE SIGNAL ;
    PORT
      LAYER M3 ;
        RECT  35.424 0 35.442 0.038 ;
    END
  END o[452]
  PIN o[453]
    DIRECTION OUTPUT ;
    USE SIGNAL ;
    PORT
      LAYER M3 ;
        RECT  35.496 0 35.514 0.038 ;
    END
  END o[453]
  PIN o[454]
    DIRECTION OUTPUT ;
    USE SIGNAL ;
    PORT
      LAYER M3 ;
        RECT  35.568 0 35.586 0.038 ;
    END
  END o[454]
  PIN o[455]
    DIRECTION OUTPUT ;
    USE SIGNAL ;
    PORT
      LAYER M3 ;
        RECT  35.64 0 35.658 0.038 ;
    END
  END o[455]
  PIN o[456]
    DIRECTION OUTPUT ;
    USE SIGNAL ;
    PORT
      LAYER M3 ;
        RECT  35.712 0 35.73 0.038 ;
    END
  END o[456]
  PIN o[457]
    DIRECTION OUTPUT ;
    USE SIGNAL ;
    PORT
      LAYER M3 ;
        RECT  35.784 0 35.802 0.038 ;
    END
  END o[457]
  PIN o[458]
    DIRECTION OUTPUT ;
    USE SIGNAL ;
    PORT
      LAYER M3 ;
        RECT  35.856 0 35.874 0.038 ;
    END
  END o[458]
  PIN o[459]
    DIRECTION OUTPUT ;
    USE SIGNAL ;
    PORT
      LAYER M3 ;
        RECT  35.928 0 35.946 0.038 ;
    END
  END o[459]
  PIN o[45]
    DIRECTION OUTPUT ;
    USE SIGNAL ;
    PORT
      LAYER M5 ;
        RECT  5.712 0 5.736 0.084 ;
    END
  END o[45]
  PIN o[460]
    DIRECTION OUTPUT ;
    USE SIGNAL ;
    PORT
      LAYER M3 ;
        RECT  36 0 36.018 0.038 ;
    END
  END o[460]
  PIN o[461]
    DIRECTION OUTPUT ;
    USE SIGNAL ;
    PORT
      LAYER M3 ;
        RECT  36.072 0 36.09 0.038 ;
    END
  END o[461]
  PIN o[462]
    DIRECTION OUTPUT ;
    USE SIGNAL ;
    PORT
      LAYER M3 ;
        RECT  36.144 0 36.162 0.038 ;
    END
  END o[462]
  PIN o[463]
    DIRECTION OUTPUT ;
    USE SIGNAL ;
    PORT
      LAYER M3 ;
        RECT  36.216 0 36.234 0.038 ;
    END
  END o[463]
  PIN o[464]
    DIRECTION OUTPUT ;
    USE SIGNAL ;
    PORT
      LAYER M3 ;
        RECT  36.288 0 36.306 0.038 ;
    END
  END o[464]
  PIN o[465]
    DIRECTION OUTPUT ;
    USE SIGNAL ;
    PORT
      LAYER M3 ;
        RECT  36.36 0 36.378 0.038 ;
    END
  END o[465]
  PIN o[466]
    DIRECTION OUTPUT ;
    USE SIGNAL ;
    PORT
      LAYER M3 ;
        RECT  36.432 0 36.45 0.038 ;
    END
  END o[466]
  PIN o[467]
    DIRECTION OUTPUT ;
    USE SIGNAL ;
    PORT
      LAYER M3 ;
        RECT  36.504 0 36.522 0.038 ;
    END
  END o[467]
  PIN o[468]
    DIRECTION OUTPUT ;
    USE SIGNAL ;
    PORT
      LAYER M3 ;
        RECT  36.576 0 36.594 0.038 ;
    END
  END o[468]
  PIN o[469]
    DIRECTION OUTPUT ;
    USE SIGNAL ;
    PORT
      LAYER M3 ;
        RECT  36.684 0 36.702 0.038 ;
    END
  END o[469]
  PIN o[46]
    DIRECTION OUTPUT ;
    USE SIGNAL ;
    PORT
      LAYER M5 ;
        RECT  5.76 0 5.784 0.084 ;
    END
  END o[46]
  PIN o[470]
    DIRECTION OUTPUT ;
    USE SIGNAL ;
    PORT
      LAYER M3 ;
        RECT  36.756 0 36.774 0.038 ;
    END
  END o[470]
  PIN o[471]
    DIRECTION OUTPUT ;
    USE SIGNAL ;
    PORT
      LAYER M3 ;
        RECT  36.828 0 36.846 0.038 ;
    END
  END o[471]
  PIN o[472]
    DIRECTION OUTPUT ;
    USE SIGNAL ;
    PORT
      LAYER M3 ;
        RECT  36.9 0 36.918 0.038 ;
    END
  END o[472]
  PIN o[473]
    DIRECTION OUTPUT ;
    USE SIGNAL ;
    PORT
      LAYER M3 ;
        RECT  36.972 0 36.99 0.038 ;
    END
  END o[473]
  PIN o[474]
    DIRECTION OUTPUT ;
    USE SIGNAL ;
    PORT
      LAYER M3 ;
        RECT  37.044 0 37.062 0.038 ;
    END
  END o[474]
  PIN o[475]
    DIRECTION OUTPUT ;
    USE SIGNAL ;
    PORT
      LAYER M3 ;
        RECT  37.116 0 37.134 0.038 ;
    END
  END o[475]
  PIN o[476]
    DIRECTION OUTPUT ;
    USE SIGNAL ;
    PORT
      LAYER M3 ;
        RECT  37.188 0 37.206 0.038 ;
    END
  END o[476]
  PIN o[477]
    DIRECTION OUTPUT ;
    USE SIGNAL ;
    PORT
      LAYER M3 ;
        RECT  37.26 0 37.278 0.038 ;
    END
  END o[477]
  PIN o[478]
    DIRECTION OUTPUT ;
    USE SIGNAL ;
    PORT
      LAYER M3 ;
        RECT  37.332 0 37.35 0.038 ;
    END
  END o[478]
  PIN o[479]
    DIRECTION OUTPUT ;
    USE SIGNAL ;
    PORT
      LAYER M3 ;
        RECT  37.404 0 37.422 0.038 ;
    END
  END o[479]
  PIN o[47]
    DIRECTION OUTPUT ;
    USE SIGNAL ;
    PORT
      LAYER M5 ;
        RECT  5.856 0 5.88 0.084 ;
    END
  END o[47]
  PIN o[480]
    DIRECTION OUTPUT ;
    USE SIGNAL ;
    PORT
      LAYER M5 ;
        RECT  37.488 0 37.512 0.084 ;
    END
  END o[480]
  PIN o[481]
    DIRECTION OUTPUT ;
    USE SIGNAL ;
    PORT
      LAYER M5 ;
        RECT  37.536 0 37.56 0.084 ;
    END
  END o[481]
  PIN o[482]
    DIRECTION OUTPUT ;
    USE SIGNAL ;
    PORT
      LAYER M5 ;
        RECT  37.632 0 37.656 0.084 ;
    END
  END o[482]
  PIN o[483]
    DIRECTION OUTPUT ;
    USE SIGNAL ;
    PORT
      LAYER M5 ;
        RECT  37.68 0 37.704 0.084 ;
    END
  END o[483]
  PIN o[484]
    DIRECTION OUTPUT ;
    USE SIGNAL ;
    PORT
      LAYER M5 ;
        RECT  37.776 0 37.8 0.084 ;
    END
  END o[484]
  PIN o[485]
    DIRECTION OUTPUT ;
    USE SIGNAL ;
    PORT
      LAYER M5 ;
        RECT  37.824 0 37.848 0.084 ;
    END
  END o[485]
  PIN o[486]
    DIRECTION OUTPUT ;
    USE SIGNAL ;
    PORT
      LAYER M5 ;
        RECT  37.92 0 37.944 0.084 ;
    END
  END o[486]
  PIN o[487]
    DIRECTION OUTPUT ;
    USE SIGNAL ;
    PORT
      LAYER M5 ;
        RECT  37.968 0 37.992 0.084 ;
    END
  END o[487]
  PIN o[488]
    DIRECTION OUTPUT ;
    USE SIGNAL ;
    PORT
      LAYER M5 ;
        RECT  38.064 0 38.088 0.084 ;
    END
  END o[488]
  PIN o[489]
    DIRECTION OUTPUT ;
    USE SIGNAL ;
    PORT
      LAYER M5 ;
        RECT  38.112 0 38.136 0.084 ;
    END
  END o[489]
  PIN o[48]
    DIRECTION OUTPUT ;
    USE SIGNAL ;
    PORT
      LAYER M5 ;
        RECT  5.952 0 5.976 0.084 ;
    END
  END o[48]
  PIN o[490]
    DIRECTION OUTPUT ;
    USE SIGNAL ;
    PORT
      LAYER M5 ;
        RECT  38.208 0 38.232 0.084 ;
    END
  END o[490]
  PIN o[491]
    DIRECTION OUTPUT ;
    USE SIGNAL ;
    PORT
      LAYER M5 ;
        RECT  38.256 0 38.28 0.084 ;
    END
  END o[491]
  PIN o[492]
    DIRECTION OUTPUT ;
    USE SIGNAL ;
    PORT
      LAYER M5 ;
        RECT  38.352 0 38.376 0.084 ;
    END
  END o[492]
  PIN o[493]
    DIRECTION OUTPUT ;
    USE SIGNAL ;
    PORT
      LAYER M5 ;
        RECT  38.4 0 38.424 0.084 ;
    END
  END o[493]
  PIN o[494]
    DIRECTION OUTPUT ;
    USE SIGNAL ;
    PORT
      LAYER M5 ;
        RECT  38.496 0 38.52 0.084 ;
    END
  END o[494]
  PIN o[495]
    DIRECTION OUTPUT ;
    USE SIGNAL ;
    PORT
      LAYER M5 ;
        RECT  38.544 0 38.568 0.084 ;
    END
  END o[495]
  PIN o[496]
    DIRECTION OUTPUT ;
    USE SIGNAL ;
    PORT
      LAYER M5 ;
        RECT  38.64 0 38.664 0.084 ;
    END
  END o[496]
  PIN o[497]
    DIRECTION OUTPUT ;
    USE SIGNAL ;
    PORT
      LAYER M5 ;
        RECT  38.688 0 38.712 0.084 ;
    END
  END o[497]
  PIN o[498]
    DIRECTION OUTPUT ;
    USE SIGNAL ;
    PORT
      LAYER M5 ;
        RECT  38.784 0 38.808 0.084 ;
    END
  END o[498]
  PIN o[499]
    DIRECTION OUTPUT ;
    USE SIGNAL ;
    PORT
      LAYER M5 ;
        RECT  38.832 0 38.856 0.084 ;
    END
  END o[499]
  PIN o[49]
    DIRECTION OUTPUT ;
    USE SIGNAL ;
    PORT
      LAYER M5 ;
        RECT  6 0 6.024 0.084 ;
    END
  END o[49]
  PIN o[4]
    DIRECTION OUTPUT ;
    USE SIGNAL ;
    PORT
      LAYER M3 ;
        RECT  2.736 0 2.754 0.038 ;
    END
  END o[4]
  PIN o[500]
    DIRECTION OUTPUT ;
    USE SIGNAL ;
    PORT
      LAYER M5 ;
        RECT  38.928 0 38.952 0.084 ;
    END
  END o[500]
  PIN o[501]
    DIRECTION OUTPUT ;
    USE SIGNAL ;
    PORT
      LAYER M5 ;
        RECT  38.976 0 39 0.084 ;
    END
  END o[501]
  PIN o[502]
    DIRECTION OUTPUT ;
    USE SIGNAL ;
    PORT
      LAYER M5 ;
        RECT  39.072 0 39.096 0.084 ;
    END
  END o[502]
  PIN o[503]
    DIRECTION OUTPUT ;
    USE SIGNAL ;
    PORT
      LAYER M5 ;
        RECT  39.168 0 39.192 0.084 ;
    END
  END o[503]
  PIN o[504]
    DIRECTION OUTPUT ;
    USE SIGNAL ;
    PORT
      LAYER M5 ;
        RECT  39.216 0 39.24 0.084 ;
    END
  END o[504]
  PIN o[505]
    DIRECTION OUTPUT ;
    USE SIGNAL ;
    PORT
      LAYER M5 ;
        RECT  39.312 0 39.336 0.084 ;
    END
  END o[505]
  PIN o[506]
    DIRECTION OUTPUT ;
    USE SIGNAL ;
    PORT
      LAYER M5 ;
        RECT  39.36 0 39.384 0.084 ;
    END
  END o[506]
  PIN o[507]
    DIRECTION OUTPUT ;
    USE SIGNAL ;
    PORT
      LAYER M5 ;
        RECT  39.456 0 39.48 0.084 ;
    END
  END o[507]
  PIN o[508]
    DIRECTION OUTPUT ;
    USE SIGNAL ;
    PORT
      LAYER M5 ;
        RECT  39.504 0 39.528 0.084 ;
    END
  END o[508]
  PIN o[509]
    DIRECTION OUTPUT ;
    USE SIGNAL ;
    PORT
      LAYER M5 ;
        RECT  39.6 0 39.624 0.084 ;
    END
  END o[509]
  PIN o[50]
    DIRECTION OUTPUT ;
    USE SIGNAL ;
    PORT
      LAYER M5 ;
        RECT  6.096 0 6.12 0.084 ;
    END
  END o[50]
  PIN o[510]
    DIRECTION OUTPUT ;
    USE SIGNAL ;
    PORT
      LAYER M5 ;
        RECT  39.648 0 39.672 0.084 ;
    END
  END o[510]
  PIN o[511]
    DIRECTION OUTPUT ;
    USE SIGNAL ;
    PORT
      LAYER M5 ;
        RECT  39.744 0 39.768 0.084 ;
    END
  END o[511]
  PIN o[512]
    DIRECTION OUTPUT ;
    USE SIGNAL ;
    PORT
      LAYER M3 ;
        RECT  39.816 0 39.834 0.038 ;
    END
  END o[512]
  PIN o[513]
    DIRECTION OUTPUT ;
    USE SIGNAL ;
    PORT
      LAYER M3 ;
        RECT  39.888 0 39.906 0.038 ;
    END
  END o[513]
  PIN o[514]
    DIRECTION OUTPUT ;
    USE SIGNAL ;
    PORT
      LAYER M3 ;
        RECT  39.96 0 39.978 0.038 ;
    END
  END o[514]
  PIN o[515]
    DIRECTION OUTPUT ;
    USE SIGNAL ;
    PORT
      LAYER M3 ;
        RECT  40.032 0 40.05 0.038 ;
    END
  END o[515]
  PIN o[516]
    DIRECTION OUTPUT ;
    USE SIGNAL ;
    PORT
      LAYER M3 ;
        RECT  40.104 0 40.122 0.038 ;
    END
  END o[516]
  PIN o[517]
    DIRECTION OUTPUT ;
    USE SIGNAL ;
    PORT
      LAYER M3 ;
        RECT  40.176 0 40.194 0.038 ;
    END
  END o[517]
  PIN o[518]
    DIRECTION OUTPUT ;
    USE SIGNAL ;
    PORT
      LAYER M3 ;
        RECT  40.248 0 40.266 0.038 ;
    END
  END o[518]
  PIN o[519]
    DIRECTION OUTPUT ;
    USE SIGNAL ;
    PORT
      LAYER M3 ;
        RECT  40.32 0 40.338 0.038 ;
    END
  END o[519]
  PIN o[51]
    DIRECTION OUTPUT ;
    USE SIGNAL ;
    PORT
      LAYER M5 ;
        RECT  6.144 0 6.168 0.084 ;
    END
  END o[51]
  PIN o[520]
    DIRECTION OUTPUT ;
    USE SIGNAL ;
    PORT
      LAYER M3 ;
        RECT  40.392 0 40.41 0.038 ;
    END
  END o[520]
  PIN o[521]
    DIRECTION OUTPUT ;
    USE SIGNAL ;
    PORT
      LAYER M3 ;
        RECT  40.464 0 40.482 0.038 ;
    END
  END o[521]
  PIN o[522]
    DIRECTION OUTPUT ;
    USE SIGNAL ;
    PORT
      LAYER M3 ;
        RECT  40.536 0 40.554 0.038 ;
    END
  END o[522]
  PIN o[523]
    DIRECTION OUTPUT ;
    USE SIGNAL ;
    PORT
      LAYER M3 ;
        RECT  40.608 0 40.626 0.038 ;
    END
  END o[523]
  PIN o[524]
    DIRECTION OUTPUT ;
    USE SIGNAL ;
    PORT
      LAYER M3 ;
        RECT  40.68 0 40.698 0.038 ;
    END
  END o[524]
  PIN o[525]
    DIRECTION OUTPUT ;
    USE SIGNAL ;
    PORT
      LAYER M3 ;
        RECT  40.752 0 40.77 0.038 ;
    END
  END o[525]
  PIN o[52]
    DIRECTION OUTPUT ;
    USE SIGNAL ;
    PORT
      LAYER M5 ;
        RECT  6.24 0 6.264 0.084 ;
    END
  END o[52]
  PIN o[53]
    DIRECTION OUTPUT ;
    USE SIGNAL ;
    PORT
      LAYER M5 ;
        RECT  6.288 0 6.312 0.084 ;
    END
  END o[53]
  PIN o[54]
    DIRECTION OUTPUT ;
    USE SIGNAL ;
    PORT
      LAYER M5 ;
        RECT  6.384 0 6.408 0.084 ;
    END
  END o[54]
  PIN o[55]
    DIRECTION OUTPUT ;
    USE SIGNAL ;
    PORT
      LAYER M5 ;
        RECT  6.432 0 6.456 0.084 ;
    END
  END o[55]
  PIN o[56]
    DIRECTION OUTPUT ;
    USE SIGNAL ;
    PORT
      LAYER M5 ;
        RECT  6.528 0 6.552 0.084 ;
    END
  END o[56]
  PIN o[57]
    DIRECTION OUTPUT ;
    USE SIGNAL ;
    PORT
      LAYER M5 ;
        RECT  6.576 0 6.6 0.084 ;
    END
  END o[57]
  PIN o[58]
    DIRECTION OUTPUT ;
    USE SIGNAL ;
    PORT
      LAYER M5 ;
        RECT  6.672 0 6.696 0.084 ;
    END
  END o[58]
  PIN o[59]
    DIRECTION OUTPUT ;
    USE SIGNAL ;
    PORT
      LAYER M5 ;
        RECT  6.72 0 6.744 0.084 ;
    END
  END o[59]
  PIN o[5]
    DIRECTION OUTPUT ;
    USE SIGNAL ;
    PORT
      LAYER M3 ;
        RECT  2.808 0 2.826 0.038 ;
    END
  END o[5]
  PIN o[60]
    DIRECTION OUTPUT ;
    USE SIGNAL ;
    PORT
      LAYER M5 ;
        RECT  6.816 0 6.84 0.084 ;
    END
  END o[60]
  PIN o[61]
    DIRECTION OUTPUT ;
    USE SIGNAL ;
    PORT
      LAYER M5 ;
        RECT  6.864 0 6.888 0.084 ;
    END
  END o[61]
  PIN o[62]
    DIRECTION OUTPUT ;
    USE SIGNAL ;
    PORT
      LAYER M5 ;
        RECT  6.96 0 6.984 0.084 ;
    END
  END o[62]
  PIN o[63]
    DIRECTION OUTPUT ;
    USE SIGNAL ;
    PORT
      LAYER M5 ;
        RECT  7.008 0 7.032 0.084 ;
    END
  END o[63]
  PIN o[64]
    DIRECTION OUTPUT ;
    USE SIGNAL ;
    PORT
      LAYER M3 ;
        RECT  7.092 0 7.11 0.038 ;
    END
  END o[64]
  PIN o[65]
    DIRECTION OUTPUT ;
    USE SIGNAL ;
    PORT
      LAYER M3 ;
        RECT  7.164 0 7.182 0.038 ;
    END
  END o[65]
  PIN o[66]
    DIRECTION OUTPUT ;
    USE SIGNAL ;
    PORT
      LAYER M3 ;
        RECT  7.236 0 7.254 0.038 ;
    END
  END o[66]
  PIN o[67]
    DIRECTION OUTPUT ;
    USE SIGNAL ;
    PORT
      LAYER M3 ;
        RECT  7.308 0 7.326 0.038 ;
    END
  END o[67]
  PIN o[68]
    DIRECTION OUTPUT ;
    USE SIGNAL ;
    PORT
      LAYER M3 ;
        RECT  7.38 0 7.398 0.038 ;
    END
  END o[68]
  PIN o[69]
    DIRECTION OUTPUT ;
    USE SIGNAL ;
    PORT
      LAYER M3 ;
        RECT  7.452 0 7.47 0.038 ;
    END
  END o[69]
  PIN o[6]
    DIRECTION OUTPUT ;
    USE SIGNAL ;
    PORT
      LAYER M3 ;
        RECT  2.88 0 2.898 0.038 ;
    END
  END o[6]
  PIN o[70]
    DIRECTION OUTPUT ;
    USE SIGNAL ;
    PORT
      LAYER M3 ;
        RECT  7.524 0 7.542 0.038 ;
    END
  END o[70]
  PIN o[71]
    DIRECTION OUTPUT ;
    USE SIGNAL ;
    PORT
      LAYER M3 ;
        RECT  7.596 0 7.614 0.038 ;
    END
  END o[71]
  PIN o[72]
    DIRECTION OUTPUT ;
    USE SIGNAL ;
    PORT
      LAYER M3 ;
        RECT  7.668 0 7.686 0.038 ;
    END
  END o[72]
  PIN o[73]
    DIRECTION OUTPUT ;
    USE SIGNAL ;
    PORT
      LAYER M3 ;
        RECT  7.74 0 7.758 0.038 ;
    END
  END o[73]
  PIN o[74]
    DIRECTION OUTPUT ;
    USE SIGNAL ;
    PORT
      LAYER M3 ;
        RECT  7.848 0 7.866 0.038 ;
    END
  END o[74]
  PIN o[75]
    DIRECTION OUTPUT ;
    USE SIGNAL ;
    PORT
      LAYER M3 ;
        RECT  7.92 0 7.938 0.038 ;
    END
  END o[75]
  PIN o[76]
    DIRECTION OUTPUT ;
    USE SIGNAL ;
    PORT
      LAYER M3 ;
        RECT  7.992 0 8.01 0.038 ;
    END
  END o[76]
  PIN o[77]
    DIRECTION OUTPUT ;
    USE SIGNAL ;
    PORT
      LAYER M3 ;
        RECT  8.064 0 8.082 0.038 ;
    END
  END o[77]
  PIN o[78]
    DIRECTION OUTPUT ;
    USE SIGNAL ;
    PORT
      LAYER M3 ;
        RECT  8.136 0 8.154 0.038 ;
    END
  END o[78]
  PIN o[79]
    DIRECTION OUTPUT ;
    USE SIGNAL ;
    PORT
      LAYER M3 ;
        RECT  8.208 0 8.226 0.038 ;
    END
  END o[79]
  PIN o[7]
    DIRECTION OUTPUT ;
    USE SIGNAL ;
    PORT
      LAYER M3 ;
        RECT  2.952 0 2.97 0.038 ;
    END
  END o[7]
  PIN o[80]
    DIRECTION OUTPUT ;
    USE SIGNAL ;
    PORT
      LAYER M3 ;
        RECT  8.28 0 8.298 0.038 ;
    END
  END o[80]
  PIN o[81]
    DIRECTION OUTPUT ;
    USE SIGNAL ;
    PORT
      LAYER M3 ;
        RECT  8.352 0 8.37 0.038 ;
    END
  END o[81]
  PIN o[82]
    DIRECTION OUTPUT ;
    USE SIGNAL ;
    PORT
      LAYER M3 ;
        RECT  8.424 0 8.442 0.038 ;
    END
  END o[82]
  PIN o[83]
    DIRECTION OUTPUT ;
    USE SIGNAL ;
    PORT
      LAYER M3 ;
        RECT  8.496 0 8.514 0.038 ;
    END
  END o[83]
  PIN o[84]
    DIRECTION OUTPUT ;
    USE SIGNAL ;
    PORT
      LAYER M3 ;
        RECT  8.568 0 8.586 0.038 ;
    END
  END o[84]
  PIN o[85]
    DIRECTION OUTPUT ;
    USE SIGNAL ;
    PORT
      LAYER M3 ;
        RECT  8.64 0 8.658 0.038 ;
    END
  END o[85]
  PIN o[86]
    DIRECTION OUTPUT ;
    USE SIGNAL ;
    PORT
      LAYER M3 ;
        RECT  8.712 0 8.73 0.038 ;
    END
  END o[86]
  PIN o[87]
    DIRECTION OUTPUT ;
    USE SIGNAL ;
    PORT
      LAYER M3 ;
        RECT  8.784 0 8.802 0.038 ;
    END
  END o[87]
  PIN o[88]
    DIRECTION OUTPUT ;
    USE SIGNAL ;
    PORT
      LAYER M3 ;
        RECT  8.856 0 8.874 0.038 ;
    END
  END o[88]
  PIN o[89]
    DIRECTION OUTPUT ;
    USE SIGNAL ;
    PORT
      LAYER M3 ;
        RECT  8.928 0 8.946 0.038 ;
    END
  END o[89]
  PIN o[8]
    DIRECTION OUTPUT ;
    USE SIGNAL ;
    PORT
      LAYER M3 ;
        RECT  3.024 0 3.042 0.038 ;
    END
  END o[8]
  PIN o[90]
    DIRECTION OUTPUT ;
    USE SIGNAL ;
    PORT
      LAYER M3 ;
        RECT  9 0 9.018 0.038 ;
    END
  END o[90]
  PIN o[91]
    DIRECTION OUTPUT ;
    USE SIGNAL ;
    PORT
      LAYER M3 ;
        RECT  9.072 0 9.09 0.038 ;
    END
  END o[91]
  PIN o[92]
    DIRECTION OUTPUT ;
    USE SIGNAL ;
    PORT
      LAYER M3 ;
        RECT  9.144 0 9.162 0.038 ;
    END
  END o[92]
  PIN o[93]
    DIRECTION OUTPUT ;
    USE SIGNAL ;
    PORT
      LAYER M3 ;
        RECT  9.216 0 9.234 0.038 ;
    END
  END o[93]
  PIN o[94]
    DIRECTION OUTPUT ;
    USE SIGNAL ;
    PORT
      LAYER M3 ;
        RECT  9.288 0 9.306 0.038 ;
    END
  END o[94]
  PIN o[95]
    DIRECTION OUTPUT ;
    USE SIGNAL ;
    PORT
      LAYER M3 ;
        RECT  9.36 0 9.378 0.038 ;
    END
  END o[95]
  PIN o[96]
    DIRECTION OUTPUT ;
    USE SIGNAL ;
    PORT
      LAYER M5 ;
        RECT  9.456 0 9.48 0.084 ;
    END
  END o[96]
  PIN o[97]
    DIRECTION OUTPUT ;
    USE SIGNAL ;
    PORT
      LAYER M5 ;
        RECT  9.504 0 9.528 0.084 ;
    END
  END o[97]
  PIN o[98]
    DIRECTION OUTPUT ;
    USE SIGNAL ;
    PORT
      LAYER M5 ;
        RECT  9.6 0 9.624 0.084 ;
    END
  END o[98]
  PIN o[99]
    DIRECTION OUTPUT ;
    USE SIGNAL ;
    PORT
      LAYER M5 ;
        RECT  9.648 0 9.672 0.084 ;
    END
  END o[99]
  PIN o[9]
    DIRECTION OUTPUT ;
    USE SIGNAL ;
    PORT
      LAYER M3 ;
        RECT  3.096 0 3.114 0.038 ;
    END
  END o[9]
  PIN VDD
    DIRECTION INOUT ;
    USE POWER ;
    PORT
      LAYER M5 ;
        RECT  40.392 2.151 40.512 17.289 ;
        RECT  34.992 2.151 35.112 17.289 ;
        RECT  29.592 2.151 29.712 17.289 ;
        RECT  24.192 2.151 24.312 17.289 ;
        RECT  18.792 2.151 18.912 17.289 ;
        RECT  13.392 2.151 13.512 17.289 ;
        RECT  7.992 2.151 8.112 17.289 ;
        RECT  2.592 2.151 2.712 17.289 ;
    END
  END VDD
  PIN VSS
    DIRECTION INOUT ;
    USE GROUND ;
    PORT
      LAYER M5 ;
        RECT  40.2 2.137 40.32 17.303 ;
        RECT  34.8 2.137 34.92 17.303 ;
        RECT  29.4 2.137 29.52 17.303 ;
        RECT  24 2.137 24.12 17.303 ;
        RECT  18.6 2.137 18.72 17.303 ;
        RECT  13.2 2.137 13.32 17.303 ;
        RECT  7.8 2.137 7.92 17.303 ;
        RECT  2.4 2.137 2.52 17.303 ;
    END
  END VSS
  # OT_OBS_CLOSED layer=M5 d_um=1.536 added=108
  OBS
    LAYER RVTN ;
     RECT  2.16 2.16 41.04 2.295 ;
     RECT  2.16 2.565 41.04 2.835 ;
     RECT  2.16 3.105 41.04 3.375 ;
     RECT  2.16 3.645 41.04 3.915 ;
     RECT  2.16 4.185 41.04 4.455 ;
     RECT  2.16 4.725 41.04 4.995 ;
     RECT  2.16 5.265 41.04 5.535 ;
     RECT  2.16 5.805 41.04 6.075 ;
     RECT  2.16 6.345 41.04 6.615 ;
     RECT  2.16 6.885 41.04 7.155 ;
     RECT  2.16 7.425 41.04 7.695 ;
     RECT  2.16 7.965 41.04 8.235 ;
     RECT  2.16 8.505 41.04 8.775 ;
     RECT  2.16 9.045 41.04 9.315 ;
     RECT  2.16 9.585 41.04 9.855 ;
     RECT  2.16 10.125 41.04 10.395 ;
     RECT  2.16 10.665 41.04 10.935 ;
     RECT  2.16 11.205 41.04 11.475 ;
     RECT  2.16 11.745 41.04 12.015 ;
     RECT  2.16 12.285 41.04 12.555 ;
     RECT  2.16 12.825 41.04 13.095 ;
     RECT  2.16 13.365 41.04 13.635 ;
     RECT  2.16 13.905 41.04 14.175 ;
     RECT  2.16 14.445 41.04 14.715 ;
     RECT  2.16 14.985 41.04 15.255 ;
     RECT  2.16 15.525 41.04 15.795 ;
     RECT  2.16 16.065 41.04 16.335 ;
     RECT  2.16 16.605 41.04 16.875 ;
     RECT  2.16 17.145 41.04 17.28 ;
    LAYER RVTP ;
     RECT  2.16 2.295 41.04 2.565 ;
     RECT  2.16 2.835 41.04 3.105 ;
     RECT  2.16 3.375 41.04 3.645 ;
     RECT  2.16 3.915 41.04 4.185 ;
     RECT  2.16 4.455 41.04 4.725 ;
     RECT  2.16 4.995 41.04 5.265 ;
     RECT  2.16 5.535 41.04 5.805 ;
     RECT  2.16 6.075 41.04 6.345 ;
     RECT  2.16 6.615 41.04 6.885 ;
     RECT  2.16 7.155 41.04 7.425 ;
     RECT  2.16 7.695 41.04 7.965 ;
     RECT  2.16 8.235 41.04 8.505 ;
     RECT  2.16 8.775 41.04 9.045 ;
     RECT  2.16 9.315 41.04 9.585 ;
     RECT  2.16 9.855 41.04 10.125 ;
     RECT  2.16 10.395 41.04 10.665 ;
     RECT  2.16 10.935 41.04 11.205 ;
     RECT  2.16 11.475 41.04 11.745 ;
     RECT  2.16 12.015 41.04 12.285 ;
     RECT  2.16 12.555 41.04 12.825 ;
     RECT  2.16 13.095 41.04 13.365 ;
     RECT  2.16 13.635 41.04 13.905 ;
     RECT  2.16 14.175 41.04 14.445 ;
     RECT  2.16 14.715 41.04 14.985 ;
     RECT  2.16 15.255 41.04 15.525 ;
     RECT  2.16 15.795 41.04 16.065 ;
     RECT  2.16 16.335 41.04 16.605 ;
     RECT  2.16 16.875 41.04 17.145 ;
    LAYER M1 ;
     RECT  2.16 2.151 41.04 17.289 ;
    LAYER M2 ;
     RECT  2.16 2.151 2.335 17.289 ;
     RECT  2.335 2.151 2.435 17.37 ;
     RECT  2.371 18.81 2.507 18.828 ;
     RECT  2.371 1.224 2.551 1.242 ;
     RECT  2.435 2.151 2.659 17.289 ;
     RECT  2.371 0.036 2.731 0.054 ;
     RECT  2.731 0.036 2.839 0.126 ;
     RECT  2.839 0.036 2.975 0.198 ;
     RECT  2.659 2.106 3.083 17.289 ;
     RECT  2.551 1.152 3.335 1.242 ;
     RECT  3.335 1.224 3.407 1.242 ;
     RECT  3.523 18.738 3.595 18.756 ;
     RECT  3.595 18.702 3.703 18.756 ;
     RECT  2.975 0.036 3.811 0.162 ;
     RECT  3.703 18.702 4.127 18.792 ;
     RECT  3.083 2.151 4.171 17.289 ;
     RECT  4.127 18.774 4.235 18.792 ;
     RECT  3.811 0.036 4.559 0.198 ;
     RECT  4.171 1.728 4.559 17.289 ;
     RECT  4.559 0.036 4.811 0.054 ;
     RECT  7.159 0.036 7.231 0.054 ;
     RECT  4.559 2.151 7.519 17.289 ;
     RECT  7.519 1.728 7.627 17.289 ;
     RECT  7.627 1.728 7.943 17.442 ;
     RECT  7.123 18.81 7.987 18.828 ;
     RECT  7.987 18.774 8.059 18.828 ;
     RECT  8.059 18.738 8.159 18.828 ;
     RECT  8.159 18.774 8.239 18.828 ;
     RECT  8.239 18.774 8.375 18.954 ;
     RECT  8.375 18.846 8.447 18.954 ;
     RECT  7.231 0.036 8.635 0.198 ;
     RECT  8.635 0.036 9.023 0.234 ;
     RECT  9.023 0.036 9.203 0.054 ;
     RECT  7.943 1.728 9.635 17.289 ;
     RECT  9.635 2.106 9.887 17.289 ;
     RECT  9.859 1.224 9.931 1.242 ;
     RECT  9.931 1.152 9.959 1.242 ;
     RECT  9.959 1.152 10.823 1.17 ;
     RECT  11.767 0.108 11.839 0.126 ;
     RECT  9.887 2.151 11.947 17.289 ;
     RECT  11.767 1.152 11.983 1.17 ;
     RECT  11.947 2.106 11.983 17.289 ;
     RECT  11.839 0.036 12.163 0.126 ;
     RECT  12.163 0.036 12.739 0.162 ;
     RECT  11.983 1.152 12.803 17.289 ;
     RECT  12.739 0.036 12.983 0.198 ;
     RECT  12.803 1.152 13.055 1.359 ;
     RECT  13.135 18.81 13.271 18.828 ;
     RECT  13.315 18.702 13.595 18.792 ;
     RECT  12.983 0.108 13.631 0.198 ;
     RECT  13.595 18.702 13.667 18.72 ;
     RECT  13.631 0.108 13.819 0.126 ;
     RECT  13.819 0.036 14.027 0.126 ;
     RECT  14.027 0.108 14.207 0.126 ;
     RECT  15.223 1.152 15.323 1.17 ;
     RECT  16.051 1.224 16.123 1.242 ;
     RECT  16.123 1.152 16.259 1.242 ;
     RECT  16.375 18.774 16.519 18.792 ;
     RECT  12.803 2.151 16.663 17.289 ;
     RECT  16.195 0.036 16.915 0.054 ;
     RECT  16.663 1.728 16.987 17.289 ;
     RECT  16.519 18.702 17.051 18.792 ;
     RECT  16.915 0.036 17.311 0.126 ;
     RECT  16.987 1.152 17.555 17.289 ;
     RECT  17.555 1.152 17.591 1.278 ;
     RECT  17.555 2.034 17.995 17.289 ;
     RECT  17.311 0.036 18.247 0.198 ;
     RECT  17.591 1.152 18.427 1.242 ;
     RECT  17.995 2.034 18.427 17.712 ;
     RECT  18.427 1.152 18.455 17.712 ;
     RECT  18.247 0.036 18.527 0.279 ;
     RECT  18.527 0.036 18.599 0.198 ;
     RECT  18.455 1.152 18.671 17.37 ;
     RECT  17.815 18.774 18.743 18.792 ;
     RECT  18.671 1.152 18.779 17.289 ;
     RECT  18.599 0.036 18.815 0.054 ;
     RECT  18.779 2.034 19.247 17.289 ;
     RECT  18.779 1.152 19.535 1.242 ;
     RECT  19.535 1.224 19.643 1.242 ;
     RECT  19.247 2.151 20.479 17.289 ;
     RECT  20.623 1.152 20.867 1.17 ;
     RECT  21.163 18.774 21.343 18.792 ;
     RECT  20.479 2.106 21.415 17.289 ;
     RECT  21.343 18.702 21.443 18.792 ;
     RECT  21.379 0.036 21.919 0.054 ;
     RECT  21.919 0.036 22.063 0.126 ;
     RECT  21.443 18.774 22.387 18.792 ;
     RECT  22.387 18.774 22.595 18.864 ;
     RECT  21.415 1.728 22.711 17.289 ;
     RECT  22.063 0.036 22.775 0.279 ;
     RECT  22.711 1.656 22.847 17.289 ;
     RECT  22.595 18.774 22.855 18.792 ;
     RECT  22.855 18.702 23.027 18.792 ;
     RECT  22.775 0.036 23.243 0.198 ;
     RECT  23.027 18.774 23.279 18.792 ;
     RECT  23.243 0.036 23.315 0.054 ;
     RECT  22.847 1.728 23.351 17.289 ;
     RECT  23.351 2.151 24.223 17.289 ;
     RECT  24.763 18.774 24.863 18.792 ;
     RECT  24.223 2.106 25.547 17.289 ;
     RECT  25.547 2.151 26.311 17.289 ;
     RECT  25.771 0.036 26.455 0.054 ;
     RECT  26.455 0.036 26.815 0.126 ;
     RECT  26.815 0.036 27.103 0.162 ;
     RECT  27.103 0.036 27.427 0.198 ;
     RECT  26.815 18.774 27.599 18.792 ;
     RECT  27.427 0.036 27.707 0.234 ;
     RECT  27.707 0.036 27.923 0.162 ;
     RECT  26.311 1.728 28.067 17.289 ;
     RECT  27.923 0.036 28.139 0.126 ;
     RECT  28.139 0.108 28.247 0.126 ;
     RECT  28.067 2.106 29.327 17.289 ;
     RECT  30.451 0.108 30.523 0.126 ;
     RECT  30.523 0.036 30.659 0.126 ;
     RECT  29.327 2.151 30.811 17.289 ;
     RECT  30.659 0.072 30.883 0.126 ;
     RECT  30.883 0.072 31.127 0.279 ;
     RECT  31.127 0.072 31.567 0.198 ;
     RECT  30.811 1.728 31.667 17.289 ;
     RECT  31.567 0.036 31.703 0.198 ;
     RECT  31.703 0.036 32.063 0.162 ;
     RECT  32.063 0.108 32.099 0.162 ;
     RECT  32.071 18.621 32.107 18.639 ;
     RECT  32.099 0.108 32.207 0.126 ;
     RECT  32.107 18.621 32.243 18.792 ;
     RECT  32.243 18.666 32.315 18.792 ;
     RECT  32.315 18.774 32.495 18.792 ;
     RECT  31.667 2.151 32.719 17.289 ;
     RECT  32.719 1.728 32.999 17.289 ;
     RECT  35.095 0.036 35.131 0.054 ;
     RECT  32.999 2.151 35.203 17.289 ;
     RECT  35.203 2.106 35.491 17.676 ;
     RECT  35.491 1.728 35.527 17.676 ;
     RECT  35.527 1.728 35.699 17.748 ;
     RECT  35.699 2.034 35.879 17.748 ;
     RECT  35.131 0.036 36.211 0.126 ;
     RECT  35.879 2.034 36.419 17.289 ;
     RECT  36.211 0.036 36.427 0.198 ;
     RECT  36.427 0.036 36.499 0.234 ;
     RECT  36.499 0.036 36.599 0.279 ;
     RECT  36.599 0.036 36.707 0.234 ;
     RECT  36.419 2.151 36.859 17.289 ;
     RECT  36.707 0.036 36.959 0.198 ;
     RECT  35.995 18.774 36.959 18.792 ;
     RECT  36.859 2.151 37.067 17.712 ;
     RECT  36.959 0.036 37.571 0.126 ;
     RECT  37.571 0.108 37.607 0.126 ;
     RECT  37.067 2.151 39.703 17.289 ;
     RECT  39.703 2.151 39.775 17.712 ;
     RECT  39.775 1.728 40.055 17.712 ;
     RECT  40.135 0.108 40.243 0.126 ;
     RECT  40.171 19.206 40.271 19.224 ;
     RECT  40.055 1.728 40.343 17.37 ;
     RECT  40.343 1.728 40.387 17.289 ;
     RECT  40.387 1.656 40.487 17.289 ;
     RECT  40.487 1.728 40.811 17.289 ;
     RECT  40.243 0.036 40.883 0.126 ;
     RECT  40.883 0.036 40.919 0.054 ;
     RECT  40.811 2.151 41.04 17.289 ;
    LAYER M3 ;
     RECT  2.412 0.012 4.698 0.031 ;
     RECT  16.452 0.012 18.738 0.031 ;
     RECT  25.776 0.012 28.062 0.031 ;
     RECT  35.136 0.012 37.422 0.031 ;
     RECT  39.816 0.012 40.77 0.031 ;
     RECT  11.772 0.012 14.058 0.103 ;
     RECT  25.776 0.031 28.134 0.103 ;
     RECT  35.1 0.031 37.566 0.103 ;
     RECT  2.376 0.031 4.806 0.139 ;
     RECT  11.772 0.103 14.202 0.139 ;
     RECT  16.2 0.031 18.81 0.139 ;
     RECT  21.132 0.012 23.382 0.139 ;
     RECT  25.776 0.103 28.242 0.139 ;
     RECT  28.98 0.091 28.998 0.139 ;
     RECT  30.456 0.012 32.742 0.139 ;
     RECT  35.1 0.103 37.602 0.139 ;
     RECT  10.764 0.139 10.782 0.187 ;
     RECT  11.556 0.139 14.202 0.187 ;
     RECT  15.012 0.139 15.03 0.187 ;
     RECT  16.056 0.139 19.386 0.187 ;
     RECT  20.124 0.139 23.382 0.187 ;
     RECT  30.456 0.139 33.174 0.187 ;
     RECT  2.376 0.139 5.166 0.235 ;
     RECT  6.084 0.139 6.102 0.235 ;
     RECT  24.372 0.139 29.394 0.427 ;
     RECT  30.456 0.187 33.426 0.427 ;
     RECT  10.584 0.187 14.202 0.523 ;
     RECT  2.376 0.235 6.102 0.571 ;
     RECT  7.092 0.012 9.378 0.571 ;
     RECT  10.368 0.523 14.202 0.571 ;
     RECT  15.012 0.187 15.246 0.571 ;
     RECT  16.056 0.187 23.382 0.571 ;
     RECT  14.94 0.571 23.382 1.147 ;
     RECT  24.372 0.427 33.426 1.147 ;
     RECT  2.376 0.571 6.21 1.247 ;
     RECT  2.556 1.247 6.21 1.723 ;
     RECT  7.092 0.571 14.202 1.723 ;
     RECT  14.94 1.147 33.426 1.723 ;
     RECT  34.344 0.139 38.502 1.723 ;
     RECT  39.816 0.031 40.914 1.723 ;
     RECT  2.556 1.723 40.914 2.143 ;
     RECT  2.415 2.143 40.914 3.181 ;
     RECT  2.415 3.181 40.986 4.531 ;
     RECT  2.376 4.531 40.986 5.341 ;
     RECT  0.108 9.691 0.126 9.821 ;
     RECT  2.376 5.341 41.022 9.887 ;
     RECT  2.415 9.887 41.022 12.209 ;
     RECT  2.415 12.209 40.986 13.405 ;
     RECT  2.415 13.405 41.022 13.801 ;
     RECT  2.34 13.801 41.022 13.945 ;
     RECT  2.304 13.945 41.022 16.799 ;
     RECT  2.304 16.799 40.986 16.871 ;
     RECT  2.34 16.871 40.986 17.069 ;
     RECT  2.34 17.069 40.842 17.213 ;
     RECT  2.34 17.213 40.77 17.357 ;
     RECT  2.34 17.357 33.93 17.375 ;
     RECT  34.668 17.357 40.77 17.453 ;
     RECT  34.704 17.453 40.77 17.549 ;
     RECT  2.376 17.375 33.93 17.645 ;
     RECT  34.74 17.549 40.77 17.645 ;
     RECT  7.092 17.645 10.026 17.693 ;
     RECT  15.912 17.645 29.61 17.693 ;
     RECT  39.708 17.645 40.77 17.717 ;
     RECT  21.132 17.693 29.61 17.741 ;
     RECT  2.376 17.645 6.174 18.269 ;
     RECT  15.912 17.693 20.394 18.269 ;
     RECT  21.132 17.741 28.494 18.269 ;
     RECT  38.628 17.645 38.754 18.269 ;
     RECT  29.304 17.741 29.61 18.317 ;
     RECT  38.628 18.269 38.646 18.317 ;
     RECT  29.592 18.317 29.61 18.413 ;
     RECT  11.232 17.645 14.922 18.797 ;
     RECT  15.912 18.269 19.35 18.797 ;
     RECT  24.732 18.269 28.458 18.797 ;
     RECT  30.456 17.645 33.93 18.797 ;
     RECT  34.74 17.645 37.422 18.797 ;
     RECT  2.376 18.269 5.67 18.833 ;
     RECT  2.412 18.833 5.67 18.845 ;
     RECT  11.232 18.797 14.058 18.845 ;
     RECT  21.132 18.269 23.994 18.845 ;
     RECT  30.456 18.797 32.994 18.845 ;
     RECT  24.732 18.797 28.062 18.893 ;
     RECT  24.732 18.893 24.786 18.941 ;
     RECT  16.452 18.797 19.35 19.003 ;
     RECT  14.904 18.797 14.922 19.195 ;
     RECT  2.412 18.845 5.31 19.277 ;
     RECT  14.904 19.195 14.994 19.277 ;
     RECT  24.732 18.941 24.75 19.277 ;
     RECT  33.912 18.797 33.93 19.277 ;
     RECT  14.976 19.277 14.994 19.325 ;
     RECT  16.452 19.003 19.602 19.325 ;
     RECT  2.412 19.277 4.698 19.421 ;
     RECT  7.092 17.693 9.378 19.421 ;
     RECT  11.772 18.845 14.058 19.421 ;
     RECT  16.452 19.325 18.738 19.421 ;
     RECT  21.132 18.845 23.382 19.421 ;
     RECT  25.776 18.893 28.062 19.421 ;
     RECT  30.456 18.845 32.742 19.421 ;
     RECT  35.136 18.797 37.422 19.421 ;
     RECT  39.816 17.717 40.77 19.421 ;
    LAYER M4 ;
     RECT  0.097 9.696 0.137 9.816 ;
     RECT  2.293 5.616 2.408 5.64 ;
     RECT  0.137 9.792 2.408 9.816 ;
     RECT  2.293 14.208 2.408 14.232 ;
     RECT  2.293 16.032 2.408 16.056 ;
     RECT  2.408 2.148 2.512 17.292 ;
     RECT  2.512 2.418 2.704 17.022 ;
     RECT  2.704 2.832 2.837 2.856 ;
     RECT  2.704 11.664 2.867 16.584 ;
     RECT  2.704 4.512 2.915 4.536 ;
     RECT  2.704 6 3.011 6.888 ;
     RECT  2.704 7.92 3.059 9.72 ;
     RECT  2.867 14.832 3.089 16.584 ;
     RECT  3.011 6 3.107 6.84 ;
     RECT  3.059 8.352 3.299 9.72 ;
     RECT  3.299 8.496 3.587 9.72 ;
     RECT  3.089 16.56 3.601 16.584 ;
     RECT  2.867 11.664 3.724 13.704 ;
     RECT  2.689 0.048 3.809 0.072 ;
     RECT  3.877 0.096 3.989 0.12 ;
     RECT  3.905 18.816 3.989 18.84 ;
     RECT  3.107 6 4.069 6.024 ;
     RECT  4.069 5.088 4.156 6.024 ;
     RECT  3.724 11.664 4.169 12.552 ;
     RECT  3.089 15.312 4.237 15.336 ;
     RECT  4.237 14.832 4.517 15.336 ;
     RECT  3.587 9.024 4.525 9.72 ;
     RECT  4.517 14.784 4.636 15.336 ;
     RECT  4.453 2.736 4.673 2.76 ;
     RECT  4.741 17.616 4.813 17.64 ;
     RECT  4.741 1.152 4.837 1.176 ;
     RECT  4.636 14.832 4.961 15.336 ;
     RECT  4.813 17.088 5.029 17.64 ;
     RECT  4.805 19.248 5.029 19.272 ;
     RECT  5.021 3.36 5.105 3.528 ;
     RECT  5.105 3.36 5.177 3.432 ;
     RECT  4.525 9.024 5.209 10.056 ;
     RECT  4.961 15.168 5.245 15.336 ;
     RECT  4.169 12.528 5.249 12.552 ;
     RECT  5.177 3.408 5.267 3.432 ;
     RECT  5.209 8.064 5.281 10.056 ;
     RECT  5.281 7.968 5.293 10.056 ;
     RECT  4.837 0.144 5.317 1.176 ;
     RECT  5.029 17.088 5.321 19.272 ;
     RECT  5.245 15.168 5.329 16.008 ;
     RECT  4.156 6 5.353 6.024 ;
     RECT  5.317 0.144 5.413 1.272 ;
     RECT  5.353 6 5.461 6.312 ;
     RECT  5.293 9.024 5.461 10.056 ;
     RECT  3.724 13.68 5.461 13.704 ;
     RECT  5.413 0.144 5.525 1.752 ;
     RECT  5.461 5.04 5.548 6.312 ;
     RECT  5.525 0.144 5.573 2.28 ;
     RECT  5.573 0.144 5.645 0.648 ;
     RECT  5.461 13.632 5.677 13.704 ;
     RECT  5.677 13.584 5.717 13.704 ;
     RECT  5.321 17.088 5.747 18.84 ;
     RECT  5.329 15.168 5.891 15.384 ;
     RECT  5.293 7.968 5.897 7.992 ;
     RECT  5.461 9.024 5.897 10.296 ;
     RECT  5.548 5.616 6.131 6.312 ;
     RECT  6.145 3.792 6.277 3.816 ;
     RECT  5.897 9.12 6.289 10.296 ;
     RECT  5.137 11.376 6.289 11.4 ;
     RECT  5.747 17.088 6.323 18.264 ;
     RECT  5.573 1.728 6.505 2.28 ;
     RECT  6.277 3.792 6.505 4.008 ;
     RECT  6.505 1.728 6.653 4.008 ;
     RECT  5.717 13.584 6.901 13.656 ;
     RECT  5.891 15.168 6.937 15.288 ;
     RECT  6.937 15.168 6.997 15.432 ;
     RECT  6.997 15.168 7.009 16.008 ;
     RECT  6.901 19.248 7.043 19.272 ;
     RECT  6.131 5.616 7.141 6.264 ;
     RECT  6.289 9.12 7.148 11.4 ;
     RECT  7.141 5.616 7.153 6.84 ;
     RECT  7.148 8.928 7.189 11.4 ;
     RECT  6.653 1.728 7.193 3.816 ;
     RECT  5.645 0.144 7.265 0.6 ;
     RECT  7.153 5.616 7.292 7.272 ;
     RECT  7.189 8.544 7.369 11.4 ;
     RECT  6.323 17.088 7.381 17.64 ;
     RECT  7.292 4.848 7.397 7.272 ;
     RECT  7.369 8.544 7.397 11.976 ;
     RECT  7.297 0.096 7.409 0.12 ;
     RECT  7.009 14.832 7.429 16.008 ;
     RECT  6.901 13.44 7.436 13.656 ;
     RECT  7.429 14.832 7.441 16.056 ;
     RECT  7.381 17.088 7.441 17.688 ;
     RECT  7.441 14.832 7.481 17.688 ;
     RECT  7.193 2.148 7.657 3.816 ;
     RECT  7.397 4.848 7.657 11.976 ;
     RECT  7.657 2.148 7.808 11.976 ;
     RECT  7.436 13.248 7.808 13.656 ;
     RECT  7.481 14.832 7.808 17.292 ;
     RECT  7.808 2.148 7.912 17.292 ;
     RECT  7.912 2.418 8.104 17.022 ;
     RECT  8.104 5.04 8.201 9.72 ;
     RECT  8.104 2.832 8.243 3.384 ;
     RECT  8.201 8.544 8.243 9.72 ;
     RECT  8.104 10.704 8.243 13.08 ;
     RECT  7.981 0.048 8.291 0.072 ;
     RECT  8.104 14.112 8.291 16.824 ;
     RECT  8.243 10.8 8.345 13.08 ;
     RECT  8.201 5.04 8.453 7.368 ;
     RECT  8.453 5.04 8.813 5.112 ;
     RECT  8.453 6.288 8.885 7.368 ;
     RECT  8.243 2.832 8.963 2.856 ;
     RECT  8.291 14.112 8.963 15.432 ;
     RECT  8.291 16.56 9.029 16.824 ;
     RECT  8.345 10.848 9.059 13.08 ;
     RECT  9.059 11.232 9.1 13.08 ;
     RECT  9.1 11.232 9.173 11.448 ;
     RECT  9.385 2.064 9.421 2.088 ;
     RECT  8.963 14.16 9.457 15.432 ;
     RECT  8.885 6.288 9.497 6.744 ;
     RECT  9.445 17.088 9.529 17.112 ;
     RECT  8.953 18.24 9.529 18.264 ;
     RECT  9.457 14.16 9.533 16.008 ;
     RECT  9.529 17.088 9.539 18.264 ;
     RECT  9.313 3.696 9.601 3.72 ;
     RECT  9.497 6.288 9.713 6.696 ;
     RECT  9.601 3.696 9.745 3.768 ;
     RECT  8.813 5.04 9.745 5.064 ;
     RECT  9.533 15.024 9.779 16.008 ;
     RECT  9.733 0.144 9.781 0.168 ;
     RECT  9.779 15.024 9.827 15.624 ;
     RECT  9.781 0.144 9.925 0.6 ;
     RECT  9.421 1.728 9.925 2.088 ;
     RECT  9.925 0.144 10.067 2.088 ;
     RECT  9.827 15.024 10.145 15.432 ;
     RECT  10.067 1.728 10.213 2.088 ;
     RECT  9.745 3.696 10.213 5.064 ;
     RECT  10.213 1.728 10.259 5.064 ;
     RECT  9.539 17.088 10.355 17.688 ;
     RECT  9.173 11.376 10.508 11.448 ;
     RECT  10.453 19.248 10.595 19.272 ;
     RECT  9.713 6.288 10.649 6.312 ;
     RECT  8.243 8.928 10.897 9.72 ;
     RECT  9.1 13.056 10.933 13.08 ;
     RECT  10.145 15.024 10.94 15.048 ;
     RECT  10.897 8.88 10.969 9.72 ;
     RECT  10.259 1.728 11.009 3.336 ;
     RECT  10.94 14.208 11.027 15.048 ;
     RECT  11.009 1.728 11.117 3.096 ;
     RECT  11.117 2.88 11.189 3.096 ;
     RECT  10.969 8.88 11.221 9.816 ;
     RECT  10.508 11.376 11.221 11.784 ;
     RECT  10.933 13.056 11.221 13.128 ;
     RECT  10.067 0.144 11.297 0.6 ;
     RECT  11.221 11.376 11.308 13.128 ;
     RECT  11.308 11.376 11.315 11.88 ;
     RECT  11.221 18.816 11.315 18.84 ;
     RECT  11.027 14.256 11.333 15.048 ;
     RECT  11.315 11.376 11.365 11.4 ;
     RECT  10.355 17.088 11.365 17.64 ;
     RECT  10.357 5.136 11.372 5.16 ;
     RECT  11.333 14.352 11.401 15.048 ;
     RECT  11.365 10.896 11.411 11.4 ;
     RECT  11.308 12.912 11.411 13.128 ;
     RECT  11.401 14.352 11.413 16.008 ;
     RECT  11.365 17.088 11.413 18.216 ;
     RECT  11.189 3.072 11.441 3.096 ;
     RECT  11.372 5.088 11.459 5.16 ;
     RECT  11.413 14.352 11.513 18.216 ;
     RECT  11.513 17.04 11.603 18.216 ;
     RECT  11.297 0.144 11.621 0.264 ;
     RECT  11.513 14.352 11.657 16.008 ;
     RECT  11.221 8.4 11.663 9.816 ;
     RECT  11.411 10.896 11.663 10.92 ;
     RECT  11.603 17.04 11.665 17.64 ;
     RECT  11.411 13.104 11.765 13.128 ;
     RECT  11.665 17.04 11.765 17.208 ;
     RECT  11.621 0.144 11.797 0.216 ;
     RECT  11.117 1.728 11.909 1.896 ;
     RECT  11.657 14.688 11.909 16.008 ;
     RECT  11.797 0.048 11.945 0.216 ;
     RECT  11.909 1.872 11.945 1.896 ;
     RECT  11.909 15.984 12.241 16.008 ;
     RECT  11.977 19.344 12.653 19.368 ;
     RECT  12.337 2.832 12.661 2.856 ;
     RECT  11.663 8.4 12.661 10.92 ;
     RECT  12.337 11.952 12.661 11.976 ;
     RECT  12.337 13.152 12.689 13.176 ;
     RECT  11.459 5.136 12.733 5.16 ;
     RECT  12.709 6.192 12.733 6.216 ;
     RECT  12.653 18.816 12.737 19.368 ;
     RECT  11.765 17.04 12.877 17.064 ;
     RECT  12.661 2.832 12.949 3.672 ;
     RECT  12.733 5.136 12.949 6.216 ;
     RECT  11.605 7.2 12.949 7.224 ;
     RECT  12.689 13.152 12.949 13.704 ;
     RECT  11.909 14.688 12.949 14.712 ;
     RECT  12.949 13.152 12.985 14.712 ;
     RECT  12.737 19.344 12.995 19.368 ;
     RECT  12.949 2.832 13.093 7.224 ;
     RECT  12.661 8.4 13.093 11.976 ;
     RECT  13.093 2.064 13.208 11.976 ;
     RECT  12.985 13.152 13.208 14.856 ;
     RECT  12.877 16.416 13.208 17.064 ;
     RECT  13.045 18.24 13.208 18.264 ;
     RECT  13.208 2.064 13.277 18.264 ;
     RECT  13.277 2.148 13.504 18.264 ;
     RECT  13.309 0.576 13.525 0.6 ;
     RECT  13.525 0.576 13.58 0.648 ;
     RECT  13.504 13.104 13.619 13.176 ;
     RECT  13.58 0.048 13.667 0.648 ;
     RECT  13.504 2.148 13.667 4.104 ;
     RECT  13.504 6.576 13.667 6.936 ;
     RECT  13.504 14.688 13.681 16.008 ;
     RECT  13.667 0.576 13.781 0.648 ;
     RECT  13.619 13.152 13.781 13.176 ;
     RECT  13.667 2.148 13.907 3.336 ;
     RECT  13.667 6.576 13.961 6.6 ;
     RECT  13.907 2.148 14.213 2.904 ;
     RECT  13.504 9.696 14.357 11.4 ;
     RECT  14.213 2.88 14.501 2.904 ;
     RECT  14.492 6.24 14.579 6.264 ;
     RECT  13.504 17.088 14.579 18.264 ;
     RECT  13.681 14.688 14.713 15.432 ;
     RECT  14.713 14.688 14.797 16.008 ;
     RECT  13.781 0.624 14.821 0.648 ;
     RECT  14.245 1.728 14.821 1.896 ;
     RECT  14.713 18.768 14.821 18.792 ;
     RECT  14.821 0.624 14.885 1.896 ;
     RECT  14.579 17.088 14.917 17.64 ;
     RECT  14.821 18.768 14.932 19.272 ;
     RECT  14.725 5.376 14.933 5.4 ;
     RECT  14.885 0.576 14.957 1.896 ;
     RECT  14.785 7.872 15.001 7.896 ;
     RECT  14.797 14.688 15.005 15.48 ;
     RECT  14.957 0.144 15.077 1.896 ;
     RECT  14.785 13.632 15.145 13.656 ;
     RECT  14.932 18.768 15.155 19.32 ;
     RECT  15.077 1.728 15.181 1.896 ;
     RECT  15.155 18.768 15.203 19.224 ;
     RECT  15.145 13.584 15.229 13.656 ;
     RECT  15.001 7.872 15.356 7.992 ;
     RECT  14.357 9.696 15.356 10.104 ;
     RECT  15.356 7.872 15.365 10.104 ;
     RECT  15.229 13.632 15.437 13.656 ;
     RECT  15.365 7.968 15.443 10.104 ;
     RECT  14.357 11.088 15.443 11.4 ;
     RECT  15.181 1.728 15.677 2.28 ;
     RECT  15.443 11.136 15.685 11.4 ;
     RECT  15.677 1.728 15.761 2.328 ;
     RECT  14.917 16.8 15.769 17.64 ;
     RECT  15.769 16.8 15.833 17.544 ;
     RECT  15.077 0.144 15.941 0.648 ;
     RECT  15.761 1.728 15.971 2.28 ;
     RECT  15.833 16.8 15.971 17.304 ;
     RECT  15.397 4.848 15.973 4.872 ;
     RECT  15.203 18.768 16.019 18.792 ;
     RECT  15.973 4.848 16.049 5.64 ;
     RECT  16.009 6.672 16.153 6.696 ;
     RECT  15.941 0.144 16.157 0.216 ;
     RECT  16.049 5.616 16.189 5.64 ;
     RECT  15.005 14.688 16.325 14.712 ;
     RECT  16.189 3.792 16.333 3.816 ;
     RECT  15.971 16.8 16.403 17.208 ;
     RECT  16.333 3.792 16.417 3.96 ;
     RECT  16.325 14.688 16.433 14.856 ;
     RECT  16.189 5.616 16.453 5.688 ;
     RECT  16.153 6.672 16.453 6.744 ;
     RECT  16.433 14.256 16.477 14.856 ;
     RECT  15.971 1.728 16.481 1.848 ;
     RECT  15.443 8.976 16.513 10.104 ;
     RECT  15.685 11.136 16.513 11.976 ;
     RECT  16.453 5.616 16.547 6.744 ;
     RECT  16.513 8.976 16.621 11.976 ;
     RECT  16.364 13.056 16.621 13.08 ;
     RECT  16.157 0.144 16.661 0.168 ;
     RECT  16.621 8.976 16.693 13.08 ;
     RECT  16.213 19.248 16.729 19.272 ;
     RECT  16.547 5.664 16.805 6.744 ;
     RECT  15.443 7.968 16.913 7.992 ;
     RECT  16.805 6.192 16.981 6.744 ;
     RECT  16.981 6.192 16.985 7.896 ;
     RECT  16.729 19.248 17.045 19.368 ;
     RECT  16.985 6.672 17.075 7.896 ;
     RECT  16.693 8.976 17.077 13.128 ;
     RECT  16.477 14.256 17.125 15.432 ;
     RECT  16.403 16.8 17.125 17.064 ;
     RECT  17.045 18.816 17.129 19.368 ;
     RECT  17.125 14.256 17.157 17.064 ;
     RECT  17.075 6.672 17.171 7.8 ;
     RECT  17.077 8.976 17.197 13.224 ;
     RECT  17.157 14.256 17.197 16.584 ;
     RECT  17.197 8.976 17.209 16.584 ;
     RECT  17.209 8.976 17.219 14.712 ;
     RECT  17.228 2.688 17.315 2.712 ;
     RECT  16.417 3.792 17.413 3.816 ;
     RECT  17.171 6.672 17.453 7.464 ;
     RECT  17.413 3.216 17.557 3.816 ;
     RECT  17.269 1.152 17.597 1.176 ;
     RECT  17.129 19.344 17.939 19.368 ;
     RECT  17.219 14.064 18.229 14.712 ;
     RECT  17.209 15.984 18.229 16.584 ;
     RECT  17.219 8.976 18.421 12.36 ;
     RECT  18.229 14.064 18.421 16.584 ;
     RECT  18.061 18.24 18.421 18.264 ;
     RECT  18.385 0.048 18.533 0.072 ;
     RECT  18.277 2.016 18.608 2.04 ;
     RECT  17.557 3.216 18.608 3.912 ;
     RECT  17.737 4.944 18.608 4.968 ;
     RECT  17.453 7.44 18.608 7.464 ;
     RECT  18.421 8.976 18.608 18.264 ;
     RECT  18.608 2.016 18.82 18.264 ;
     RECT  18.82 1.776 18.904 18.264 ;
     RECT  18.901 0.144 19.045 0.168 ;
     RECT  18.904 9.36 19.084 11.928 ;
     RECT  19.084 9.6 19.139 11.928 ;
     RECT  18.904 13.68 19.181 16.008 ;
     RECT  19.045 0.144 19.189 0.216 ;
     RECT  18.904 17.088 19.252 18.264 ;
     RECT  18.997 19.248 19.252 19.272 ;
     RECT  19.189 0.144 19.285 0.264 ;
     RECT  18.904 1.776 19.325 5.928 ;
     RECT  19.325 3.312 19.331 5.928 ;
     RECT  19.252 17.088 19.357 19.272 ;
     RECT  19.331 3.312 19.379 5.736 ;
     RECT  19.379 3.312 19.397 5.112 ;
     RECT  19.181 13.68 19.397 15.336 ;
     RECT  19.397 3.936 19.42 5.112 ;
     RECT  19.285 0.144 19.429 0.312 ;
     RECT  19.325 1.776 19.429 2.328 ;
     RECT  19.139 9.6 19.564 10.104 ;
     RECT  19.357 17.088 19.619 19.32 ;
     RECT  19.619 19.296 19.657 19.32 ;
     RECT  18.904 7.248 20.077 7.992 ;
     RECT  19.397 13.968 20.197 15.336 ;
     RECT  19.564 9.696 20.221 10.104 ;
     RECT  19.139 11.376 20.221 11.928 ;
     RECT  20.077 6.768 20.261 7.992 ;
     RECT  20.197 13.968 20.435 15.72 ;
     RECT  20.261 6.816 20.441 7.464 ;
     RECT  19.42 5.088 20.477 5.112 ;
     RECT  19.429 0.144 20.509 2.328 ;
     RECT  19.42 3.936 20.509 3.96 ;
     RECT  19.619 17.088 20.627 18.264 ;
     RECT  20.509 0.144 20.657 3.96 ;
     RECT  20.657 1.152 20.729 2.28 ;
     RECT  20.657 0.144 20.765 0.168 ;
     RECT  20.627 17.088 20.771 17.688 ;
     RECT  20.657 3.888 20.801 3.96 ;
     RECT  20.437 12.912 20.869 12.936 ;
     RECT  20.435 13.968 20.869 13.992 ;
     RECT  20.729 1.728 20.945 2.28 ;
     RECT  20.945 1.776 21.053 2.28 ;
     RECT  20.771 17.088 21.059 17.208 ;
     RECT  20.435 15.408 21.085 15.72 ;
     RECT  21.053 1.92 21.089 2.28 ;
     RECT  20.221 9.696 21.125 11.928 ;
     RECT  21.085 15.408 21.196 16.008 ;
     RECT  20.869 12.912 21.197 13.992 ;
     RECT  20.689 5.376 21.203 5.4 ;
     RECT  21.125 9.696 21.341 11.4 ;
     RECT  20.441 6.816 21.587 7.368 ;
     RECT  21.196 15.984 21.625 16.008 ;
     RECT  21.587 6.912 21.772 7.368 ;
     RECT  21.341 9.696 21.781 10.776 ;
     RECT  21.625 2.832 21.877 2.856 ;
     RECT  20.801 3.888 21.877 3.912 ;
     RECT  21.781 9.648 21.881 10.776 ;
     RECT  21.772 6.912 21.949 7.416 ;
     RECT  21.949 6.912 22.124 7.896 ;
     RECT  21.581 18.816 22.124 18.84 ;
     RECT  22.124 6.912 22.129 8.424 ;
     RECT  22.129 6.912 22.165 8.52 ;
     RECT  21.197 12.912 22.165 13.608 ;
     RECT  22.124 18.816 22.211 19.368 ;
     RECT  22.165 12.528 22.249 13.608 ;
     RECT  21.877 2.832 22.273 3.912 ;
     RECT  21.781 14.832 22.337 14.856 ;
     RECT  21.625 15.984 22.337 16.584 ;
     RECT  22.337 14.832 22.349 16.584 ;
     RECT  22.273 2.832 22.357 3.96 ;
     RECT  21.881 10.08 22.381 10.776 ;
     RECT  22.249 13.584 22.489 13.608 ;
     RECT  22.381 10.08 22.493 10.824 ;
     RECT  22.249 12.528 22.669 12.552 ;
     RECT  22.561 0.048 22.709 0.072 ;
     RECT  22.489 5.76 22.777 5.784 ;
     RECT  22.493 10.08 22.787 10.776 ;
     RECT  22.357 2.832 22.853 3.432 ;
     RECT  22.165 6.912 23.029 9.048 ;
     RECT  23.209 0.096 23.321 0.12 ;
     RECT  22.349 15.36 23.42 16.584 ;
     RECT  22.853 2.88 23.461 3.432 ;
     RECT  23.42 15.36 23.461 17.112 ;
     RECT  22.777 5.76 23.468 5.88 ;
     RECT  23.029 6.864 23.468 9.048 ;
     RECT  22.489 13.584 23.509 13.656 ;
     RECT  22.669 11.952 23.533 12.552 ;
     RECT  23.509 13.584 23.533 13.704 ;
     RECT  23.533 11.952 23.641 13.704 ;
     RECT  23.461 14.688 23.641 17.64 ;
     RECT  23.605 1.728 23.653 1.752 ;
     RECT  22.787 10.224 23.677 10.776 ;
     RECT  23.641 11.952 23.677 17.64 ;
     RECT  23.653 1.728 23.749 1.848 ;
     RECT  23.468 5.76 23.749 9.048 ;
     RECT  23.749 5.616 23.857 9.048 ;
     RECT  23.677 10.224 23.857 17.64 ;
     RECT  23.749 1.152 23.861 1.848 ;
     RECT  23.861 1.728 23.893 1.848 ;
     RECT  23.461 2.88 23.893 3.48 ;
     RECT  23.893 0.144 23.941 0.168 ;
     RECT  23.893 1.728 24.008 3.48 ;
     RECT  23.857 5.616 24.008 17.64 ;
     RECT  24.008 1.728 24.304 17.64 ;
     RECT  24.304 1.728 24.419 7.416 ;
     RECT  24.304 11.184 24.467 16.008 ;
     RECT  24.304 17.04 24.469 17.64 ;
     RECT  22.211 18.816 24.469 18.84 ;
     RECT  24.419 1.728 24.473 7.368 ;
     RECT  24.473 1.728 24.509 6.216 ;
     RECT  24.304 8.448 24.509 10.104 ;
     RECT  24.509 3.408 24.553 6.216 ;
     RECT  24.553 3.408 24.581 3.96 ;
     RECT  24.469 17.04 24.589 19.272 ;
     RECT  24.553 5.136 24.617 6.216 ;
     RECT  24.589 17.088 24.659 19.272 ;
     RECT  24.581 3.888 24.755 3.96 ;
     RECT  24.467 13.584 24.769 16.008 ;
     RECT  24.659 17.088 24.841 17.64 ;
     RECT  24.769 13.584 25.201 15.432 ;
     RECT  24.467 11.184 25.297 12.552 ;
     RECT  23.941 0.144 25.325 0.6 ;
     RECT  24.509 1.728 25.325 2.28 ;
     RECT  24.659 18.816 25.331 19.272 ;
     RECT  25.331 18.816 25.379 18.888 ;
     RECT  25.297 11.088 25.381 12.552 ;
     RECT  25.325 0.144 25.409 2.28 ;
     RECT  24.473 7.344 25.484 7.368 ;
     RECT  24.509 8.448 25.484 9.672 ;
     RECT  25.381 10.8 25.621 12.552 ;
     RECT  25.201 13.584 25.621 13.656 ;
     RECT  25.409 1.728 25.667 2.28 ;
     RECT  24.841 17.088 25.667 17.256 ;
     RECT  25.409 0.144 25.697 0.312 ;
     RECT  25.484 7.344 25.697 9.672 ;
     RECT  25.697 0.144 25.733 0.216 ;
     RECT  25.379 18.864 25.763 18.888 ;
     RECT  25.621 10.8 25.769 13.656 ;
     RECT  25.201 14.688 25.801 15.432 ;
     RECT  25.769 11.376 25.841 12.648 ;
     RECT  25.733 0.144 25.913 0.168 ;
     RECT  25.769 13.632 25.913 13.656 ;
     RECT  24.617 6 25.945 6.216 ;
     RECT  25.697 7.344 26.003 9.48 ;
     RECT  25.667 1.728 26.057 1.752 ;
     RECT  25.981 2.88 26.089 2.904 ;
     RECT  24.755 3.936 26.089 3.96 ;
     RECT  25.945 5.664 26.125 6.216 ;
     RECT  26.003 7.344 26.14 7.8 ;
     RECT  26.089 2.88 26.237 3.96 ;
     RECT  26.125 5.664 26.245 6.264 ;
     RECT  25.801 14.688 26.245 16.008 ;
     RECT  26.245 5.664 26.332 6.84 ;
     RECT  26.237 3.744 26.353 3.96 ;
     RECT  25.841 11.952 26.483 12.648 ;
     RECT  26.245 14.688 26.525 16.632 ;
     RECT  26.437 18.816 26.633 18.84 ;
     RECT  26.003 9.024 26.665 9.48 ;
     RECT  26.483 12.624 26.849 12.648 ;
     RECT  26.525 14.688 26.849 16.104 ;
     RECT  26.849 14.688 26.965 16.008 ;
     RECT  26.332 5.664 27.001 6.264 ;
     RECT  26.665 9.024 27.025 9.72 ;
     RECT  27.025 8.544 27.203 9.72 ;
     RECT  27.157 2.736 27.212 2.76 ;
     RECT  26.353 3.744 27.212 3.864 ;
     RECT  27.212 2.736 27.281 3.864 ;
     RECT  27.001 5.712 27.313 6.264 ;
     RECT  27.313 5.712 27.353 6.744 ;
     RECT  27.281 3.072 27.421 3.864 ;
     RECT  27.313 13.104 27.493 13.128 ;
     RECT  26.965 14.688 27.493 14.808 ;
     RECT  27.353 6.24 27.677 6.744 ;
     RECT  27.493 13.104 27.677 14.808 ;
     RECT  27.565 10.848 27.821 10.872 ;
     RECT  27.203 8.88 27.889 9.72 ;
     RECT  27.025 0.048 27.929 0.072 ;
     RECT  27.677 6.72 28.073 6.744 ;
     RECT  27.997 17.52 28.105 17.544 ;
     RECT  28.021 19.152 28.117 19.176 ;
     RECT  28.117 1.728 28.165 1.752 ;
     RECT  27.677 13.104 28.177 14.712 ;
     RECT  28.165 1.728 28.249 1.848 ;
     RECT  27.421 3.072 28.249 4.104 ;
     RECT  28.249 1.728 28.357 4.104 ;
     RECT  28.177 12.912 28.357 14.712 ;
     RECT  28.357 1.728 28.403 4.536 ;
     RECT  28.403 1.728 28.405 3 ;
     RECT  28.117 19.152 28.429 19.272 ;
     RECT  28.357 12.528 28.44 14.712 ;
     RECT  28.105 17.52 28.465 17.64 ;
     RECT  28.429 18.768 28.465 19.272 ;
     RECT  28.465 17.52 28.501 19.272 ;
     RECT  27.889 8.88 28.609 9.816 ;
     RECT  28.261 0.096 28.637 0.168 ;
     RECT  28.44 12.48 28.717 14.712 ;
     RECT  28.717 12.48 28.741 14.808 ;
     RECT  28.501 17.088 28.835 19.272 ;
     RECT  28.637 0.096 28.837 0.216 ;
     RECT  26.965 15.984 28.933 16.008 ;
     RECT  28.835 17.088 28.979 19.176 ;
     RECT  28.837 0.096 29.009 0.6 ;
     RECT  28.933 15.888 29.105 16.008 ;
     RECT  28.979 17.088 29.105 18.408 ;
     RECT  29.009 0.144 29.125 0.6 ;
     RECT  28.405 1.728 29.125 2.904 ;
     RECT  28.741 12.336 29.125 14.808 ;
     RECT  29.105 15.888 29.125 18.408 ;
     RECT  28.403 4.512 29.149 4.536 ;
     RECT  29.125 12.336 29.185 18.408 ;
     RECT  29.185 11.952 29.221 18.408 ;
     RECT  29.221 11.664 29.365 18.408 ;
     RECT  29.125 0.144 29.405 2.904 ;
     RECT  29.405 0.432 29.408 2.904 ;
     RECT  29.149 4.512 29.408 5.064 ;
     RECT  28.321 6.816 29.408 6.84 ;
     RECT  28.609 7.92 29.408 9.816 ;
     RECT  29.365 11.568 29.408 18.408 ;
     RECT  29.408 0.432 29.704 18.408 ;
     RECT  29.704 13.104 29.747 18.408 ;
     RECT  29.704 3.936 29.843 6.84 ;
     RECT  29.704 11.376 29.873 11.976 ;
     RECT  29.704 0.432 29.891 1.848 ;
     RECT  29.891 0.528 30.197 1.848 ;
     RECT  29.989 19.248 30.227 19.272 ;
     RECT  29.843 3.936 30.275 4.536 ;
     RECT  29.747 13.104 30.275 17.64 ;
     RECT  29.843 5.712 30.305 6.84 ;
     RECT  30.197 0.528 30.341 1.8 ;
     RECT  30.341 1.152 30.377 1.8 ;
     RECT  30.275 3.936 30.413 3.96 ;
     RECT  30.275 17.616 30.413 17.64 ;
     RECT  30.305 6.192 30.467 6.84 ;
     RECT  30.377 1.728 30.485 1.8 ;
     RECT  30.275 13.104 30.521 16.584 ;
     RECT  29.704 7.92 30.529 10.248 ;
     RECT  30.485 1.728 30.593 1.752 ;
     RECT  30.521 16.56 30.593 16.584 ;
     RECT  30.467 6.72 30.659 6.84 ;
     RECT  30.529 7.92 30.697 7.944 ;
     RECT  29.873 11.376 30.709 11.784 ;
     RECT  30.697 7.632 30.737 7.944 ;
     RECT  30.529 9.072 30.745 10.248 ;
     RECT  30.745 9.504 31.061 10.248 ;
     RECT  29.704 2.88 31.097 2.904 ;
     RECT  30.709 11.76 31.244 11.784 ;
     RECT  31.244 11.76 31.331 11.88 ;
     RECT  30.521 13.104 31.331 15.48 ;
     RECT  31.331 13.104 31.34 14.088 ;
     RECT  31.331 11.76 31.349 11.784 ;
     RECT  31.34 12.912 31.427 14.088 ;
     RECT  31.331 15.456 31.561 15.48 ;
     RECT  31.381 2.832 31.637 2.856 ;
     RECT  31.561 5.904 31.667 6.552 ;
     RECT  31.667 6.528 31.709 6.552 ;
     RECT  31.061 9.504 31.821 10.152 ;
     RECT  30.737 7.632 31.861 7.656 ;
     RECT  31.861 7.632 31.907 7.8 ;
     RECT  31.409 4.368 31.909 4.392 ;
     RECT  31.561 15.456 31.909 16.008 ;
     RECT  31.909 4.368 31.996 4.536 ;
     RECT  31.093 0.048 32.285 0.072 ;
     RECT  31.907 7.776 32.291 7.8 ;
     RECT  31.909 15.456 32.317 16.056 ;
     RECT  32.173 18.768 32.321 18.792 ;
     RECT  31.821 9.072 32.429 10.152 ;
     RECT  31.427 13.104 32.605 14.088 ;
     RECT  32.605 12.72 32.713 14.088 ;
     RECT  32.317 15.216 32.821 16.056 ;
     RECT  32.732 17.088 32.821 17.112 ;
     RECT  32.869 0.144 32.917 0.168 ;
     RECT  32.773 1.728 32.972 1.752 ;
     RECT  32.821 15.216 33.001 17.256 ;
     RECT  32.713 11.904 33.005 14.088 ;
     RECT  33.001 15.216 33.107 17.688 ;
     RECT  32.965 6.816 33.155 7.272 ;
     RECT  32.917 0.144 33.173 0.264 ;
     RECT  33.173 0.144 33.185 0.36 ;
     RECT  33.107 16.56 33.203 17.688 ;
     RECT  31.996 4.368 33.253 4.392 ;
     RECT  33.185 0.192 33.257 0.36 ;
     RECT  33.257 0.192 33.293 0.264 ;
     RECT  32.965 18.816 33.433 18.84 ;
     RECT  33.293 0.192 33.437 0.216 ;
     RECT  33.005 11.904 33.545 13.704 ;
     RECT  33.433 18.768 33.683 18.84 ;
     RECT  33.203 16.56 33.805 17.64 ;
     RECT  33.805 16.56 33.875 17.592 ;
     RECT  33.836 11.04 33.877 11.304 ;
     RECT  33.433 3.36 33.901 3.384 ;
     RECT  33.253 4.368 33.901 5.256 ;
     RECT  33.857 19.248 33.941 19.272 ;
     RECT  33.155 6.816 34.117 7.224 ;
     RECT  32.429 9.072 34.117 9.72 ;
     RECT  33.107 15.216 34.309 15.432 ;
     RECT  33.875 16.56 34.309 17.544 ;
     RECT  32.972 1.728 34.453 2.28 ;
     RECT  33.901 3.36 34.453 5.256 ;
     RECT  34.289 0.144 34.597 0.168 ;
     RECT  34.453 1.728 34.693 5.256 ;
     RECT  34.117 6.816 34.693 9.72 ;
     RECT  33.877 10.752 34.693 11.304 ;
     RECT  33.545 12.336 34.693 13.704 ;
     RECT  34.597 0.144 34.765 0.264 ;
     RECT  34.693 1.728 34.765 13.704 ;
     RECT  34.765 0.144 34.808 13.704 ;
     RECT  34.309 15.216 34.808 17.544 ;
     RECT  34.808 0.144 34.883 17.544 ;
     RECT  34.729 18.768 34.931 18.792 ;
     RECT  34.883 0.144 34.985 17.4 ;
     RECT  34.985 0.192 35.027 17.4 ;
     RECT  35.027 1.728 35.068 17.4 ;
     RECT  35.068 1.728 35.104 17.022 ;
     RECT  35.027 0.192 35.165 0.6 ;
     RECT  35.165 0.192 35.201 0.264 ;
     RECT  35.201 0.24 35.219 0.264 ;
     RECT  35.104 9.12 35.219 16.536 ;
     RECT  35.029 19.248 35.219 19.272 ;
     RECT  35.104 5.712 35.245 7.992 ;
     RECT  35.219 12.768 35.245 16.536 ;
     RECT  35.245 12.768 35.26 13.128 ;
     RECT  35.245 5.808 35.267 7.992 ;
     RECT  35.26 12.768 35.267 13.08 ;
     RECT  35.245 14.208 35.267 16.536 ;
     RECT  35.267 7.92 35.273 7.992 ;
     RECT  35.219 9.12 35.315 11.736 ;
     RECT  35.104 1.728 35.345 1.752 ;
     RECT  35.267 5.808 35.345 6.84 ;
     RECT  35.267 14.832 35.389 16.536 ;
     RECT  35.273 7.92 35.411 7.944 ;
     RECT  35.315 9.12 35.453 11.64 ;
     RECT  35.104 2.736 35.5 4.536 ;
     RECT  35.413 19.344 35.507 19.368 ;
     RECT  35.453 10.752 35.633 11.64 ;
     RECT  35.633 10.848 35.644 11.64 ;
     RECT  35.453 9.12 35.669 9.672 ;
     RECT  35.389 14.832 35.921 16.104 ;
     RECT  35.345 6.192 35.939 6.744 ;
     RECT  35.939 6.528 36.029 6.744 ;
     RECT  35.669 9.12 36.035 9.192 ;
     RECT  36.029 6.576 36.22 6.744 ;
     RECT  35.5 3.36 36.323 4.536 ;
     RECT  35.921 14.832 36.325 15.432 ;
     RECT  36.325 14.256 36.425 15.24 ;
     RECT  36.323 3.36 36.569 3.432 ;
     RECT  36.323 4.512 36.569 4.536 ;
     RECT  36.035 9.12 36.613 9.144 ;
     RECT  35.267 13.056 36.745 13.08 ;
     RECT  36.565 0.048 36.749 0.072 ;
     RECT  36.425 14.832 37.325 15.24 ;
     RECT  37.277 18.816 37.357 18.84 ;
     RECT  37.357 18.24 37.361 18.84 ;
     RECT  35.644 10.848 37.381 10.92 ;
     RECT  37.321 17.136 37.381 17.16 ;
     RECT  36.613 8.448 37.429 9.144 ;
     RECT  37.381 16.56 37.465 17.16 ;
     RECT  37.381 10.848 37.469 11.352 ;
     RECT  37.357 2.256 37.477 2.28 ;
     RECT  37.469 10.848 37.541 10.92 ;
     RECT  37.465 16.56 37.541 17.256 ;
     RECT  37.477 2.16 37.621 2.28 ;
     RECT  37.429 8.352 37.649 9.144 ;
     RECT  37.621 1.728 37.669 2.28 ;
     RECT  37.357 3.552 37.669 3.576 ;
     RECT  36.22 6.576 37.669 6.6 ;
     RECT  37.669 5.616 37.717 6.6 ;
     RECT  36.745 13.056 37.717 13.704 ;
     RECT  37.325 14.832 37.717 14.904 ;
     RECT  37.609 11.952 37.753 11.976 ;
     RECT  37.717 13.056 37.753 14.904 ;
     RECT  37.669 1.728 37.765 3.576 ;
     RECT  37.717 5.616 37.765 6.84 ;
     RECT  37.765 4.656 37.801 6.84 ;
     RECT  37.717 15.984 37.801 16.008 ;
     RECT  37.541 17.136 37.813 17.256 ;
     RECT  37.361 18.24 37.813 18.264 ;
     RECT  37.801 4.656 37.852 6.264 ;
     RECT  37.852 5.52 37.859 6.264 ;
     RECT  37.753 11.952 37.865 14.904 ;
     RECT  37.813 0.144 37.889 0.168 ;
     RECT  37.765 1.152 37.889 3.576 ;
     RECT  37.889 0.144 38.045 3.576 ;
     RECT  38.045 1.728 38.081 3.576 ;
     RECT  37.865 11.952 38.225 14.856 ;
     RECT  37.541 10.848 38.257 10.872 ;
     RECT  37.649 8.544 38.261 9.144 ;
     RECT  38.225 13.056 38.369 14.856 ;
     RECT  38.045 0.144 38.477 0.6 ;
     RECT  38.477 0.144 38.513 0.552 ;
     RECT  38.513 0.528 38.531 0.552 ;
     RECT  38.257 10.32 38.549 10.872 ;
     RECT  37.813 17.136 38.617 18.264 ;
     RECT  38.261 8.544 38.689 8.568 ;
     RECT  38.225 11.952 38.689 11.976 ;
     RECT  38.689 11.424 38.729 11.976 ;
     RECT  38.689 15.936 38.819 15.96 ;
     RECT  38.729 11.424 38.837 11.688 ;
     RECT  38.369 13.344 38.945 14.856 ;
     RECT  38.617 17.136 39.011 18.312 ;
     RECT  37.859 6.24 39.013 6.264 ;
     RECT  38.081 1.728 39.085 2.808 ;
     RECT  39.013 6.192 39.301 6.264 ;
     RECT  38.689 7.776 39.301 8.568 ;
     RECT  38.945 14.544 39.301 14.856 ;
     RECT  38.437 3.84 39.445 3.96 ;
     RECT  39.085 1.728 39.493 2.856 ;
     RECT  39.445 3.84 39.493 4.008 ;
     RECT  39.011 17.136 39.701 17.64 ;
     RECT  39.493 1.728 39.773 4.008 ;
     RECT  39.773 1.824 39.877 4.008 ;
     RECT  39.877 1.824 39.917 4.632 ;
     RECT  39.301 14.544 39.925 15.432 ;
     RECT  38.549 10.32 39.949 10.344 ;
     RECT  38.837 11.424 39.949 11.448 ;
     RECT  38.945 13.344 40.069 13.368 ;
     RECT  39.925 14.544 40.069 16.008 ;
     RECT  39.917 2.148 40.208 4.632 ;
     RECT  39.301 6.192 40.208 8.568 ;
     RECT  39.949 10.32 40.208 11.448 ;
     RECT  40.069 13.344 40.208 16.008 ;
     RECT  39.701 17.136 40.208 17.292 ;
     RECT  40.208 2.148 40.312 17.292 ;
     RECT  40.312 2.418 40.504 17.022 ;
     RECT  40.165 19.344 40.643 19.368 ;
     RECT  40.504 12.528 40.645 13.128 ;
     RECT  40.504 3.936 40.691 3.96 ;
     RECT  40.504 14.256 40.717 14.28 ;
     RECT  40.504 6.864 40.787 8.52 ;
     RECT  40.504 2.832 40.825 2.856 ;
     RECT  40.787 8.448 40.835 8.52 ;
     RECT  40.787 6.864 40.931 7.416 ;
     RECT  40.835 8.496 40.931 8.52 ;
     RECT  40.645 13.104 40.969 13.128 ;
     RECT  40.931 7.392 40.997 7.416 ;
    LAYER M5 ;
     RECT  14.112 0.016 16.392 0.037 ;
     RECT  9.456 0.016 11.736 0.227 ;
     RECT  32.784 0.016 35.064 0.229 ;
     RECT  4.752 0.016 7.032 0.611 ;
     RECT  4.752 0.611 6.936 1.187 ;
     RECT  9.456 0.227 11.64 1.763 ;
     RECT  23.472 0.016 25.752 1.763 ;
     RECT  28.128 0.016 30.408 1.763 ;
     RECT  32.784 0.229 35.208 1.763 ;
     RECT  28.176 1.763 30.408 1.811 ;
     RECT  9.504 1.763 11.64 1.859 ;
     RECT  13.632 0.037 16.392 1.859 ;
     RECT  28.176 1.811 30.168 1.859 ;
     RECT  9.648 1.859 11.64 1.907 ;
     RECT  13.632 1.859 15.96 1.907 ;
     RECT  28.416 1.859 30.168 1.907 ;
     RECT  13.632 1.907 14.328 2.053 ;
     RECT  9.648 1.907 10.92 2.099 ;
     RECT  2.784 0.037 2.808 2.137 ;
     RECT  5.04 1.187 6.936 2.137 ;
     RECT  8.256 0.037 8.28 2.137 ;
     RECT  18.768 0.016 21.048 2.137 ;
     RECT  37.488 0.016 39.768 2.137 ;
     RECT  37.488 2.137 40.32 2.151 ;
     RECT  37.488 2.151 40.512 2.195 ;
     RECT  18.6 2.137 21.048 2.243 ;
     RECT  15.36 1.907 15.96 2.291 ;
     RECT  21.024 2.243 21.048 2.291 ;
     RECT  23.472 1.763 25.656 2.291 ;
     RECT  28.464 1.907 30.168 2.291 ;
     RECT  33.024 1.763 35.208 2.291 ;
     RECT  37.536 2.195 40.512 2.291 ;
     RECT  15.696 2.291 15.72 2.339 ;
     RECT  18.6 2.243 19.896 2.339 ;
     RECT  34.464 2.291 35.208 2.725 ;
     RECT  5.04 2.137 8.28 2.821 ;
     RECT  39.312 2.291 40.512 2.821 ;
     RECT  2.4 2.137 2.808 2.867 ;
     RECT  10.224 2.099 10.92 2.915 ;
     RECT  13.104 2.053 14.328 2.915 ;
     RECT  29.4 2.291 30.168 2.915 ;
     RECT  34.464 2.725 35.448 2.915 ;
     RECT  37.68 2.291 37.992 2.915 ;
     RECT  10.224 2.915 10.632 3.107 ;
     RECT  18.6 2.339 19.032 3.107 ;
     RECT  27.168 2.725 27.192 3.157 ;
     RECT  37.968 2.915 37.992 3.203 ;
     RECT  13.104 2.915 13.896 3.205 ;
     RECT  18.6 3.107 18.912 3.205 ;
     RECT  23.472 2.291 24.504 3.205 ;
     RECT  27.168 3.157 27.288 3.205 ;
     RECT  28.368 2.869 28.392 3.205 ;
     RECT  34.8 2.915 35.448 3.349 ;
     RECT  5.04 2.821 8.952 3.539 ;
     RECT  17.28 2.677 17.304 3.589 ;
     RECT  18.432 3.205 18.912 3.589 ;
     RECT  10.224 3.107 10.248 3.733 ;
     RECT  27.168 3.205 28.392 3.733 ;
     RECT  22.992 3.205 24.504 3.877 ;
     RECT  17.28 3.589 18.912 3.925 ;
     RECT  21.696 3.877 21.72 3.925 ;
     RECT  22.992 3.877 24.744 3.925 ;
     RECT  26.352 3.733 28.392 3.925 ;
     RECT  29.4 2.915 29.712 3.925 ;
     RECT  39.312 2.821 40.776 3.925 ;
     RECT  5.232 3.539 8.952 4.019 ;
     RECT  16.368 3.925 18.912 4.261 ;
     RECT  33.648 3.349 33.672 4.261 ;
     RECT  34.8 3.349 36.36 4.261 ;
     RECT  10.032 3.733 10.248 4.403 ;
     RECT  31.44 2.821 31.608 4.403 ;
     RECT  2.4 2.867 2.712 4.501 ;
     RECT  31.584 4.403 31.608 4.501 ;
     RECT  26.304 3.925 28.392 4.547 ;
     RECT  12.96 3.205 13.896 4.595 ;
     RECT  38.592 3.925 40.776 4.645 ;
     RECT  16.368 4.261 19.368 4.837 ;
     RECT  5.232 4.019 5.4 5.029 ;
     RECT  13.104 4.595 13.896 5.365 ;
     RECT  15.408 4.837 19.368 5.365 ;
     RECT  21.696 3.925 24.744 5.365 ;
     RECT  2.4 4.501 2.904 5.605 ;
     RECT  5.232 5.029 5.496 5.605 ;
     RECT  6.912 4.019 8.952 5.605 ;
     RECT  37.776 4.645 40.776 5.605 ;
     RECT  26.304 4.547 27.432 5.653 ;
     RECT  13.104 5.365 19.368 5.747 ;
     RECT  4.08 5.077 4.104 6.035 ;
     RECT  13.104 5.747 19.32 6.181 ;
     RECT  21.168 5.365 24.744 6.181 ;
     RECT  25.968 5.653 27.432 6.181 ;
     RECT  29.4 3.925 30.264 6.181 ;
     RECT  5.232 5.605 8.952 6.323 ;
     RECT  37.68 5.605 40.776 6.611 ;
     RECT  6.96 6.323 8.952 6.709 ;
     RECT  29.4 6.181 30.456 6.709 ;
     RECT  31.584 4.501 31.944 6.709 ;
     RECT  2.304 5.605 2.904 6.805 ;
     RECT  29.4 6.709 31.944 6.805 ;
     RECT  33.648 4.261 36.36 6.851 ;
     RECT  37.728 6.611 40.776 6.853 ;
     RECT  11.424 5.077 11.448 7.189 ;
     RECT  37.728 6.853 40.92 7.427 ;
     RECT  28.704 6.805 31.944 7.765 ;
     RECT  33.12 7.237 33.144 7.765 ;
     RECT  5.232 6.323 5.496 8.099 ;
     RECT  2.304 6.805 3.096 8.341 ;
     RECT  37.728 7.427 40.776 8.341 ;
     RECT  34.128 6.851 36.36 8.437 ;
     RECT  37.44 8.341 40.776 8.437 ;
     RECT  2.304 8.341 3.288 8.485 ;
     RECT  34.128 8.437 40.824 8.485 ;
     RECT  28.704 7.765 33.144 8.869 ;
     RECT  11.424 7.189 11.64 9.061 ;
     RECT  12.72 6.181 19.32 9.061 ;
     RECT  34.128 8.485 40.92 9.107 ;
     RECT  34.224 9.107 40.92 9.155 ;
     RECT  5.472 8.099 5.496 9.397 ;
     RECT  11.424 9.061 19.32 9.589 ;
     RECT  11.424 9.589 19.512 10.019 ;
     RECT  21.168 6.181 27.432 10.213 ;
     RECT  5.28 9.397 5.496 10.307 ;
     RECT  28.608 8.869 33.144 10.741 ;
     RECT  34.224 9.155 36.36 10.741 ;
     RECT  6.96 6.709 9.048 10.883 ;
     RECT  11.424 10.019 19.32 10.885 ;
     RECT  11.376 10.885 19.32 11.267 ;
     RECT  37.44 9.155 40.92 11.317 ;
     RECT  10.032 4.403 10.056 11.749 ;
     RECT  11.376 11.267 14.76 11.749 ;
     RECT  6.96 10.883 8.952 12.325 ;
     RECT  2.304 8.485 3.576 12.469 ;
     RECT  28.608 10.741 36.36 12.469 ;
     RECT  21.12 10.213 27.432 12.517 ;
     RECT  28.464 12.469 36.36 12.517 ;
     RECT  21.12 12.517 36.36 12.901 ;
     RECT  20.448 12.901 36.36 13.045 ;
     RECT  37.392 11.317 40.92 13.045 ;
     RECT  6.96 12.325 9.048 13.091 ;
     RECT  20.448 13.045 40.92 13.139 ;
     RECT  6.96 13.091 8.952 13.429 ;
     RECT  10.032 11.749 14.76 13.573 ;
     RECT  5.28 10.307 5.304 13.621 ;
     RECT  16.368 11.267 19.32 13.715 ;
     RECT  20.448 13.139 40.68 13.715 ;
     RECT  34.32 13.715 40.68 14.291 ;
     RECT  20.448 13.715 33.144 14.677 ;
     RECT  2.304 12.469 3.96 14.773 ;
     RECT  5.28 13.621 5.544 14.773 ;
     RECT  16.368 13.715 19.032 14.773 ;
     RECT  20.208 14.677 33.144 14.773 ;
     RECT  16.368 14.773 33.144 14.867 ;
     RECT  2.304 14.773 5.544 15.347 ;
     RECT  5.28 15.347 5.544 15.349 ;
     RECT  6.912 13.429 8.952 15.443 ;
     RECT  10.032 13.573 15.192 15.443 ;
     RECT  31.584 14.867 33.144 15.443 ;
     RECT  34.32 14.291 36.312 15.443 ;
     RECT  37.296 14.291 40.632 15.443 ;
     RECT  10.032 15.443 13.656 15.589 ;
     RECT  5.28 15.349 5.88 16.019 ;
     RECT  9.744 15.589 13.656 16.019 ;
     RECT  14.736 15.443 15.192 16.019 ;
     RECT  16.416 14.867 30.504 16.019 ;
     RECT  31.584 15.443 33.096 16.019 ;
     RECT  34.32 15.443 35.544 16.019 ;
     RECT  39.936 15.443 40.632 16.019 ;
     RECT  2.304 15.347 3.96 16.067 ;
     RECT  31.92 16.019 31.944 16.067 ;
     RECT  34.32 16.019 35.496 16.067 ;
     RECT  2.4 16.067 3.96 16.595 ;
     RECT  28.032 16.019 30.456 16.595 ;
     RECT  6.912 15.443 8.76 16.835 ;
     RECT  32.976 16.019 33.096 16.981 ;
     RECT  3.936 16.595 3.96 17.077 ;
     RECT  5.52 16.019 5.88 17.077 ;
     RECT  6.912 16.835 8.112 17.077 ;
     RECT  9.744 16.019 13.512 17.077 ;
     RECT  14.928 16.019 15.192 17.077 ;
     RECT  16.416 16.019 26.472 17.077 ;
     RECT  32.832 16.981 33.096 17.077 ;
     RECT  34.368 16.067 35.496 17.077 ;
     RECT  37.296 15.443 38.808 17.125 ;
     RECT  40.2 16.019 40.632 17.125 ;
     RECT  2.4 16.595 2.712 17.289 ;
     RECT  3.936 17.077 8.112 17.289 ;
     RECT  2.4 17.289 2.52 17.303 ;
     RECT  3.936 17.289 7.92 17.303 ;
     RECT  9.456 17.077 26.472 17.303 ;
     RECT  3.936 17.303 7.416 17.699 ;
     RECT  9.456 17.303 13.08 18.275 ;
     RECT  3.936 17.699 6.984 18.851 ;
     RECT  9.456 18.275 12.984 18.851 ;
     RECT  14.112 17.303 26.472 18.851 ;
     RECT  37.296 17.125 40.632 18.851 ;
     RECT  28.032 16.595 30.408 19.187 ;
     RECT  4.752 18.851 6.984 19.237 ;
     RECT  12.96 18.851 12.984 19.379 ;
     RECT  14.112 18.851 21.048 19.379 ;
     RECT  22.176 18.851 22.2 19.379 ;
     RECT  32.784 17.077 35.496 19.379 ;
     RECT  37.488 18.851 40.632 19.379 ;
     RECT  4.752 19.237 7.032 19.408 ;
     RECT  9.456 18.851 11.736 19.408 ;
     RECT  14.112 19.379 16.392 19.408 ;
     RECT  18.768 19.379 21.048 19.408 ;
     RECT  23.472 18.851 25.752 19.408 ;
     RECT  28.128 19.187 30.408 19.408 ;
     RECT  32.784 19.379 35.064 19.408 ;
     RECT  37.488 19.379 39.768 19.408 ;
     RECT  7.08 0.037 8.256 0.132 ;
     RECT  8.28 0.037 9.408 0.132 ;
     RECT  7.032 0.132 8.256 0.611 ;
     RECT  8.28 0.132 9.456 1.763 ;
     RECT  6.936 0.611 8.256 2.137 ;
     RECT  8.28 1.763 9.504 1.859 ;
     RECT  28.128 1.763 28.176 1.859 ;
     RECT  30.168 1.811 30.408 2.821 ;
     RECT  8.28 1.859 9.648 2.099 ;
     RECT  28.128 1.859 28.416 1.907 ;
     RECT  14.328 1.907 15.36 2.291 ;
     RECT  28.128 1.907 28.464 2.291 ;
     RECT  8.28 2.099 10.224 2.821 ;
     RECT  19.896 2.243 21.024 2.291 ;
     RECT  14.328 2.291 15.696 2.339 ;
     RECT  28.128 2.291 29.4 2.725 ;
     RECT  33.648 2.291 34.464 2.915 ;
     RECT  37.992 2.291 39.312 3.203 ;
     RECT  17.304 2.677 18.6 3.205 ;
     RECT  27.192 2.725 29.4 2.869 ;
     RECT  8.952 2.821 10.224 3.733 ;
     RECT  30.168 2.821 31.44 2.915 ;
     RECT  27.192 2.869 28.368 3.157 ;
     RECT  28.392 2.869 29.4 4.547 ;
     RECT  29.712 2.915 31.44 3.925 ;
     RECT  33.648 2.915 34.8 3.349 ;
     RECT  18.912 3.107 19.032 4.261 ;
     RECT  27.288 3.157 28.368 3.205 ;
     RECT  37.968 3.203 39.312 3.925 ;
     RECT  17.304 3.205 18.432 3.589 ;
     RECT  33.672 3.349 34.8 4.261 ;
     RECT  8.952 3.733 10.032 6.709 ;
     RECT  21.72 3.877 22.992 3.925 ;
     RECT  30.264 3.925 31.44 4.403 ;
     RECT  37.968 3.925 38.592 4.645 ;
     RECT  5.4 4.019 6.912 5.029 ;
     RECT  10.056 4.403 10.248 5.077 ;
     RECT  30.264 4.403 31.584 6.181 ;
     RECT  36.36 4.645 37.776 5.605 ;
     RECT  13.896 4.837 15.408 5.365 ;
     RECT  5.496 5.029 6.912 5.605 ;
     RECT  2.904 5.077 4.08 6.035 ;
     RECT  4.104 5.077 5.232 6.035 ;
     RECT  10.056 5.077 11.424 10.885 ;
     RECT  36.36 5.605 37.68 6.611 ;
     RECT  24.744 5.653 25.968 6.181 ;
     RECT  2.904 6.035 3.096 6.805 ;
     RECT  11.448 6.181 12.72 7.189 ;
     RECT  30.456 6.181 31.584 6.709 ;
     RECT  5.496 6.323 6.96 10.307 ;
     RECT  36.36 6.611 37.728 8.341 ;
     RECT  9.048 6.709 10.032 10.883 ;
     RECT  27.432 6.805 28.704 8.869 ;
     RECT  33.648 6.851 34.128 7.237 ;
     RECT  11.64 7.189 12.72 9.061 ;
     RECT  31.944 7.237 33.12 7.765 ;
     RECT  33.144 7.237 34.128 9.107 ;
     RECT  40.776 7.427 40.92 8.437 ;
     RECT  5.28 8.099 5.472 9.397 ;
     RECT  36.36 8.341 37.44 8.437 ;
     RECT  40.824 8.437 40.92 8.485 ;
     RECT  27.432 8.869 28.608 12.469 ;
     RECT  33.144 9.107 34.224 10.741 ;
     RECT  36.36 9.155 37.44 11.317 ;
     RECT  8.952 10.883 10.032 12.325 ;
     RECT  10.056 10.885 11.376 11.749 ;
     RECT  36.36 11.317 37.392 13.045 ;
     RECT  9.048 12.325 10.032 13.091 ;
     RECT  3.96 12.469 5.28 14.773 ;
     RECT  27.432 12.469 28.464 12.517 ;
     RECT  19.32 12.901 20.448 13.715 ;
     RECT  8.952 13.091 10.032 15.443 ;
     RECT  15.192 13.573 16.368 14.867 ;
     RECT  5.544 13.621 6.912 15.349 ;
     RECT  19.032 13.715 20.448 14.677 ;
     RECT  33.144 13.715 34.32 15.443 ;
     RECT  36.312 14.291 37.296 15.443 ;
     RECT  19.032 14.677 20.208 14.773 ;
     RECT  15.192 14.867 16.416 17.077 ;
     RECT  30.504 14.867 31.584 16.019 ;
     RECT  3.96 15.347 5.28 16.019 ;
     RECT  5.88 15.349 6.912 17.077 ;
     RECT  8.76 15.443 10.032 15.589 ;
     RECT  13.656 15.443 14.736 16.019 ;
     RECT  33.096 15.443 34.32 16.067 ;
     RECT  38.808 15.443 39.936 16.019 ;
     RECT  8.76 15.589 9.744 16.835 ;
     RECT  3.96 16.019 5.52 17.077 ;
     RECT  13.512 16.019 14.928 17.077 ;
     RECT  30.456 16.019 31.92 16.067 ;
     RECT  31.944 16.019 32.976 16.067 ;
     RECT  38.808 16.019 40.2 17.125 ;
     RECT  32.784 16.067 32.976 16.981 ;
     RECT  33.096 16.067 34.368 17.077 ;
     RECT  2.712 16.595 3.936 17.289 ;
     RECT  8.112 16.835 9.744 17.077 ;
     RECT  32.784 16.981 32.832 17.077 ;
     RECT  8.112 17.077 9.456 17.289 ;
     RECT  2.52 17.289 3.936 17.303 ;
     RECT  13.08 17.303 14.112 18.275 ;
     RECT  12.984 18.275 14.112 19.308 ;
     RECT  11.736 18.851 12.96 19.308 ;
     RECT  21.048 18.851 22.176 19.308 ;
     RECT  22.2 18.851 23.472 19.308 ;
     RECT  11.784 19.308 12.96 19.379 ;
     RECT  12.984 19.308 14.064 19.379 ;
     RECT  21.096 19.308 22.176 19.379 ;
     RECT  22.2 19.308 23.424 19.379 ;
  END
END dsfd_vm_frr
END LIBRARY
